VERSION 5.8 ;
BUSBITCHARS "[]" ;
DIVIDERCHAR "/" ;
UNITS
    DATABASE MICRONS 1000 ;
END UNITS

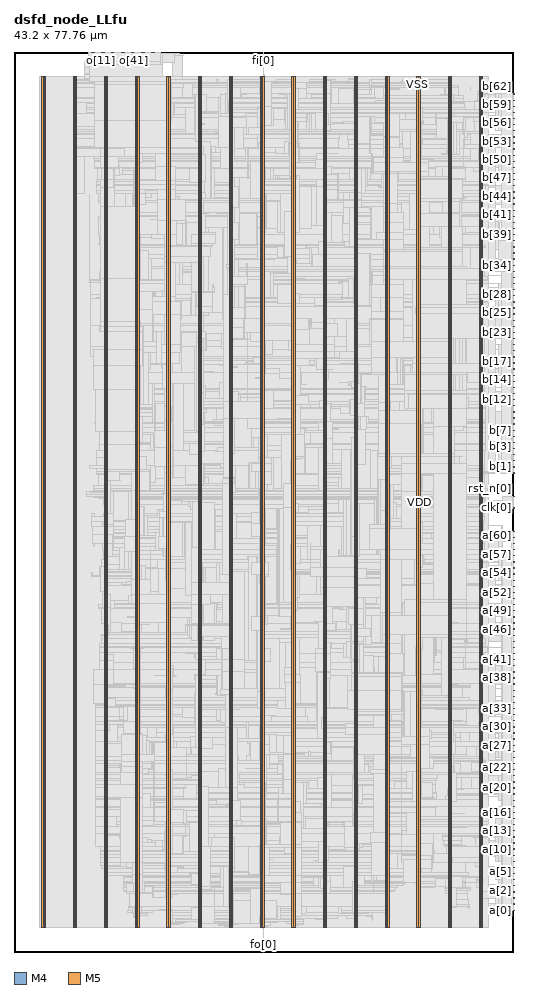
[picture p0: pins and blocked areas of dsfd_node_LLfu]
MACRO dsfd_node_LLfu
  FOREIGN dsfd_node_LLfu 0 0 ;
  CLASS BLOCK ;
  SIZE 43.2 BY 77.76 ;
  PIN a[0]
    DIRECTION INPUT ;
    USE SIGNAL ;
    PORT
      LAYER M4 ;
        RECT  43.116 3.6 43.2 3.624 ;
    END
  END a[0]
  PIN a[10]
    DIRECTION INPUT ;
    USE SIGNAL ;
    PORT
      LAYER M4 ;
        RECT  43.116 8.88 43.2 8.904 ;
    END
  END a[10]
  PIN a[11]
    DIRECTION INPUT ;
    USE SIGNAL ;
    PORT
      LAYER M4 ;
        RECT  43.116 9.408 43.2 9.432 ;
    END
  END a[11]
  PIN a[12]
    DIRECTION INPUT ;
    USE SIGNAL ;
    PORT
      LAYER M4 ;
        RECT  43.116 9.936 43.2 9.96 ;
    END
  END a[12]
  PIN a[13]
    DIRECTION INPUT ;
    USE SIGNAL ;
    PORT
      LAYER M4 ;
        RECT  43.116 10.464 43.2 10.488 ;
    END
  END a[13]
  PIN a[14]
    DIRECTION INPUT ;
    USE SIGNAL ;
    PORT
      LAYER M4 ;
        RECT  43.116 10.992 43.2 11.016 ;
    END
  END a[14]
  PIN a[15]
    DIRECTION INPUT ;
    USE SIGNAL ;
    PORT
      LAYER M4 ;
        RECT  43.116 11.52 43.2 11.544 ;
    END
  END a[15]
  PIN a[16]
    DIRECTION INPUT ;
    USE SIGNAL ;
    PORT
      LAYER M4 ;
        RECT  43.116 12.048 43.2 12.072 ;
    END
  END a[16]
  PIN a[17]
    DIRECTION INPUT ;
    USE SIGNAL ;
    PORT
      LAYER M4 ;
        RECT  43.116 12.576 43.2 12.6 ;
    END
  END a[17]
  PIN a[18]
    DIRECTION INPUT ;
    USE SIGNAL ;
    PORT
      LAYER M4 ;
        RECT  43.116 13.104 43.2 13.128 ;
    END
  END a[18]
  PIN a[19]
    DIRECTION INPUT ;
    USE SIGNAL ;
    PORT
      LAYER M4 ;
        RECT  43.116 13.632 43.2 13.656 ;
    END
  END a[19]
  PIN a[1]
    DIRECTION INPUT ;
    USE SIGNAL ;
    PORT
      LAYER M4 ;
        RECT  43.116 4.128 43.2 4.152 ;
    END
  END a[1]
  PIN a[20]
    DIRECTION INPUT ;
    USE SIGNAL ;
    PORT
      LAYER M4 ;
        RECT  43.116 14.16 43.2 14.184 ;
    END
  END a[20]
  PIN a[21]
    DIRECTION INPUT ;
    USE SIGNAL ;
    PORT
      LAYER M4 ;
        RECT  43.116 14.688 43.2 14.712 ;
    END
  END a[21]
  PIN a[22]
    DIRECTION INPUT ;
    USE SIGNAL ;
    PORT
      LAYER M4 ;
        RECT  43.116 15.216 43.2 15.24 ;
    END
  END a[22]
  PIN a[23]
    DIRECTION INPUT ;
    USE SIGNAL ;
    PORT
      LAYER M4 ;
        RECT  43.116 15.744 43.2 15.768 ;
    END
  END a[23]
  PIN a[24]
    DIRECTION INPUT ;
    USE SIGNAL ;
    PORT
      LAYER M4 ;
        RECT  43.116 16.272 43.2 16.296 ;
    END
  END a[24]
  PIN a[25]
    DIRECTION INPUT ;
    USE SIGNAL ;
    PORT
      LAYER M4 ;
        RECT  43.116 16.8 43.2 16.824 ;
    END
  END a[25]
  PIN a[26]
    DIRECTION INPUT ;
    USE SIGNAL ;
    PORT
      LAYER M4 ;
        RECT  43.116 17.328 43.2 17.352 ;
    END
  END a[26]
  PIN a[27]
    DIRECTION INPUT ;
    USE SIGNAL ;
    PORT
      LAYER M4 ;
        RECT  43.116 17.856 43.2 17.88 ;
    END
  END a[27]
  PIN a[28]
    DIRECTION INPUT ;
    USE SIGNAL ;
    PORT
      LAYER M4 ;
        RECT  43.116 18.384 43.2 18.408 ;
    END
  END a[28]
  PIN a[29]
    DIRECTION INPUT ;
    USE SIGNAL ;
    PORT
      LAYER M4 ;
        RECT  43.116 18.912 43.2 18.936 ;
    END
  END a[29]
  PIN a[2]
    DIRECTION INPUT ;
    USE SIGNAL ;
    PORT
      LAYER M4 ;
        RECT  43.116 4.656 43.2 4.68 ;
    END
  END a[2]
  PIN a[30]
    DIRECTION INPUT ;
    USE SIGNAL ;
    PORT
      LAYER M4 ;
        RECT  43.116 19.44 43.2 19.464 ;
    END
  END a[30]
  PIN a[31]
    DIRECTION INPUT ;
    USE SIGNAL ;
    PORT
      LAYER M4 ;
        RECT  43.116 19.968 43.2 19.992 ;
    END
  END a[31]
  PIN a[32]
    DIRECTION INPUT ;
    USE SIGNAL ;
    PORT
      LAYER M4 ;
        RECT  43.116 20.496 43.2 20.52 ;
    END
  END a[32]
  PIN a[33]
    DIRECTION INPUT ;
    USE SIGNAL ;
    PORT
      LAYER M4 ;
        RECT  43.116 21.024 43.2 21.048 ;
    END
  END a[33]
  PIN a[34]
    DIRECTION INPUT ;
    USE SIGNAL ;
    PORT
      LAYER M4 ;
        RECT  43.116 21.552 43.2 21.576 ;
    END
  END a[34]
  PIN a[35]
    DIRECTION INPUT ;
    USE SIGNAL ;
    PORT
      LAYER M4 ;
        RECT  43.116 22.08 43.2 22.104 ;
    END
  END a[35]
  PIN a[36]
    DIRECTION INPUT ;
    USE SIGNAL ;
    PORT
      LAYER M4 ;
        RECT  43.116 22.608 43.2 22.632 ;
    END
  END a[36]
  PIN a[37]
    DIRECTION INPUT ;
    USE SIGNAL ;
    PORT
      LAYER M4 ;
        RECT  43.116 23.136 43.2 23.16 ;
    END
  END a[37]
  PIN a[38]
    DIRECTION INPUT ;
    USE SIGNAL ;
    PORT
      LAYER M4 ;
        RECT  43.116 23.664 43.2 23.688 ;
    END
  END a[38]
  PIN a[39]
    DIRECTION INPUT ;
    USE SIGNAL ;
    PORT
      LAYER M4 ;
        RECT  43.116 24.192 43.2 24.216 ;
    END
  END a[39]
  PIN a[3]
    DIRECTION INPUT ;
    USE SIGNAL ;
    PORT
      LAYER M4 ;
        RECT  43.116 5.184 43.2 5.208 ;
    END
  END a[3]
  PIN a[40]
    DIRECTION INPUT ;
    USE SIGNAL ;
    PORT
      LAYER M4 ;
        RECT  43.116 24.72 43.2 24.744 ;
    END
  END a[40]
  PIN a[41]
    DIRECTION INPUT ;
    USE SIGNAL ;
    PORT
      LAYER M4 ;
        RECT  43.116 25.248 43.2 25.272 ;
    END
  END a[41]
  PIN a[42]
    DIRECTION INPUT ;
    USE SIGNAL ;
    PORT
      LAYER M4 ;
        RECT  43.116 25.776 43.2 25.8 ;
    END
  END a[42]
  PIN a[43]
    DIRECTION INPUT ;
    USE SIGNAL ;
    PORT
      LAYER M4 ;
        RECT  43.116 26.304 43.2 26.328 ;
    END
  END a[43]
  PIN a[44]
    DIRECTION INPUT ;
    USE SIGNAL ;
    PORT
      LAYER M4 ;
        RECT  43.116 26.832 43.2 26.856 ;
    END
  END a[44]
  PIN a[45]
    DIRECTION INPUT ;
    USE SIGNAL ;
    PORT
      LAYER M4 ;
        RECT  43.116 27.36 43.2 27.384 ;
    END
  END a[45]
  PIN a[46]
    DIRECTION INPUT ;
    USE SIGNAL ;
    PORT
      LAYER M4 ;
        RECT  43.116 27.888 43.2 27.912 ;
    END
  END a[46]
  PIN a[47]
    DIRECTION INPUT ;
    USE SIGNAL ;
    PORT
      LAYER M4 ;
        RECT  43.116 28.416 43.2 28.44 ;
    END
  END a[47]
  PIN a[48]
    DIRECTION INPUT ;
    USE SIGNAL ;
    PORT
      LAYER M4 ;
        RECT  43.116 28.944 43.2 28.968 ;
    END
  END a[48]
  PIN a[49]
    DIRECTION INPUT ;
    USE SIGNAL ;
    PORT
      LAYER M4 ;
        RECT  43.116 29.472 43.2 29.496 ;
    END
  END a[49]
  PIN a[4]
    DIRECTION INPUT ;
    USE SIGNAL ;
    PORT
      LAYER M4 ;
        RECT  43.116 5.712 43.2 5.736 ;
    END
  END a[4]
  PIN a[50]
    DIRECTION INPUT ;
    USE SIGNAL ;
    PORT
      LAYER M4 ;
        RECT  43.116 30 43.2 30.024 ;
    END
  END a[50]
  PIN a[51]
    DIRECTION INPUT ;
    USE SIGNAL ;
    PORT
      LAYER M4 ;
        RECT  43.116 30.528 43.2 30.552 ;
    END
  END a[51]
  PIN a[52]
    DIRECTION INPUT ;
    USE SIGNAL ;
    PORT
      LAYER M4 ;
        RECT  43.116 31.056 43.2 31.08 ;
    END
  END a[52]
  PIN a[53]
    DIRECTION INPUT ;
    USE SIGNAL ;
    PORT
      LAYER M4 ;
        RECT  43.116 31.584 43.2 31.608 ;
    END
  END a[53]
  PIN a[54]
    DIRECTION INPUT ;
    USE SIGNAL ;
    PORT
      LAYER M4 ;
        RECT  43.116 32.112 43.2 32.136 ;
    END
  END a[54]
  PIN a[55]
    DIRECTION INPUT ;
    USE SIGNAL ;
    PORT
      LAYER M4 ;
        RECT  43.116 32.64 43.2 32.664 ;
    END
  END a[55]
  PIN a[56]
    DIRECTION INPUT ;
    USE SIGNAL ;
    PORT
      LAYER M4 ;
        RECT  43.116 33.168 43.2 33.192 ;
    END
  END a[56]
  PIN a[57]
    DIRECTION INPUT ;
    USE SIGNAL ;
    PORT
      LAYER M4 ;
        RECT  43.116 33.696 43.2 33.72 ;
    END
  END a[57]
  PIN a[58]
    DIRECTION INPUT ;
    USE SIGNAL ;
    PORT
      LAYER M4 ;
        RECT  43.116 34.224 43.2 34.248 ;
    END
  END a[58]
  PIN a[59]
    DIRECTION INPUT ;
    USE SIGNAL ;
    PORT
      LAYER M4 ;
        RECT  43.116 34.752 43.2 34.776 ;
    END
  END a[59]
  PIN a[5]
    DIRECTION INPUT ;
    USE SIGNAL ;
    PORT
      LAYER M4 ;
        RECT  43.116 6.24 43.2 6.264 ;
    END
  END a[5]
  PIN a[60]
    DIRECTION INPUT ;
    USE SIGNAL ;
    PORT
      LAYER M4 ;
        RECT  43.116 35.28 43.2 35.304 ;
    END
  END a[60]
  PIN a[61]
    DIRECTION INPUT ;
    USE SIGNAL ;
    PORT
      LAYER M4 ;
        RECT  43.116 35.808 43.2 35.832 ;
    END
  END a[61]
  PIN a[62]
    DIRECTION INPUT ;
    USE SIGNAL ;
    PORT
      LAYER M4 ;
        RECT  43.116 36.336 43.2 36.36 ;
    END
  END a[62]
  PIN a[6]
    DIRECTION INPUT ;
    USE SIGNAL ;
    PORT
      LAYER M4 ;
        RECT  43.116 6.768 43.2 6.792 ;
    END
  END a[6]
  PIN a[7]
    DIRECTION INPUT ;
    USE SIGNAL ;
    PORT
      LAYER M4 ;
        RECT  43.116 7.296 43.2 7.32 ;
    END
  END a[7]
  PIN a[8]
    DIRECTION INPUT ;
    USE SIGNAL ;
    PORT
      LAYER M4 ;
        RECT  43.116 7.824 43.2 7.848 ;
    END
  END a[8]
  PIN a[9]
    DIRECTION INPUT ;
    USE SIGNAL ;
    PORT
      LAYER M4 ;
        RECT  43.116 8.352 43.2 8.376 ;
    END
  END a[9]
  PIN b[0]
    DIRECTION INPUT ;
    USE SIGNAL ;
    PORT
      LAYER M4 ;
        RECT  43.116 41.376 43.2 41.4 ;
    END
  END b[0]
  PIN b[10]
    DIRECTION INPUT ;
    USE SIGNAL ;
    PORT
      LAYER M4 ;
        RECT  43.116 46.656 43.2 46.68 ;
    END
  END b[10]
  PIN b[11]
    DIRECTION INPUT ;
    USE SIGNAL ;
    PORT
      LAYER M4 ;
        RECT  43.116 47.184 43.2 47.208 ;
    END
  END b[11]
  PIN b[12]
    DIRECTION INPUT ;
    USE SIGNAL ;
    PORT
      LAYER M4 ;
        RECT  43.116 47.712 43.2 47.736 ;
    END
  END b[12]
  PIN b[13]
    DIRECTION INPUT ;
    USE SIGNAL ;
    PORT
      LAYER M4 ;
        RECT  43.116 48.24 43.2 48.264 ;
    END
  END b[13]
  PIN b[14]
    DIRECTION INPUT ;
    USE SIGNAL ;
    PORT
      LAYER M4 ;
        RECT  43.116 48.768 43.2 48.792 ;
    END
  END b[14]
  PIN b[15]
    DIRECTION INPUT ;
    USE SIGNAL ;
    PORT
      LAYER M4 ;
        RECT  43.116 49.296 43.2 49.32 ;
    END
  END b[15]
  PIN b[16]
    DIRECTION INPUT ;
    USE SIGNAL ;
    PORT
      LAYER M4 ;
        RECT  43.116 49.824 43.2 49.848 ;
    END
  END b[16]
  PIN b[17]
    DIRECTION INPUT ;
    USE SIGNAL ;
    PORT
      LAYER M4 ;
        RECT  43.116 50.352 43.2 50.376 ;
    END
  END b[17]
  PIN b[18]
    DIRECTION INPUT ;
    USE SIGNAL ;
    PORT
      LAYER M4 ;
        RECT  43.116 50.88 43.2 50.904 ;
    END
  END b[18]
  PIN b[19]
    DIRECTION INPUT ;
    USE SIGNAL ;
    PORT
      LAYER M4 ;
        RECT  43.116 51.408 43.2 51.432 ;
    END
  END b[19]
  PIN b[1]
    DIRECTION INPUT ;
    USE SIGNAL ;
    PORT
      LAYER M4 ;
        RECT  43.116 41.904 43.2 41.928 ;
    END
  END b[1]
  PIN b[20]
    DIRECTION INPUT ;
    USE SIGNAL ;
    PORT
      LAYER M4 ;
        RECT  43.116 51.936 43.2 51.96 ;
    END
  END b[20]
  PIN b[21]
    DIRECTION INPUT ;
    USE SIGNAL ;
    PORT
      LAYER M4 ;
        RECT  43.116 52.464 43.2 52.488 ;
    END
  END b[21]
  PIN b[22]
    DIRECTION INPUT ;
    USE SIGNAL ;
    PORT
      LAYER M4 ;
        RECT  43.116 52.992 43.2 53.016 ;
    END
  END b[22]
  PIN b[23]
    DIRECTION INPUT ;
    USE SIGNAL ;
    PORT
      LAYER M4 ;
        RECT  43.116 53.52 43.2 53.544 ;
    END
  END b[23]
  PIN b[24]
    DIRECTION INPUT ;
    USE SIGNAL ;
    PORT
      LAYER M4 ;
        RECT  43.116 54.048 43.2 54.072 ;
    END
  END b[24]
  PIN b[25]
    DIRECTION INPUT ;
    USE SIGNAL ;
    PORT
      LAYER M4 ;
        RECT  43.116 54.576 43.2 54.6 ;
    END
  END b[25]
  PIN b[26]
    DIRECTION INPUT ;
    USE SIGNAL ;
    PORT
      LAYER M4 ;
        RECT  43.116 55.104 43.2 55.128 ;
    END
  END b[26]
  PIN b[27]
    DIRECTION INPUT ;
    USE SIGNAL ;
    PORT
      LAYER M4 ;
        RECT  43.116 55.632 43.2 55.656 ;
    END
  END b[27]
  PIN b[28]
    DIRECTION INPUT ;
    USE SIGNAL ;
    PORT
      LAYER M4 ;
        RECT  43.116 56.16 43.2 56.184 ;
    END
  END b[28]
  PIN b[29]
    DIRECTION INPUT ;
    USE SIGNAL ;
    PORT
      LAYER M4 ;
        RECT  43.116 56.688 43.2 56.712 ;
    END
  END b[29]
  PIN b[2]
    DIRECTION INPUT ;
    USE SIGNAL ;
    PORT
      LAYER M4 ;
        RECT  43.116 42.432 43.2 42.456 ;
    END
  END b[2]
  PIN b[30]
    DIRECTION INPUT ;
    USE SIGNAL ;
    PORT
      LAYER M4 ;
        RECT  43.116 57.216 43.2 57.24 ;
    END
  END b[30]
  PIN b[31]
    DIRECTION INPUT ;
    USE SIGNAL ;
    PORT
      LAYER M4 ;
        RECT  43.116 57.744 43.2 57.768 ;
    END
  END b[31]
  PIN b[32]
    DIRECTION INPUT ;
    USE SIGNAL ;
    PORT
      LAYER M4 ;
        RECT  43.116 58.272 43.2 58.296 ;
    END
  END b[32]
  PIN b[33]
    DIRECTION INPUT ;
    USE SIGNAL ;
    PORT
      LAYER M4 ;
        RECT  43.116 58.8 43.2 58.824 ;
    END
  END b[33]
  PIN b[34]
    DIRECTION INPUT ;
    USE SIGNAL ;
    PORT
      LAYER M4 ;
        RECT  43.116 59.328 43.2 59.352 ;
    END
  END b[34]
  PIN b[35]
    DIRECTION INPUT ;
    USE SIGNAL ;
    PORT
      LAYER M4 ;
        RECT  43.116 59.856 43.2 59.88 ;
    END
  END b[35]
  PIN b[36]
    DIRECTION INPUT ;
    USE SIGNAL ;
    PORT
      LAYER M4 ;
        RECT  43.116 60.384 43.2 60.408 ;
    END
  END b[36]
  PIN b[37]
    DIRECTION INPUT ;
    USE SIGNAL ;
    PORT
      LAYER M4 ;
        RECT  43.116 60.912 43.2 60.936 ;
    END
  END b[37]
  PIN b[38]
    DIRECTION INPUT ;
    USE SIGNAL ;
    PORT
      LAYER M4 ;
        RECT  43.116 61.44 43.2 61.464 ;
    END
  END b[38]
  PIN b[39]
    DIRECTION INPUT ;
    USE SIGNAL ;
    PORT
      LAYER M4 ;
        RECT  43.116 61.968 43.2 61.992 ;
    END
  END b[39]
  PIN b[3]
    DIRECTION INPUT ;
    USE SIGNAL ;
    PORT
      LAYER M4 ;
        RECT  43.116 42.96 43.2 42.984 ;
    END
  END b[3]
  PIN b[40]
    DIRECTION INPUT ;
    USE SIGNAL ;
    PORT
      LAYER M4 ;
        RECT  43.116 62.496 43.2 62.52 ;
    END
  END b[40]
  PIN b[41]
    DIRECTION INPUT ;
    USE SIGNAL ;
    PORT
      LAYER M4 ;
        RECT  43.116 63.024 43.2 63.048 ;
    END
  END b[41]
  PIN b[42]
    DIRECTION INPUT ;
    USE SIGNAL ;
    PORT
      LAYER M4 ;
        RECT  43.116 63.552 43.2 63.576 ;
    END
  END b[42]
  PIN b[43]
    DIRECTION INPUT ;
    USE SIGNAL ;
    PORT
      LAYER M4 ;
        RECT  43.116 64.08 43.2 64.104 ;
    END
  END b[43]
  PIN b[44]
    DIRECTION INPUT ;
    USE SIGNAL ;
    PORT
      LAYER M4 ;
        RECT  43.116 64.608 43.2 64.632 ;
    END
  END b[44]
  PIN b[45]
    DIRECTION INPUT ;
    USE SIGNAL ;
    PORT
      LAYER M4 ;
        RECT  43.116 65.136 43.2 65.16 ;
    END
  END b[45]
  PIN b[46]
    DIRECTION INPUT ;
    USE SIGNAL ;
    PORT
      LAYER M4 ;
        RECT  43.116 65.664 43.2 65.688 ;
    END
  END b[46]
  PIN b[47]
    DIRECTION INPUT ;
    USE SIGNAL ;
    PORT
      LAYER M4 ;
        RECT  43.116 66.192 43.2 66.216 ;
    END
  END b[47]
  PIN b[48]
    DIRECTION INPUT ;
    USE SIGNAL ;
    PORT
      LAYER M4 ;
        RECT  43.116 66.72 43.2 66.744 ;
    END
  END b[48]
  PIN b[49]
    DIRECTION INPUT ;
    USE SIGNAL ;
    PORT
      LAYER M4 ;
        RECT  43.116 67.248 43.2 67.272 ;
    END
  END b[49]
  PIN b[4]
    DIRECTION INPUT ;
    USE SIGNAL ;
    PORT
      LAYER M4 ;
        RECT  43.116 43.488 43.2 43.512 ;
    END
  END b[4]
  PIN b[50]
    DIRECTION INPUT ;
    USE SIGNAL ;
    PORT
      LAYER M4 ;
        RECT  43.116 67.776 43.2 67.8 ;
    END
  END b[50]
  PIN b[51]
    DIRECTION INPUT ;
    USE SIGNAL ;
    PORT
      LAYER M4 ;
        RECT  43.116 68.304 43.2 68.328 ;
    END
  END b[51]
  PIN b[52]
    DIRECTION INPUT ;
    USE SIGNAL ;
    PORT
      LAYER M4 ;
        RECT  43.116 68.832 43.2 68.856 ;
    END
  END b[52]
  PIN b[53]
    DIRECTION INPUT ;
    USE SIGNAL ;
    PORT
      LAYER M4 ;
        RECT  43.116 69.36 43.2 69.384 ;
    END
  END b[53]
  PIN b[54]
    DIRECTION INPUT ;
    USE SIGNAL ;
    PORT
      LAYER M4 ;
        RECT  43.116 69.888 43.2 69.912 ;
    END
  END b[54]
  PIN b[55]
    DIRECTION INPUT ;
    USE SIGNAL ;
    PORT
      LAYER M4 ;
        RECT  43.116 70.416 43.2 70.44 ;
    END
  END b[55]
  PIN b[56]
    DIRECTION INPUT ;
    USE SIGNAL ;
    PORT
      LAYER M4 ;
        RECT  43.116 70.944 43.2 70.968 ;
    END
  END b[56]
  PIN b[57]
    DIRECTION INPUT ;
    USE SIGNAL ;
    PORT
      LAYER M4 ;
        RECT  43.116 71.472 43.2 71.496 ;
    END
  END b[57]
  PIN b[58]
    DIRECTION INPUT ;
    USE SIGNAL ;
    PORT
      LAYER M4 ;
        RECT  43.116 72 43.2 72.024 ;
    END
  END b[58]
  PIN b[59]
    DIRECTION INPUT ;
    USE SIGNAL ;
    PORT
      LAYER M4 ;
        RECT  43.116 72.528 43.2 72.552 ;
    END
  END b[59]
  PIN b[5]
    DIRECTION INPUT ;
    USE SIGNAL ;
    PORT
      LAYER M4 ;
        RECT  43.116 44.016 43.2 44.04 ;
    END
  END b[5]
  PIN b[60]
    DIRECTION INPUT ;
    USE SIGNAL ;
    PORT
      LAYER M4 ;
        RECT  43.116 73.056 43.2 73.08 ;
    END
  END b[60]
  PIN b[61]
    DIRECTION INPUT ;
    USE SIGNAL ;
    PORT
      LAYER M4 ;
        RECT  43.116 73.584 43.2 73.608 ;
    END
  END b[61]
  PIN b[62]
    DIRECTION INPUT ;
    USE SIGNAL ;
    PORT
      LAYER M4 ;
        RECT  43.116 74.112 43.2 74.136 ;
    END
  END b[62]
  PIN b[6]
    DIRECTION INPUT ;
    USE SIGNAL ;
    PORT
      LAYER M4 ;
        RECT  43.116 44.544 43.2 44.568 ;
    END
  END b[6]
  PIN b[7]
    DIRECTION INPUT ;
    USE SIGNAL ;
    PORT
      LAYER M4 ;
        RECT  43.116 45.072 43.2 45.096 ;
    END
  END b[7]
  PIN b[8]
    DIRECTION INPUT ;
    USE SIGNAL ;
    PORT
      LAYER M4 ;
        RECT  43.116 45.6 43.2 45.624 ;
    END
  END b[8]
  PIN b[9]
    DIRECTION INPUT ;
    USE SIGNAL ;
    PORT
      LAYER M4 ;
        RECT  43.116 46.128 43.2 46.152 ;
    END
  END b[9]
  PIN clk[0]
    DIRECTION INPUT ;
    USE SIGNAL ;
    PORT
      LAYER M4 ;
        RECT  43.116 38.352 43.2 38.376 ;
    END
  END clk[0]
  PIN fi[0]
    DIRECTION INPUT ;
    USE SIGNAL ;
    PORT
      LAYER M5 ;
        RECT  21.552 77.676 21.576 77.76 ;
    END
  END fi[0]
  PIN fo[0]
    DIRECTION OUTPUT ;
    USE SIGNAL ;
    PORT
      LAYER M5 ;
        RECT  21.552 0 21.576 0.084 ;
    END
  END fo[0]
  PIN o[0]
    DIRECTION OUTPUT ;
    USE SIGNAL ;
    PORT
      LAYER M5 ;
        RECT  6.432 77.676 6.456 77.76 ;
    END
  END o[0]
  PIN o[10]
    DIRECTION OUTPUT ;
    USE SIGNAL ;
    PORT
      LAYER M5 ;
        RECT  7.392 77.676 7.416 77.76 ;
    END
  END o[10]
  PIN o[11]
    DIRECTION OUTPUT ;
    USE SIGNAL ;
    PORT
      LAYER M5 ;
        RECT  7.488 77.676 7.512 77.76 ;
    END
  END o[11]
  PIN o[12]
    DIRECTION OUTPUT ;
    USE SIGNAL ;
    PORT
      LAYER M5 ;
        RECT  7.584 77.676 7.608 77.76 ;
    END
  END o[12]
  PIN o[13]
    DIRECTION OUTPUT ;
    USE SIGNAL ;
    PORT
      LAYER M5 ;
        RECT  7.68 77.676 7.704 77.76 ;
    END
  END o[13]
  PIN o[14]
    DIRECTION OUTPUT ;
    USE SIGNAL ;
    PORT
      LAYER M5 ;
        RECT  7.776 77.676 7.8 77.76 ;
    END
  END o[14]
  PIN o[15]
    DIRECTION OUTPUT ;
    USE SIGNAL ;
    PORT
      LAYER M5 ;
        RECT  7.872 77.676 7.896 77.76 ;
    END
  END o[15]
  PIN o[16]
    DIRECTION OUTPUT ;
    USE SIGNAL ;
    PORT
      LAYER M5 ;
        RECT  7.968 77.676 7.992 77.76 ;
    END
  END o[16]
  PIN o[17]
    DIRECTION OUTPUT ;
    USE SIGNAL ;
    PORT
      LAYER M5 ;
        RECT  8.064 77.676 8.088 77.76 ;
    END
  END o[17]
  PIN o[18]
    DIRECTION OUTPUT ;
    USE SIGNAL ;
    PORT
      LAYER M5 ;
        RECT  8.16 77.676 8.184 77.76 ;
    END
  END o[18]
  PIN o[19]
    DIRECTION OUTPUT ;
    USE SIGNAL ;
    PORT
      LAYER M5 ;
        RECT  8.256 77.676 8.28 77.76 ;
    END
  END o[19]
  PIN o[1]
    DIRECTION OUTPUT ;
    USE SIGNAL ;
    PORT
      LAYER M5 ;
        RECT  6.528 77.676 6.552 77.76 ;
    END
  END o[1]
  PIN o[20]
    DIRECTION OUTPUT ;
    USE SIGNAL ;
    PORT
      LAYER M5 ;
        RECT  8.352 77.676 8.376 77.76 ;
    END
  END o[20]
  PIN o[21]
    DIRECTION OUTPUT ;
    USE SIGNAL ;
    PORT
      LAYER M5 ;
        RECT  8.448 77.676 8.472 77.76 ;
    END
  END o[21]
  PIN o[22]
    DIRECTION OUTPUT ;
    USE SIGNAL ;
    PORT
      LAYER M5 ;
        RECT  8.544 77.676 8.568 77.76 ;
    END
  END o[22]
  PIN o[23]
    DIRECTION OUTPUT ;
    USE SIGNAL ;
    PORT
      LAYER M5 ;
        RECT  8.64 77.676 8.664 77.76 ;
    END
  END o[23]
  PIN o[24]
    DIRECTION OUTPUT ;
    USE SIGNAL ;
    PORT
      LAYER M5 ;
        RECT  8.736 77.676 8.76 77.76 ;
    END
  END o[24]
  PIN o[25]
    DIRECTION OUTPUT ;
    USE SIGNAL ;
    PORT
      LAYER M5 ;
        RECT  8.832 77.676 8.856 77.76 ;
    END
  END o[25]
  PIN o[26]
    DIRECTION OUTPUT ;
    USE SIGNAL ;
    PORT
      LAYER M5 ;
        RECT  8.928 77.676 8.952 77.76 ;
    END
  END o[26]
  PIN o[27]
    DIRECTION OUTPUT ;
    USE SIGNAL ;
    PORT
      LAYER M5 ;
        RECT  9.024 77.676 9.048 77.76 ;
    END
  END o[27]
  PIN o[28]
    DIRECTION OUTPUT ;
    USE SIGNAL ;
    PORT
      LAYER M5 ;
        RECT  9.12 77.676 9.144 77.76 ;
    END
  END o[28]
  PIN o[29]
    DIRECTION OUTPUT ;
    USE SIGNAL ;
    PORT
      LAYER M5 ;
        RECT  9.216 77.676 9.24 77.76 ;
    END
  END o[29]
  PIN o[2]
    DIRECTION OUTPUT ;
    USE SIGNAL ;
    PORT
      LAYER M5 ;
        RECT  6.624 77.676 6.648 77.76 ;
    END
  END o[2]
  PIN o[30]
    DIRECTION OUTPUT ;
    USE SIGNAL ;
    PORT
      LAYER M5 ;
        RECT  9.312 77.676 9.336 77.76 ;
    END
  END o[30]
  PIN o[31]
    DIRECTION OUTPUT ;
    USE SIGNAL ;
    PORT
      LAYER M5 ;
        RECT  9.408 77.676 9.432 77.76 ;
    END
  END o[31]
  PIN o[32]
    DIRECTION OUTPUT ;
    USE SIGNAL ;
    PORT
      LAYER M5 ;
        RECT  9.504 77.676 9.528 77.76 ;
    END
  END o[32]
  PIN o[33]
    DIRECTION OUTPUT ;
    USE SIGNAL ;
    PORT
      LAYER M5 ;
        RECT  9.6 77.676 9.624 77.76 ;
    END
  END o[33]
  PIN o[34]
    DIRECTION OUTPUT ;
    USE SIGNAL ;
    PORT
      LAYER M5 ;
        RECT  9.696 77.676 9.72 77.76 ;
    END
  END o[34]
  PIN o[35]
    DIRECTION OUTPUT ;
    USE SIGNAL ;
    PORT
      LAYER M5 ;
        RECT  9.792 77.676 9.816 77.76 ;
    END
  END o[35]
  PIN o[36]
    DIRECTION OUTPUT ;
    USE SIGNAL ;
    PORT
      LAYER M5 ;
        RECT  9.888 77.676 9.912 77.76 ;
    END
  END o[36]
  PIN o[37]
    DIRECTION OUTPUT ;
    USE SIGNAL ;
    PORT
      LAYER M5 ;
        RECT  9.984 77.676 10.008 77.76 ;
    END
  END o[37]
  PIN o[38]
    DIRECTION OUTPUT ;
    USE SIGNAL ;
    PORT
      LAYER M5 ;
        RECT  10.08 77.676 10.104 77.76 ;
    END
  END o[38]
  PIN o[39]
    DIRECTION OUTPUT ;
    USE SIGNAL ;
    PORT
      LAYER M5 ;
        RECT  10.176 77.676 10.2 77.76 ;
    END
  END o[39]
  PIN o[3]
    DIRECTION OUTPUT ;
    USE SIGNAL ;
    PORT
      LAYER M5 ;
        RECT  6.72 77.676 6.744 77.76 ;
    END
  END o[3]
  PIN o[40]
    DIRECTION OUTPUT ;
    USE SIGNAL ;
    PORT
      LAYER M5 ;
        RECT  10.272 77.676 10.296 77.76 ;
    END
  END o[40]
  PIN o[41]
    DIRECTION OUTPUT ;
    USE SIGNAL ;
    PORT
      LAYER M5 ;
        RECT  10.368 77.676 10.392 77.76 ;
    END
  END o[41]
  PIN o[42]
    DIRECTION OUTPUT ;
    USE SIGNAL ;
    PORT
      LAYER M5 ;
        RECT  10.464 77.676 10.488 77.76 ;
    END
  END o[42]
  PIN o[43]
    DIRECTION OUTPUT ;
    USE SIGNAL ;
    PORT
      LAYER M5 ;
        RECT  10.56 77.676 10.584 77.76 ;
    END
  END o[43]
  PIN o[44]
    DIRECTION OUTPUT ;
    USE SIGNAL ;
    PORT
      LAYER M5 ;
        RECT  10.656 77.676 10.68 77.76 ;
    END
  END o[44]
  PIN o[45]
    DIRECTION OUTPUT ;
    USE SIGNAL ;
    PORT
      LAYER M5 ;
        RECT  10.752 77.676 10.776 77.76 ;
    END
  END o[45]
  PIN o[46]
    DIRECTION OUTPUT ;
    USE SIGNAL ;
    PORT
      LAYER M5 ;
        RECT  10.848 77.676 10.872 77.76 ;
    END
  END o[46]
  PIN o[47]
    DIRECTION OUTPUT ;
    USE SIGNAL ;
    PORT
      LAYER M5 ;
        RECT  10.944 77.676 10.968 77.76 ;
    END
  END o[47]
  PIN o[48]
    DIRECTION OUTPUT ;
    USE SIGNAL ;
    PORT
      LAYER M5 ;
        RECT  11.04 77.676 11.064 77.76 ;
    END
  END o[48]
  PIN o[49]
    DIRECTION OUTPUT ;
    USE SIGNAL ;
    PORT
      LAYER M5 ;
        RECT  11.136 77.676 11.16 77.76 ;
    END
  END o[49]
  PIN o[4]
    DIRECTION OUTPUT ;
    USE SIGNAL ;
    PORT
      LAYER M5 ;
        RECT  6.816 77.676 6.84 77.76 ;
    END
  END o[4]
  PIN o[50]
    DIRECTION OUTPUT ;
    USE SIGNAL ;
    PORT
      LAYER M5 ;
        RECT  11.232 77.676 11.256 77.76 ;
    END
  END o[50]
  PIN o[51]
    DIRECTION OUTPUT ;
    USE SIGNAL ;
    PORT
      LAYER M5 ;
        RECT  11.328 77.676 11.352 77.76 ;
    END
  END o[51]
  PIN o[52]
    DIRECTION OUTPUT ;
    USE SIGNAL ;
    PORT
      LAYER M5 ;
        RECT  11.424 77.676 11.448 77.76 ;
    END
  END o[52]
  PIN o[53]
    DIRECTION OUTPUT ;
    USE SIGNAL ;
    PORT
      LAYER M5 ;
        RECT  11.52 77.676 11.544 77.76 ;
    END
  END o[53]
  PIN o[54]
    DIRECTION OUTPUT ;
    USE SIGNAL ;
    PORT
      LAYER M5 ;
        RECT  11.616 77.676 11.64 77.76 ;
    END
  END o[54]
  PIN o[55]
    DIRECTION OUTPUT ;
    USE SIGNAL ;
    PORT
      LAYER M5 ;
        RECT  11.712 77.676 11.736 77.76 ;
    END
  END o[55]
  PIN o[56]
    DIRECTION OUTPUT ;
    USE SIGNAL ;
    PORT
      LAYER M5 ;
        RECT  11.808 77.676 11.832 77.76 ;
    END
  END o[56]
  PIN o[57]
    DIRECTION OUTPUT ;
    USE SIGNAL ;
    PORT
      LAYER M5 ;
        RECT  11.904 77.676 11.928 77.76 ;
    END
  END o[57]
  PIN o[58]
    DIRECTION OUTPUT ;
    USE SIGNAL ;
    PORT
      LAYER M5 ;
        RECT  12 77.676 12.024 77.76 ;
    END
  END o[58]
  PIN o[59]
    DIRECTION OUTPUT ;
    USE SIGNAL ;
    PORT
      LAYER M5 ;
        RECT  12.096 77.676 12.12 77.76 ;
    END
  END o[59]
  PIN o[5]
    DIRECTION OUTPUT ;
    USE SIGNAL ;
    PORT
      LAYER M5 ;
        RECT  6.912 77.676 6.936 77.76 ;
    END
  END o[5]
  PIN o[60]
    DIRECTION OUTPUT ;
    USE SIGNAL ;
    PORT
      LAYER M5 ;
        RECT  12.192 77.676 12.216 77.76 ;
    END
  END o[60]
  PIN o[61]
    DIRECTION OUTPUT ;
    USE SIGNAL ;
    PORT
      LAYER M5 ;
        RECT  12.288 77.676 12.312 77.76 ;
    END
  END o[61]
  PIN o[62]
    DIRECTION OUTPUT ;
    USE SIGNAL ;
    PORT
      LAYER M5 ;
        RECT  12.384 77.676 12.408 77.76 ;
    END
  END o[62]
  PIN o[63]
    DIRECTION OUTPUT ;
    USE SIGNAL ;
    PORT
      LAYER M5 ;
        RECT  12.48 77.676 12.504 77.76 ;
    END
  END o[63]
  PIN o[64]
    DIRECTION OUTPUT ;
    USE SIGNAL ;
    PORT
      LAYER M5 ;
        RECT  12.576 77.676 12.6 77.76 ;
    END
  END o[64]
  PIN o[65]
    DIRECTION OUTPUT ;
    USE SIGNAL ;
    PORT
      LAYER M5 ;
        RECT  12.672 77.676 12.696 77.76 ;
    END
  END o[65]
  PIN o[6]
    DIRECTION OUTPUT ;
    USE SIGNAL ;
    PORT
      LAYER M5 ;
        RECT  7.008 77.676 7.032 77.76 ;
    END
  END o[6]
  PIN o[7]
    DIRECTION OUTPUT ;
    USE SIGNAL ;
    PORT
      LAYER M5 ;
        RECT  7.104 77.676 7.128 77.76 ;
    END
  END o[7]
  PIN o[8]
    DIRECTION OUTPUT ;
    USE SIGNAL ;
    PORT
      LAYER M5 ;
        RECT  7.2 77.676 7.224 77.76 ;
    END
  END o[8]
  PIN o[9]
    DIRECTION OUTPUT ;
    USE SIGNAL ;
    PORT
      LAYER M5 ;
        RECT  7.296 77.676 7.32 77.76 ;
    END
  END o[9]
  PIN rst_n[0]
    DIRECTION INPUT ;
    USE SIGNAL ;
    PORT
      LAYER M4 ;
        RECT  43.116 39.36 43.2 39.384 ;
    END
  END rst_n[0]
  PIN VDD
    DIRECTION INOUT ;
    USE POWER ;
    PORT
      LAYER M5 ;
        RECT  40.392 2.151 40.512 75.609 ;
        RECT  37.692 2.151 37.812 75.609 ;
        RECT  34.992 2.151 35.112 75.609 ;
        RECT  32.292 2.151 32.412 75.609 ;
        RECT  29.592 2.151 29.712 75.609 ;
        RECT  26.892 2.151 27.012 75.609 ;
        RECT  24.192 2.151 24.312 75.609 ;
        RECT  21.492 2.151 21.612 75.609 ;
        RECT  18.792 2.151 18.912 75.609 ;
        RECT  16.092 2.151 16.212 75.609 ;
        RECT  13.392 2.151 13.512 75.609 ;
        RECT  10.692 2.151 10.812 75.609 ;
        RECT  7.992 2.151 8.112 75.609 ;
        RECT  5.292 2.151 5.412 75.609 ;
        RECT  2.592 2.151 2.712 75.609 ;
    END
  END VDD
  PIN VSS
    DIRECTION INOUT ;
    USE GROUND ;
    PORT
      LAYER M5 ;
        RECT  40.2 2.137 40.32 75.623 ;
        RECT  37.5 2.137 37.62 75.623 ;
        RECT  34.8 2.137 34.92 75.623 ;
        RECT  32.1 2.137 32.22 75.623 ;
        RECT  29.4 2.137 29.52 75.623 ;
        RECT  26.7 2.137 26.82 75.623 ;
        RECT  24 2.137 24.12 75.623 ;
        RECT  21.3 2.137 21.42 75.623 ;
        RECT  18.6 2.137 18.72 75.623 ;
        RECT  15.9 2.137 16.02 75.623 ;
        RECT  13.2 2.137 13.32 75.623 ;
        RECT  10.5 2.137 10.62 75.623 ;
        RECT  7.8 2.137 7.92 75.623 ;
        RECT  5.1 2.137 5.22 75.623 ;
        RECT  2.4 2.137 2.52 75.623 ;
    END
  END VSS
  OBS
    LAYER RVTN ;
     RECT  2.16 2.16 41.04 2.295 ;
     RECT  2.16 2.565 41.04 2.835 ;
     RECT  2.16 3.105 41.04 3.375 ;
     RECT  2.16 3.645 41.04 3.915 ;
     RECT  2.16 4.185 41.04 4.455 ;
     RECT  2.16 4.725 41.04 4.995 ;
     RECT  2.16 5.265 41.04 5.535 ;
     RECT  2.16 5.805 41.04 6.075 ;
     RECT  2.16 6.345 41.04 6.615 ;
     RECT  2.16 6.885 41.04 7.155 ;
     RECT  2.16 7.425 41.04 7.695 ;
     RECT  2.16 7.965 41.04 8.235 ;
     RECT  2.16 8.505 41.04 8.775 ;
     RECT  2.16 9.045 41.04 9.315 ;
     RECT  2.16 9.585 41.04 9.855 ;
     RECT  2.16 10.125 41.04 10.395 ;
     RECT  2.16 10.665 41.04 10.935 ;
     RECT  2.16 11.205 41.04 11.475 ;
     RECT  2.16 11.745 41.04 12.015 ;
     RECT  2.16 12.285 41.04 12.555 ;
     RECT  2.16 12.825 41.04 13.095 ;
     RECT  2.16 13.365 41.04 13.635 ;
     RECT  2.16 13.905 41.04 14.175 ;
     RECT  2.16 14.445 41.04 14.715 ;
     RECT  2.16 14.985 41.04 15.255 ;
     RECT  2.16 15.525 41.04 15.795 ;
     RECT  2.16 16.065 41.04 16.335 ;
     RECT  2.16 16.605 41.04 16.875 ;
     RECT  2.16 17.145 41.04 17.415 ;
     RECT  2.16 17.685 41.04 17.955 ;
     RECT  2.16 18.225 41.04 18.495 ;
     RECT  2.16 18.765 41.04 19.035 ;
     RECT  2.16 19.305 41.04 19.575 ;
     RECT  2.16 19.845 41.04 20.115 ;
     RECT  2.16 20.385 41.04 20.655 ;
     RECT  2.16 20.925 41.04 21.195 ;
     RECT  2.16 21.465 41.04 21.735 ;
     RECT  2.16 22.005 41.04 22.275 ;
     RECT  2.16 22.545 41.04 22.815 ;
     RECT  2.16 23.085 41.04 23.355 ;
     RECT  2.16 23.625 41.04 23.895 ;
     RECT  2.16 24.165 41.04 24.435 ;
     RECT  2.16 24.705 41.04 24.975 ;
     RECT  2.16 25.245 41.04 25.515 ;
     RECT  2.16 25.785 41.04 26.055 ;
     RECT  2.16 26.325 41.04 26.595 ;
     RECT  2.16 26.865 41.04 27.135 ;
     RECT  2.16 27.405 41.04 27.675 ;
     RECT  2.16 27.945 41.04 28.215 ;
     RECT  2.16 28.485 41.04 28.755 ;
     RECT  2.16 29.025 41.04 29.295 ;
     RECT  2.16 29.565 41.04 29.835 ;
     RECT  2.16 30.105 41.04 30.375 ;
     RECT  2.16 30.645 41.04 30.915 ;
     RECT  2.16 31.185 41.04 31.455 ;
     RECT  2.16 31.725 41.04 31.995 ;
     RECT  2.16 32.265 41.04 32.535 ;
     RECT  2.16 32.805 41.04 33.075 ;
     RECT  2.16 33.345 41.04 33.615 ;
     RECT  2.16 33.885 41.04 34.155 ;
     RECT  2.16 34.425 41.04 34.695 ;
     RECT  2.16 34.965 41.04 35.235 ;
     RECT  2.16 35.505 41.04 35.775 ;
     RECT  2.16 36.045 41.04 36.315 ;
     RECT  2.16 36.585 41.04 36.855 ;
     RECT  2.16 37.125 41.04 37.395 ;
     RECT  2.16 37.665 41.04 37.935 ;
     RECT  2.16 38.205 41.04 38.475 ;
     RECT  2.16 38.745 41.04 39.015 ;
     RECT  2.16 39.285 41.04 39.555 ;
     RECT  2.16 39.825 41.04 40.095 ;
     RECT  2.16 40.365 41.04 40.635 ;
     RECT  2.16 40.905 41.04 41.175 ;
     RECT  2.16 41.445 41.04 41.715 ;
     RECT  2.16 41.985 41.04 42.255 ;
     RECT  2.16 42.525 41.04 42.795 ;
     RECT  2.16 43.065 41.04 43.335 ;
     RECT  2.16 43.605 41.04 43.875 ;
     RECT  2.16 44.145 41.04 44.415 ;
     RECT  2.16 44.685 41.04 44.955 ;
     RECT  2.16 45.225 41.04 45.495 ;
     RECT  2.16 45.765 41.04 46.035 ;
     RECT  2.16 46.305 41.04 46.575 ;
     RECT  2.16 46.845 41.04 47.115 ;
     RECT  2.16 47.385 41.04 47.655 ;
     RECT  2.16 47.925 41.04 48.195 ;
     RECT  2.16 48.465 41.04 48.735 ;
     RECT  2.16 49.005 41.04 49.275 ;
     RECT  2.16 49.545 41.04 49.815 ;
     RECT  2.16 50.085 41.04 50.355 ;
     RECT  2.16 50.625 41.04 50.895 ;
     RECT  2.16 51.165 41.04 51.435 ;
     RECT  2.16 51.705 41.04 51.975 ;
     RECT  2.16 52.245 41.04 52.515 ;
     RECT  2.16 52.785 41.04 53.055 ;
     RECT  2.16 53.325 41.04 53.595 ;
     RECT  2.16 53.865 41.04 54.135 ;
     RECT  2.16 54.405 41.04 54.675 ;
     RECT  2.16 54.945 41.04 55.215 ;
     RECT  2.16 55.485 41.04 55.755 ;
     RECT  2.16 56.025 41.04 56.295 ;
     RECT  2.16 56.565 41.04 56.835 ;
     RECT  2.16 57.105 41.04 57.375 ;
     RECT  2.16 57.645 41.04 57.915 ;
     RECT  2.16 58.185 41.04 58.455 ;
     RECT  2.16 58.725 41.04 58.995 ;
     RECT  2.16 59.265 41.04 59.535 ;
     RECT  2.16 59.805 41.04 60.075 ;
     RECT  2.16 60.345 41.04 60.615 ;
     RECT  2.16 60.885 41.04 61.155 ;
     RECT  2.16 61.425 41.04 61.695 ;
     RECT  2.16 61.965 41.04 62.235 ;
     RECT  2.16 62.505 41.04 62.775 ;
     RECT  2.16 63.045 41.04 63.315 ;
     RECT  2.16 63.585 41.04 63.855 ;
     RECT  2.16 64.125 41.04 64.395 ;
     RECT  2.16 64.665 41.04 64.935 ;
     RECT  2.16 65.205 41.04 65.475 ;
     RECT  2.16 65.745 41.04 66.015 ;
     RECT  2.16 66.285 41.04 66.555 ;
     RECT  2.16 66.825 41.04 67.095 ;
     RECT  2.16 67.365 41.04 67.635 ;
     RECT  2.16 67.905 41.04 68.175 ;
     RECT  2.16 68.445 41.04 68.715 ;
     RECT  2.16 68.985 41.04 69.255 ;
     RECT  2.16 69.525 41.04 69.795 ;
     RECT  2.16 70.065 41.04 70.335 ;
     RECT  2.16 70.605 41.04 70.875 ;
     RECT  2.16 71.145 41.04 71.415 ;
     RECT  2.16 71.685 41.04 71.955 ;
     RECT  2.16 72.225 41.04 72.495 ;
     RECT  2.16 72.765 41.04 73.035 ;
     RECT  2.16 73.305 41.04 73.575 ;
     RECT  2.16 73.845 41.04 74.115 ;
     RECT  2.16 74.385 41.04 74.655 ;
     RECT  2.16 74.925 41.04 75.195 ;
     RECT  2.16 75.465 41.04 75.6 ;
    LAYER RVTP ;
     RECT  2.16 2.295 41.04 2.565 ;
     RECT  2.16 2.835 41.04 3.105 ;
     RECT  2.16 3.375 41.04 3.645 ;
     RECT  2.16 3.915 41.04 4.185 ;
     RECT  2.16 4.455 41.04 4.725 ;
     RECT  2.16 4.995 41.04 5.265 ;
     RECT  2.16 5.535 41.04 5.805 ;
     RECT  2.16 6.075 41.04 6.345 ;
     RECT  2.16 6.615 41.04 6.885 ;
     RECT  2.16 7.155 41.04 7.425 ;
     RECT  2.16 7.695 41.04 7.965 ;
     RECT  2.16 8.235 41.04 8.505 ;
     RECT  2.16 8.775 41.04 9.045 ;
     RECT  2.16 9.315 41.04 9.585 ;
     RECT  2.16 9.855 41.04 10.125 ;
     RECT  2.16 10.395 41.04 10.665 ;
     RECT  2.16 10.935 41.04 11.205 ;
     RECT  2.16 11.475 41.04 11.745 ;
     RECT  2.16 12.015 41.04 12.285 ;
     RECT  2.16 12.555 41.04 12.825 ;
     RECT  2.16 13.095 41.04 13.365 ;
     RECT  2.16 13.635 41.04 13.905 ;
     RECT  2.16 14.175 41.04 14.445 ;
     RECT  2.16 14.715 41.04 14.985 ;
     RECT  2.16 15.255 41.04 15.525 ;
     RECT  2.16 15.795 41.04 16.065 ;
     RECT  2.16 16.335 41.04 16.605 ;
     RECT  2.16 16.875 41.04 17.145 ;
     RECT  2.16 17.415 41.04 17.685 ;
     RECT  2.16 17.955 41.04 18.225 ;
     RECT  2.16 18.495 41.04 18.765 ;
     RECT  2.16 19.035 41.04 19.305 ;
     RECT  2.16 19.575 41.04 19.845 ;
     RECT  2.16 20.115 41.04 20.385 ;
     RECT  2.16 20.655 41.04 20.925 ;
     RECT  2.16 21.195 41.04 21.465 ;
     RECT  2.16 21.735 41.04 22.005 ;
     RECT  2.16 22.275 41.04 22.545 ;
     RECT  2.16 22.815 41.04 23.085 ;
     RECT  2.16 23.355 41.04 23.625 ;
     RECT  2.16 23.895 41.04 24.165 ;
     RECT  2.16 24.435 41.04 24.705 ;
     RECT  2.16 24.975 41.04 25.245 ;
     RECT  2.16 25.515 41.04 25.785 ;
     RECT  2.16 26.055 41.04 26.325 ;
     RECT  2.16 26.595 41.04 26.865 ;
     RECT  2.16 27.135 41.04 27.405 ;
     RECT  2.16 27.675 41.04 27.945 ;
     RECT  2.16 28.215 41.04 28.485 ;
     RECT  2.16 28.755 41.04 29.025 ;
     RECT  2.16 29.295 41.04 29.565 ;
     RECT  2.16 29.835 41.04 30.105 ;
     RECT  2.16 30.375 41.04 30.645 ;
     RECT  2.16 30.915 41.04 31.185 ;
     RECT  2.16 31.455 41.04 31.725 ;
     RECT  2.16 31.995 41.04 32.265 ;
     RECT  2.16 32.535 41.04 32.805 ;
     RECT  2.16 33.075 41.04 33.345 ;
     RECT  2.16 33.615 41.04 33.885 ;
     RECT  2.16 34.155 41.04 34.425 ;
     RECT  2.16 34.695 41.04 34.965 ;
     RECT  2.16 35.235 41.04 35.505 ;
     RECT  2.16 35.775 41.04 36.045 ;
     RECT  2.16 36.315 41.04 36.585 ;
     RECT  2.16 36.855 41.04 37.125 ;
     RECT  2.16 37.395 41.04 37.665 ;
     RECT  2.16 37.935 41.04 38.205 ;
     RECT  2.16 38.475 41.04 38.745 ;
     RECT  2.16 39.015 41.04 39.285 ;
     RECT  2.16 39.555 41.04 39.825 ;
     RECT  2.16 40.095 41.04 40.365 ;
     RECT  2.16 40.635 41.04 40.905 ;
     RECT  2.16 41.175 41.04 41.445 ;
     RECT  2.16 41.715 41.04 41.985 ;
     RECT  2.16 42.255 41.04 42.525 ;
     RECT  2.16 42.795 41.04 43.065 ;
     RECT  2.16 43.335 41.04 43.605 ;
     RECT  2.16 43.875 41.04 44.145 ;
     RECT  2.16 44.415 41.04 44.685 ;
     RECT  2.16 44.955 41.04 45.225 ;
     RECT  2.16 45.495 41.04 45.765 ;
     RECT  2.16 46.035 41.04 46.305 ;
     RECT  2.16 46.575 41.04 46.845 ;
     RECT  2.16 47.115 41.04 47.385 ;
     RECT  2.16 47.655 41.04 47.925 ;
     RECT  2.16 48.195 41.04 48.465 ;
     RECT  2.16 48.735 41.04 49.005 ;
     RECT  2.16 49.275 41.04 49.545 ;
     RECT  2.16 49.815 41.04 50.085 ;
     RECT  2.16 50.355 41.04 50.625 ;
     RECT  2.16 50.895 41.04 51.165 ;
     RECT  2.16 51.435 41.04 51.705 ;
     RECT  2.16 51.975 41.04 52.245 ;
     RECT  2.16 52.515 41.04 52.785 ;
     RECT  2.16 53.055 41.04 53.325 ;
     RECT  2.16 53.595 41.04 53.865 ;
     RECT  2.16 54.135 41.04 54.405 ;
     RECT  2.16 54.675 41.04 54.945 ;
     RECT  2.16 55.215 41.04 55.485 ;
     RECT  2.16 55.755 41.04 56.025 ;
     RECT  2.16 56.295 41.04 56.565 ;
     RECT  2.16 56.835 41.04 57.105 ;
     RECT  2.16 57.375 41.04 57.645 ;
     RECT  2.16 57.915 41.04 58.185 ;
     RECT  2.16 58.455 41.04 58.725 ;
     RECT  2.16 58.995 41.04 59.265 ;
     RECT  2.16 59.535 41.04 59.805 ;
     RECT  2.16 60.075 41.04 60.345 ;
     RECT  2.16 60.615 41.04 60.885 ;
     RECT  2.16 61.155 41.04 61.425 ;
     RECT  2.16 61.695 41.04 61.965 ;
     RECT  2.16 62.235 41.04 62.505 ;
     RECT  2.16 62.775 41.04 63.045 ;
     RECT  2.16 63.315 41.04 63.585 ;
     RECT  2.16 63.855 41.04 64.125 ;
     RECT  2.16 64.395 41.04 64.665 ;
     RECT  2.16 64.935 41.04 65.205 ;
     RECT  2.16 65.475 41.04 65.745 ;
     RECT  2.16 66.015 41.04 66.285 ;
     RECT  2.16 66.555 41.04 66.825 ;
     RECT  2.16 67.095 41.04 67.365 ;
     RECT  2.16 67.635 41.04 67.905 ;
     RECT  2.16 68.175 41.04 68.445 ;
     RECT  2.16 68.715 41.04 68.985 ;
     RECT  2.16 69.255 41.04 69.525 ;
     RECT  2.16 69.795 41.04 70.065 ;
     RECT  2.16 70.335 41.04 70.605 ;
     RECT  2.16 70.875 41.04 71.145 ;
     RECT  2.16 71.415 41.04 71.685 ;
     RECT  2.16 71.955 41.04 72.225 ;
     RECT  2.16 72.495 41.04 72.765 ;
     RECT  2.16 73.035 41.04 73.305 ;
     RECT  2.16 73.575 41.04 73.845 ;
     RECT  2.16 74.115 41.04 74.385 ;
     RECT  2.16 74.655 41.04 74.925 ;
     RECT  2.16 75.195 41.04 75.465 ;
    LAYER M1 ;
     RECT  2.16 2.151 41.04 75.609 ;
    LAYER M2 ;
     RECT  2.16 2.151 41.04 75.609 ;
     RECT  41.04 8.28 41.063 10.656 ;
     RECT  41.04 3.618 41.603 4.176 ;
     RECT  41.04 6.66 41.603 7.416 ;
     RECT  41.063 8.28 41.603 9.648 ;
     RECT  41.04 11.718 41.603 12.546 ;
     RECT  41.04 16.578 41.603 19.566 ;
     RECT  41.04 20.358 41.603 25.812 ;
     RECT  41.04 28.188 41.603 30.096 ;
     RECT  41.04 30.888 41.603 33.408 ;
     RECT  41.04 41.958 41.603 44.136 ;
     RECT  41.04 44.928 41.603 49.302 ;
     RECT  41.04 50.058 41.603 55.206 ;
     RECT  41.04 56.268 41.603 57.438 ;
     RECT  41.04 59.238 41.603 65.268 ;
     RECT  41.04 66.06 41.603 67.896 ;
     RECT  41.04 68.958 41.603 70.596 ;
     RECT  41.04 71.46 41.603 72.288 ;
     RECT  41.04 73.35 41.603 74.106 ;
     RECT  41.603 44.928 41.639 45.288 ;
     RECT  41.603 46.08 41.639 46.098 ;
     RECT  41.603 9.09 41.855 9.108 ;
     RECT  41.04 13.41 41.855 13.428 ;
     RECT  41.04 14.22 41.855 15.246 ;
     RECT  41.603 18 41.855 18.558 ;
     RECT  41.603 21.24 41.855 21.726 ;
     RECT  41.603 30.888 41.855 31.716 ;
     RECT  41.603 32.85 41.855 33.408 ;
     RECT  41.04 34.47 41.855 36.036 ;
     RECT  41.603 43.11 41.855 43.668 ;
     RECT  41.603 50.94 41.855 50.958 ;
     RECT  41.603 57.42 41.855 57.438 ;
     RECT  41.603 60.66 41.855 63.108 ;
     RECT  41.603 66.798 41.855 67.428 ;
     RECT  41.603 71.73 41.855 71.748 ;
     RECT  41.04 5.85 41.927 5.868 ;
     RECT  41.855 32.85 41.927 32.868 ;
     RECT  41.855 43.65 41.927 43.668 ;
     RECT  41.603 52.02 41.927 52.038 ;
     RECT  41.855 62.208 41.927 63.108 ;
     RECT  41.603 6.822 42.179 7.416 ;
     RECT  41.063 10.638 42.179 10.656 ;
     RECT  41.603 12.258 42.179 12.546 ;
     RECT  41.855 14.688 42.179 15.246 ;
     RECT  41.603 16.578 42.179 16.596 ;
     RECT  41.603 19.548 42.179 19.566 ;
     RECT  41.603 20.358 42.179 20.376 ;
     RECT  41.855 21.708 42.179 21.726 ;
     RECT  41.603 22.788 42.179 22.806 ;
     RECT  41.603 25.488 42.179 25.812 ;
     RECT  41.04 26.802 42.179 27.36 ;
     RECT  41.603 28.998 42.179 29.016 ;
     RECT  41.603 30.078 42.179 30.096 ;
     RECT  41.855 30.888 42.179 30.906 ;
     RECT  41.855 31.698 42.179 31.716 ;
     RECT  41.855 35.01 42.179 36.036 ;
     RECT  41.04 36.828 42.179 36.846 ;
     RECT  41.639 44.928 42.179 44.946 ;
     RECT  41.603 47.358 42.179 48.456 ;
     RECT  41.603 49.284 42.179 49.302 ;
     RECT  41.603 52.992 42.179 55.206 ;
     RECT  41.603 56.268 42.179 56.286 ;
     RECT  41.04 58.428 42.179 58.446 ;
     RECT  41.927 62.208 42.179 62.532 ;
     RECT  41.603 64.098 42.179 64.116 ;
     RECT  41.855 66.798 42.179 66.816 ;
     RECT  41.603 69.498 42.179 70.596 ;
     RECT  42.179 35.01 42.215 35.496 ;
     RECT  41.04 39.024 42.215 39.042 ;
     RECT  42.215 35.478 43.043 35.496 ;
     RECT  41.603 59.778 43.043 59.796 ;
     RECT  42.179 62.208 43.115 62.226 ;
    LAYER M3 ;
     RECT  21.456 2.011 21.474 2.143 ;
     RECT  18.615 2.143 18.705 2.191 ;
     RECT  21.315 2.143 21.474 2.191 ;
     RECT  18.18 2.191 18.705 2.263 ;
     RECT  21.315 2.191 21.906 2.263 ;
     RECT  18.18 2.263 18.774 2.299 ;
     RECT  24.015 2.143 24.105 2.299 ;
     RECT  14.292 2.335 14.31 2.371 ;
     RECT  17.676 2.299 18.954 2.371 ;
     RECT  24.015 2.299 24.57 2.371 ;
     RECT  2.415 2.143 2.505 2.413 ;
     RECT  5.115 2.143 5.205 2.413 ;
     RECT  7.815 2.143 7.905 2.413 ;
     RECT  10.515 2.143 10.605 2.413 ;
     RECT  13.215 2.143 13.305 2.413 ;
     RECT  14.076 2.371 14.31 2.413 ;
     RECT  15.915 2.143 16.005 2.413 ;
     RECT  26.715 2.143 26.805 2.413 ;
     RECT  29.415 2.143 29.505 2.413 ;
     RECT  32.115 2.143 32.205 2.413 ;
     RECT  34.815 2.143 34.905 2.413 ;
     RECT  37.515 2.143 37.605 2.413 ;
     RECT  40.215 2.143 40.305 2.413 ;
     RECT  17.676 2.371 19.278 2.491 ;
     RECT  13.215 2.413 14.31 2.497 ;
     RECT  17.1 2.491 19.278 2.497 ;
     RECT  24.015 2.371 25.038 2.497 ;
     RECT  13.215 2.497 14.634 2.533 ;
     RECT  17.1 2.497 19.854 2.539 ;
     RECT  21.315 2.263 22.122 2.569 ;
     RECT  13.215 2.533 14.886 2.641 ;
     RECT  15.915 2.413 16.197 2.641 ;
     RECT  17.1 2.539 19.962 2.641 ;
     RECT  21.315 2.569 22.77 2.641 ;
     RECT  23.58 2.497 25.038 2.641 ;
     RECT  17.1 2.641 20.466 2.803 ;
     RECT  21.315 2.641 25.038 2.803 ;
     RECT  26.715 2.413 26.997 2.839 ;
     RECT  26.064 2.839 26.997 2.875 ;
     RECT  13.215 2.641 16.197 2.911 ;
     RECT  17.1 2.803 25.038 2.911 ;
     RECT  25.956 2.875 27.918 2.911 ;
     RECT  29.415 2.413 29.697 2.911 ;
     RECT  30.996 2.731 31.014 2.911 ;
     RECT  10.515 2.413 10.797 3.001 ;
     RECT  30.888 2.911 31.014 3.037 ;
     RECT  30.564 3.037 31.014 3.073 ;
     RECT  10.332 3.001 10.797 3.109 ;
     RECT  10.332 3.109 10.89 3.145 ;
     RECT  13.215 2.911 27.918 3.145 ;
     RECT  28.692 2.911 29.697 3.145 ;
     RECT  13.215 3.145 29.697 3.181 ;
     RECT  30.492 3.073 31.014 3.181 ;
     RECT  10.332 3.145 11.538 3.307 ;
     RECT  10.26 3.307 11.538 3.379 ;
     RECT  13.215 3.181 31.014 3.379 ;
     RECT  32.115 2.413 32.397 3.379 ;
     RECT  10.116 3.379 11.97 3.415 ;
     RECT  9.792 3.415 11.97 3.569 ;
     RECT  9.9 3.569 11.97 3.577 ;
     RECT  13.215 3.379 32.397 3.577 ;
     RECT  37.515 2.413 37.797 3.811 ;
     RECT  39.348 3.721 39.366 3.811 ;
     RECT  9.9 3.577 32.397 3.917 ;
     RECT  37.515 3.811 38.214 3.919 ;
     RECT  39.204 3.811 39.366 3.919 ;
     RECT  37.515 3.919 39.366 4.145 ;
     RECT  41.58 3.595 41.598 4.181 ;
     RECT  37.515 4.145 39.258 4.559 ;
     RECT  40.215 2.413 40.497 4.651 ;
     RECT  9.936 3.917 32.397 5.035 ;
     RECT  37.515 4.559 39.222 5.071 ;
     RECT  9.756 5.035 32.397 5.227 ;
     RECT  40.215 4.651 41.022 5.261 ;
     RECT  9.72 5.227 32.397 5.269 ;
     RECT  9.576 5.269 32.778 5.341 ;
     RECT  37.296 5.071 39.222 5.341 ;
     RECT  37.296 5.341 39.438 5.467 ;
     RECT  37.224 5.467 39.438 5.567 ;
     RECT  9.468 5.341 32.958 5.575 ;
     RECT  40.215 5.261 40.497 5.575 ;
     RECT  9.468 5.575 33.102 5.611 ;
     RECT  34.815 2.413 35.097 5.611 ;
     RECT  34.815 5.611 36.306 5.659 ;
     RECT  37.224 5.567 38.97 5.659 ;
     RECT  9.468 5.611 33.174 5.737 ;
     RECT  41.904 5.707 41.922 5.873 ;
     RECT  9.468 5.737 33.642 5.881 ;
     RECT  34.815 5.659 38.97 5.881 ;
     RECT  9.468 5.881 33.786 6.007 ;
     RECT  9.468 6.007 33.858 6.079 ;
     RECT  34.668 5.881 38.97 6.079 ;
     RECT  39.924 5.575 40.497 6.151 ;
     RECT  39.924 6.151 40.59 6.305 ;
     RECT  9.468 6.079 38.97 6.421 ;
     RECT  39.924 6.305 40.497 6.421 ;
     RECT  9.468 6.421 40.497 6.539 ;
     RECT  7.815 2.413 8.097 6.583 ;
     RECT  9.468 6.539 39.294 6.583 ;
     RECT  41.58 6.235 41.598 6.683 ;
     RECT  7.815 6.583 39.294 6.845 ;
     RECT  7.815 6.845 35.19 7.231 ;
     RECT  40.215 6.539 40.497 7.393 ;
     RECT  42.156 6.763 42.174 7.421 ;
     RECT  7.596 7.231 35.19 7.465 ;
     RECT  36.072 6.845 38.97 7.723 ;
     RECT  39.888 7.393 40.497 7.723 ;
     RECT  7.488 7.465 35.19 7.771 ;
     RECT  36.072 7.723 40.497 7.771 ;
     RECT  7.488 7.771 40.497 8.159 ;
     RECT  7.488 8.159 36.414 8.429 ;
     RECT  41.58 7.819 41.598 8.501 ;
     RECT  7.488 8.429 36.342 8.699 ;
     RECT  7.488 8.699 36.306 8.771 ;
     RECT  37.404 8.159 40.497 9.077 ;
     RECT  7.488 8.771 36.27 9.085 ;
     RECT  37.404 9.077 39.006 9.085 ;
     RECT  39.78 9.077 40.497 9.113 ;
     RECT  41.832 8.875 41.85 9.113 ;
     RECT  37.188 9.085 39.006 9.239 ;
     RECT  37.188 9.239 38.646 9.319 ;
     RECT  41.58 9.403 41.598 9.653 ;
     RECT  37.116 9.319 38.646 9.661 ;
     RECT  39.852 9.113 40.497 9.895 ;
     RECT  39.672 9.895 41.058 9.965 ;
     RECT  37.044 9.661 38.646 10.021 ;
     RECT  39.672 9.965 40.59 10.021 ;
     RECT  37.044 10.021 40.59 10.049 ;
     RECT  7.056 9.085 36.27 10.201 ;
     RECT  37.044 10.049 40.497 10.201 ;
     RECT  42.156 10.459 42.174 10.661 ;
     RECT  7.056 10.201 40.497 10.859 ;
     RECT  8.82 10.859 40.497 10.987 ;
     RECT  8.82 10.987 41.022 11.273 ;
     RECT  8.82 11.273 40.497 11.669 ;
     RECT  41.58 11.515 41.598 11.741 ;
     RECT  7.056 10.859 8.097 11.749 ;
     RECT  8.82 11.669 36.414 11.749 ;
     RECT  7.056 11.749 36.414 12.451 ;
     RECT  7.056 12.451 36.486 12.595 ;
     RECT  37.515 11.669 40.497 12.595 ;
     RECT  42.156 12.043 42.174 12.605 ;
     RECT  7.056 12.595 40.497 13.199 ;
     RECT  7.056 13.199 36.486 13.289 ;
     RECT  7.056 13.289 14.67 13.421 ;
     RECT  41.832 13.099 41.85 13.433 ;
     RECT  37.26 13.199 40.497 13.559 ;
     RECT  37.476 13.559 40.497 13.627 ;
     RECT  15.768 13.289 36.486 13.667 ;
     RECT  37.476 13.627 41.022 13.667 ;
     RECT  15.804 13.667 36.486 13.739 ;
     RECT  8.856 13.421 14.67 14.107 ;
     RECT  37.476 13.667 40.497 14.135 ;
     RECT  41.832 14.155 41.85 14.243 ;
     RECT  7.056 13.421 8.097 14.251 ;
     RECT  8.856 14.107 14.778 14.251 ;
     RECT  7.056 14.251 14.778 14.485 ;
     RECT  15.804 13.739 36.45 14.485 ;
     RECT  7.056 14.485 36.45 14.791 ;
     RECT  7.056 14.791 36.522 14.953 ;
     RECT  37.515 14.135 38.682 15.061 ;
     RECT  39.564 14.135 40.497 15.061 ;
     RECT  42.156 14.683 42.174 15.251 ;
     RECT  7.056 14.953 36.594 15.295 ;
     RECT  37.515 15.061 40.497 15.295 ;
     RECT  7.056 15.295 40.497 15.521 ;
     RECT  39.564 15.521 40.497 15.601 ;
     RECT  7.056 15.521 38.538 16.259 ;
     RECT  39.564 15.601 40.554 16.411 ;
     RECT  22.824 16.259 38.538 16.501 ;
     RECT  39.564 16.411 40.734 16.501 ;
     RECT  7.056 16.259 22.05 16.529 ;
     RECT  22.824 16.501 40.734 16.529 ;
     RECT  7.056 16.529 20.466 16.565 ;
     RECT  42.156 16.267 42.174 16.601 ;
     RECT  22.824 16.529 40.554 16.709 ;
     RECT  7.056 16.565 19.386 16.907 ;
     RECT  22.824 16.709 40.497 16.907 ;
     RECT  20.124 16.565 20.466 16.943 ;
     RECT  21.204 16.529 22.05 17.077 ;
     RECT  22.824 16.907 39.114 17.077 ;
     RECT  41.58 16.795 41.598 17.411 ;
     RECT  21.204 17.077 39.114 17.761 ;
     RECT  39.924 16.907 40.497 17.761 ;
     RECT  20.34 16.943 20.466 18.031 ;
     RECT  20.16 18.031 20.466 18.157 ;
     RECT  21.204 17.761 40.497 18.157 ;
     RECT  7.056 16.907 19.314 18.185 ;
     RECT  8.964 18.185 19.314 18.193 ;
     RECT  20.16 18.157 40.497 18.193 ;
     RECT  8.964 18.193 40.497 18.221 ;
     RECT  8.964 18.221 38.61 18.527 ;
     RECT  41.832 17.851 41.85 18.563 ;
     RECT  12.312 18.527 38.61 19.003 ;
     RECT  39.384 18.221 40.497 19.003 ;
     RECT  41.58 18.907 41.598 19.031 ;
     RECT  7.056 18.185 8.097 19.111 ;
     RECT  8.964 18.527 11.538 19.381 ;
     RECT  12.312 19.003 40.497 19.381 ;
     RECT  8.964 19.381 40.497 19.535 ;
     RECT  7.056 19.111 8.226 19.615 ;
     RECT  8.964 19.535 39.114 19.615 ;
     RECT  40.104 19.535 40.497 19.805 ;
     RECT  7.056 19.615 39.114 19.877 ;
     RECT  7.056 19.877 25.362 20.309 ;
     RECT  42.156 19.435 42.174 20.381 ;
     RECT  41.58 20.491 41.85 20.723 ;
     RECT  40.215 19.805 40.497 20.731 ;
     RECT  26.136 19.877 39.114 21.001 ;
     RECT  40.176 20.731 40.497 21.001 ;
     RECT  7.056 20.309 25.182 21.127 ;
     RECT  26.136 21.001 40.497 21.127 ;
     RECT  41.832 20.723 41.85 21.263 ;
     RECT  7.056 21.127 40.497 21.271 ;
     RECT  7.056 21.271 40.734 21.389 ;
     RECT  7.056 21.389 40.497 21.695 ;
     RECT  42.156 21.547 42.174 21.731 ;
     RECT  7.056 21.695 39.366 21.965 ;
     RECT  41.58 22.075 41.598 22.235 ;
     RECT  42.156 22.603 42.174 22.811 ;
     RECT  7.056 21.965 38.754 22.891 ;
     RECT  7.056 22.891 39.438 22.939 ;
     RECT  6.912 22.939 39.438 23.009 ;
     RECT  7.488 23.009 39.438 23.161 ;
     RECT  40.215 21.695 40.497 23.161 ;
     RECT  7.488 23.161 40.497 24.379 ;
     RECT  7.308 24.379 40.497 24.431 ;
     RECT  41.58 23.131 41.598 25.043 ;
     RECT  7.416 24.431 40.497 25.051 ;
     RECT  42.156 25.243 42.174 25.817 ;
     RECT  7.416 25.051 40.554 25.861 ;
     RECT  7.416 25.861 40.914 26.299 ;
     RECT  7.416 26.299 41.022 26.393 ;
     RECT  7.416 26.393 40.734 26.627 ;
     RECT  7.524 26.627 40.734 27.059 ;
     RECT  7.524 27.059 40.554 27.389 ;
     RECT  42.156 26.797 42.174 27.389 ;
     RECT  7.815 27.389 40.554 27.671 ;
     RECT  7.815 27.671 40.497 28.381 ;
     RECT  41.58 27.883 41.598 28.481 ;
     RECT  42.156 28.939 42.174 29.021 ;
     RECT  41.58 29.467 41.598 29.633 ;
     RECT  7.56 28.381 40.497 29.641 ;
     RECT  7.308 29.641 40.497 29.755 ;
     RECT  7.272 29.755 40.497 30.065 ;
     RECT  7.776 30.065 40.497 30.209 ;
     RECT  42.156 29.995 42.174 31.051 ;
     RECT  7.815 30.209 40.497 31.685 ;
     RECT  41.832 31.051 42.174 31.721 ;
     RECT  12.816 31.685 40.497 31.793 ;
     RECT  7.815 31.685 11.97 31.891 ;
     RECT  7.776 31.891 11.97 32.305 ;
     RECT  41.58 32.107 41.598 32.369 ;
     RECT  7.74 32.305 11.97 32.443 ;
     RECT  7.164 32.443 11.97 32.467 ;
     RECT  6.732 32.467 11.97 32.495 ;
     RECT  12.96 31.793 40.497 32.611 ;
     RECT  12.888 32.611 40.497 32.737 ;
     RECT  6.732 32.495 6.75 32.765 ;
     RECT  7.668 32.495 11.97 32.773 ;
     RECT  12.744 32.737 40.497 32.773 ;
     RECT  41.904 32.635 41.922 32.873 ;
     RECT  7.668 32.773 40.497 32.881 ;
     RECT  7.668 32.881 40.842 33.035 ;
     RECT  7.668 33.035 12.402 33.259 ;
     RECT  41.832 33.163 41.85 33.413 ;
     RECT  13.176 33.035 40.842 33.691 ;
     RECT  7.524 33.259 12.402 33.889 ;
     RECT  13.176 33.691 41.022 33.889 ;
     RECT  7.524 33.889 41.022 33.953 ;
     RECT  7.776 33.953 40.734 34.349 ;
     RECT  41.832 34.219 41.85 34.493 ;
     RECT  7.776 34.349 40.626 34.771 ;
     RECT  42.192 34.747 42.21 35.033 ;
     RECT  6.912 35.041 6.93 35.311 ;
     RECT  7.668 34.771 40.626 35.311 ;
     RECT  43.02 35.275 43.038 35.501 ;
     RECT  6.912 35.311 40.626 35.699 ;
     RECT  7.704 35.699 40.626 35.851 ;
     RECT  6.804 35.845 6.822 35.885 ;
     RECT  7.704 35.851 40.734 36.121 ;
     RECT  7.704 36.121 40.806 36.239 ;
     RECT  7.704 36.239 40.554 36.481 ;
     RECT  7.236 36.481 40.554 36.763 ;
     RECT  42.156 35.803 42.174 36.851 ;
     RECT  6.696 36.763 40.554 37.165 ;
     RECT  6.696 37.165 40.626 37.625 ;
     RECT  6.696 37.625 6.966 37.859 ;
     RECT  7.74 37.625 40.626 37.859 ;
     RECT  43.092 38.347 43.11 38.477 ;
     RECT  7.815 37.859 40.626 38.641 ;
     RECT  7.704 38.641 40.626 39.091 ;
     RECT  7.704 39.091 40.698 39.217 ;
     RECT  7.38 39.217 40.698 39.289 ;
     RECT  6.84 39.289 40.698 39.325 ;
     RECT  42.192 39.019 42.21 39.389 ;
     RECT  6.3 39.325 40.698 39.559 ;
     RECT  6.3 39.559 40.77 39.749 ;
     RECT  6.588 39.749 40.77 39.773 ;
     RECT  6.84 39.773 40.77 39.901 ;
     RECT  6.84 39.901 40.914 40.019 ;
     RECT  6.84 40.019 40.698 40.289 ;
     RECT  7.308 40.289 40.698 40.325 ;
     RECT  7.308 40.325 40.626 41.251 ;
     RECT  7.092 41.251 40.626 41.371 ;
     RECT  7.092 41.371 41.022 41.513 ;
     RECT  7.092 41.513 40.626 41.755 ;
     RECT  6.516 41.755 40.626 42.053 ;
     RECT  41.58 41.899 41.598 42.593 ;
     RECT  41.832 42.955 41.85 43.133 ;
     RECT  7.164 42.053 40.626 43.295 ;
     RECT  7.38 43.295 40.626 43.303 ;
     RECT  41.904 43.483 41.922 43.673 ;
     RECT  7.38 43.303 40.698 43.853 ;
     RECT  7.524 43.853 40.698 43.949 ;
     RECT  7.524 43.949 24.858 44.069 ;
     RECT  41.58 44.011 41.598 44.141 ;
     RECT  7.668 44.069 24.858 44.851 ;
     RECT  25.596 43.949 40.698 44.851 ;
     RECT  42.156 44.539 42.174 44.951 ;
     RECT  41.616 45.067 41.634 45.293 ;
     RECT  7.668 44.851 40.698 45.301 ;
     RECT  7.488 45.301 40.698 45.691 ;
     RECT  6.948 45.691 40.698 45.731 ;
     RECT  7.524 45.731 40.698 45.797 ;
     RECT  41.58 45.595 41.598 45.833 ;
     RECT  17.244 45.797 40.698 45.995 ;
     RECT  41.616 46.075 41.634 46.157 ;
     RECT  7.668 45.797 16.47 46.651 ;
     RECT  41.58 46.615 41.598 46.685 ;
     RECT  7.668 46.651 16.65 46.849 ;
     RECT  7.416 46.849 16.65 46.921 ;
     RECT  17.496 45.995 40.698 46.921 ;
     RECT  7.38 46.921 40.698 46.987 ;
     RECT  7.02 46.987 40.698 47.039 ;
     RECT  7.38 47.039 40.698 47.345 ;
     RECT  7.668 47.345 40.698 47.579 ;
     RECT  7.668 47.579 40.662 48.199 ;
     RECT  7.596 48.199 40.662 48.271 ;
     RECT  42.156 47.179 42.174 48.461 ;
     RECT  7.38 48.271 40.662 48.619 ;
     RECT  7.02 48.619 40.662 48.659 ;
     RECT  41.58 48.763 41.598 48.803 ;
     RECT  42.156 49.279 42.174 49.325 ;
     RECT  6.876 49.855 6.894 49.901 ;
     RECT  7.668 48.659 40.662 50.053 ;
     RECT  41.58 49.819 41.598 50.423 ;
     RECT  7.416 50.053 40.662 50.779 ;
     RECT  41.832 50.875 41.85 50.963 ;
     RECT  6.84 50.779 40.662 51.089 ;
     RECT  6.84 51.089 40.626 51.269 ;
     RECT  41.58 51.403 41.598 51.44 ;
     RECT  6.84 51.269 24.678 51.475 ;
     RECT  41.904 51.931 41.922 52.043 ;
     RECT  6.624 51.475 24.678 52.321 ;
     RECT  25.596 51.269 40.626 52.321 ;
     RECT  41.58 52.459 41.598 52.511 ;
     RECT  6.624 52.321 40.626 54.125 ;
     RECT  7.668 54.125 40.626 54.329 ;
     RECT  42.156 52.987 42.174 55.211 ;
     RECT  43.092 55.627 43.11 55.757 ;
     RECT  7.668 54.329 40.554 55.795 ;
     RECT  7.488 55.795 40.554 56.101 ;
     RECT  7.488 56.101 40.914 56.219 ;
     RECT  42.156 56.155 42.174 56.291 ;
     RECT  7.488 56.219 40.554 56.489 ;
     RECT  6.624 54.125 6.642 56.491 ;
     RECT  7.488 56.489 40.497 56.491 ;
     RECT  6.624 56.491 40.497 56.795 ;
     RECT  41.58 56.683 41.598 56.903 ;
     RECT  41.832 57.211 41.85 57.443 ;
     RECT  7.488 56.795 40.497 57.739 ;
     RECT  6.624 56.795 6.642 57.835 ;
     RECT  7.488 57.739 41.022 57.983 ;
     RECT  6.48 57.835 6.642 57.991 ;
     RECT  7.488 57.983 40.914 57.991 ;
     RECT  6.48 57.991 40.914 58.109 ;
     RECT  6.516 58.109 40.914 58.145 ;
     RECT  7.416 58.145 40.914 58.379 ;
     RECT  42.156 58.267 42.174 58.451 ;
     RECT  7.416 58.379 40.626 58.793 ;
     RECT  7.632 58.793 40.626 58.955 ;
     RECT  7.668 58.955 40.626 59.189 ;
     RECT  43.02 59.323 43.038 59.801 ;
     RECT  7.668 59.189 40.497 59.947 ;
     RECT  41.58 58.795 41.598 60.071 ;
     RECT  7.452 59.947 40.497 60.269 ;
     RECT  7.668 60.269 40.497 60.889 ;
     RECT  7.668 60.889 40.734 61.079 ;
     RECT  7.668 61.079 40.497 61.099 ;
     RECT  41.832 60.379 41.85 61.763 ;
     RECT  7.344 61.099 40.497 61.969 ;
     RECT  43.092 61.963 43.11 62.231 ;
     RECT  42.156 62.491 42.174 62.537 ;
     RECT  41.904 63.019 41.922 63.113 ;
     RECT  7.308 61.969 40.497 63.509 ;
     RECT  41.58 63.544 41.598 63.581 ;
     RECT  7.56 63.509 40.497 63.661 ;
     RECT  7.56 63.661 40.59 63.851 ;
     RECT  42.156 64.075 42.174 64.121 ;
     RECT  7.56 63.851 40.497 64.741 ;
     RECT  7.308 64.741 40.497 64.895 ;
     RECT  27.972 64.895 40.497 65.281 ;
     RECT  6.516 58.145 6.534 65.435 ;
     RECT  7.308 64.895 26.997 65.515 ;
     RECT  5.115 2.413 5.397 65.551 ;
     RECT  27.972 65.281 40.626 65.551 ;
     RECT  7.128 65.515 26.997 65.821 ;
     RECT  27.972 65.551 40.734 65.821 ;
     RECT  41.58 64.603 41.598 66.083 ;
     RECT  7.128 65.821 40.734 66.187 ;
     RECT  7.128 66.187 41.022 66.281 ;
     RECT  7.128 66.281 40.554 66.353 ;
     RECT  7.128 66.353 40.497 66.551 ;
     RECT  7.128 66.551 39.006 66.749 ;
     RECT  42.156 66.715 42.174 66.821 ;
     RECT  41.832 67.243 41.85 67.433 ;
     RECT  40.215 66.551 40.497 67.441 ;
     RECT  7.236 66.749 39.006 67.711 ;
     RECT  6.948 67.711 39.006 67.801 ;
     RECT  39.744 67.441 40.497 67.801 ;
     RECT  41.58 67.771 41.598 67.901 ;
     RECT  6.948 67.801 40.497 68.299 ;
     RECT  6.948 68.299 41.022 68.369 ;
     RECT  40.176 68.369 41.022 68.405 ;
     RECT  6.948 68.369 39.438 68.521 ;
     RECT  5.115 65.551 6.066 68.755 ;
     RECT  6.912 68.521 39.438 68.755 ;
     RECT  41.58 68.827 41.598 68.981 ;
     RECT  5.115 68.755 39.438 69.421 ;
     RECT  40.176 68.405 40.497 69.421 ;
     RECT  5.115 69.421 40.497 69.449 ;
     RECT  5.115 69.449 28.134 69.485 ;
     RECT  28.944 69.449 40.497 69.791 ;
     RECT  28.944 69.791 39.402 70.231 ;
     RECT  5.115 69.485 28.062 70.267 ;
     RECT  42.156 69.355 42.174 70.601 ;
     RECT  5.115 70.267 28.098 70.645 ;
     RECT  28.836 70.231 39.402 70.645 ;
     RECT  5.115 70.645 39.402 70.681 ;
     RECT  40.215 69.791 40.497 70.681 ;
     RECT  5.115 70.681 40.497 70.907 ;
     RECT  5.115 70.907 39.042 71.069 ;
     RECT  41.58 70.939 41.598 71.467 ;
     RECT  41.58 71.467 41.85 71.753 ;
     RECT  39.78 70.907 40.497 71.761 ;
     RECT  5.115 71.069 39.006 72.121 ;
     RECT  39.744 71.761 40.497 72.121 ;
     RECT  41.58 71.753 41.598 72.293 ;
     RECT  5.115 72.121 40.497 72.461 ;
     RECT  6.3 72.461 40.497 72.523 ;
     RECT  6.3 72.523 41.022 72.761 ;
     RECT  6.3 72.761 40.662 72.833 ;
     RECT  6.3 72.833 39.006 72.959 ;
     RECT  6.3 72.959 38.934 73.309 ;
     RECT  5.115 72.461 5.397 73.381 ;
     RECT  6.264 73.309 38.934 73.381 ;
     RECT  5.115 73.381 38.934 73.409 ;
     RECT  39.78 72.833 40.662 73.535 ;
     RECT  5.115 73.409 38.862 73.769 ;
     RECT  5.115 73.769 31.194 73.805 ;
     RECT  31.932 73.769 38.862 74.039 ;
     RECT  40.068 73.535 40.662 74.107 ;
     RECT  41.58 73.051 41.598 74.107 ;
     RECT  40.068 74.107 41.598 74.111 ;
     RECT  40.068 74.111 41.022 74.345 ;
     RECT  40.215 74.345 41.022 74.453 ;
     RECT  39.42 74.461 39.438 74.651 ;
     RECT  5.115 73.805 14.598 74.659 ;
     RECT  15.408 73.805 31.158 74.731 ;
     RECT  31.932 74.039 38.394 74.731 ;
     RECT  15.408 74.731 38.394 74.849 ;
     RECT  15.408 74.849 38.286 74.885 ;
     RECT  5.115 74.659 14.67 75.001 ;
     RECT  15.408 74.885 37.797 75.001 ;
     RECT  5.115 75.001 37.797 75.119 ;
     RECT  5.115 75.119 24.297 75.155 ;
     RECT  33.372 75.119 37.797 75.155 ;
     RECT  33.372 75.155 33.606 75.191 ;
     RECT  25.524 75.119 29.697 75.227 ;
     RECT  18.615 75.155 24.297 75.245 ;
     RECT  2.415 2.413 2.697 75.347 ;
     RECT  5.115 75.155 16.197 75.347 ;
     RECT  22.716 75.245 24.297 75.347 ;
     RECT  28.872 75.227 29.697 75.347 ;
     RECT  30.708 75.119 32.397 75.347 ;
     RECT  34.416 75.155 37.797 75.347 ;
     RECT  40.215 74.453 40.497 75.347 ;
     RECT  5.115 75.347 16.005 75.389 ;
     RECT  17.46 75.155 17.694 75.389 ;
     RECT  18.615 75.245 21.654 75.389 ;
     RECT  22.716 75.347 24.105 75.389 ;
     RECT  25.524 75.227 27.81 75.389 ;
     RECT  30.708 75.347 32.205 75.389 ;
     RECT  33.588 75.191 33.606 75.389 ;
     RECT  34.416 75.347 37.605 75.389 ;
     RECT  13.215 75.389 16.005 75.425 ;
     RECT  17.46 75.389 17.478 75.425 ;
     RECT  19.8 75.389 19.818 75.425 ;
     RECT  22.716 75.389 22.734 75.425 ;
     RECT  25.524 75.389 25.542 75.425 ;
     RECT  30.708 75.389 30.726 75.425 ;
     RECT  35.928 75.389 35.946 75.425 ;
     RECT  6.12 75.389 11.394 75.461 ;
     RECT  32.04 75.389 32.205 75.461 ;
     RECT  28.872 75.347 29.505 75.497 ;
     RECT  21.168 75.389 21.654 75.569 ;
     RECT  2.415 75.347 2.505 75.617 ;
     RECT  5.115 75.389 5.205 75.617 ;
     RECT  13.215 75.425 14.598 75.617 ;
     RECT  15.915 75.425 16.005 75.617 ;
     RECT  18.615 75.389 18.705 75.617 ;
     RECT  21.315 75.569 21.654 75.617 ;
     RECT  24.015 75.389 24.105 75.617 ;
     RECT  26.715 75.389 26.805 75.617 ;
     RECT  29.415 75.497 29.505 75.617 ;
     RECT  32.115 75.461 32.205 75.617 ;
     RECT  34.815 75.389 34.905 75.617 ;
     RECT  37.515 75.389 37.605 75.617 ;
     RECT  40.215 75.347 40.305 75.617 ;
     RECT  21.636 75.617 21.654 75.773 ;
     RECT  6.12 75.461 9.666 75.821 ;
     RECT  10.476 75.461 11.394 75.821 ;
     RECT  6.12 75.821 9.522 75.917 ;
     RECT  6.12 75.917 7.218 76.397 ;
     RECT  6.12 76.397 7.146 76.973 ;
     RECT  7.956 75.917 9.522 76.973 ;
     RECT  10.476 75.821 10.854 76.973 ;
     RECT  6.264 76.973 7.146 77.021 ;
     RECT  6.264 77.021 6.282 77.069 ;
     RECT  12.24 75.389 12.474 77.323 ;
     RECT  12.24 77.323 12.618 77.453 ;
     RECT  13.716 75.617 14.598 77.453 ;
     RECT  12.24 77.453 12.546 77.549 ;
     RECT  13.716 77.453 14.31 77.549 ;
     RECT  10.836 76.973 10.854 77.597 ;
     RECT  12.24 77.549 12.474 77.597 ;
     RECT  14.004 77.549 14.31 77.597 ;
     RECT  7.128 77.021 7.146 77.645 ;
     RECT  7.956 76.973 9.054 77.645 ;
     RECT  12.24 77.597 12.366 77.645 ;
     RECT  14.292 77.597 14.31 77.645 ;
    LAYER M4 ;
     RECT  2.408 2.148 2.512 75.612 ;
     RECT  2.512 2.418 2.704 75.342 ;
     RECT  5.108 2.148 5.212 75.612 ;
     RECT  5.212 2.418 5.404 75.342 ;
     RECT  6.109 76.944 6.253 76.968 ;
     RECT  5.404 75.264 6.563 75.288 ;
     RECT  6.685 36.768 6.764 36.792 ;
     RECT  6.764 35.856 6.805 36.792 ;
     RECT  6.829 50.784 6.853 50.808 ;
     RECT  6.792 52.032 6.853 52.056 ;
     RECT  5.404 69.552 6.949 69.576 ;
     RECT  6.577 75.792 6.973 75.864 ;
     RECT  6.253 76.944 6.973 77.064 ;
     RECT  6.937 45.696 7.045 45.72 ;
     RECT  6.853 48.624 7.045 52.056 ;
     RECT  6.973 75.792 7.073 77.064 ;
     RECT  6.949 69.456 7.189 69.576 ;
     RECT  6.901 24.384 7.381 24.408 ;
     RECT  6.469 57.84 7.388 57.864 ;
     RECT  7.388 57.84 7.405 58.152 ;
     RECT  7.153 32.448 7.429 32.472 ;
     RECT  7.045 54.096 7.429 54.12 ;
     RECT  7.153 56.496 7.436 56.52 ;
     RECT  7.189 69.456 7.436 70.056 ;
     RECT  7.436 55.824 7.477 56.52 ;
     RECT  7.405 57.84 7.477 58.632 ;
     RECT  7.436 59.952 7.477 59.976 ;
     RECT  7.333 61.104 7.477 61.128 ;
     RECT  6.937 74.688 7.573 74.712 ;
     RECT  7.073 75.792 7.573 77.64 ;
     RECT  7.477 66.72 7.585 66.744 ;
     RECT  7.477 67.824 7.585 67.848 ;
     RECT  7.285 73.536 7.621 73.56 ;
     RECT  7.573 74.688 7.621 77.64 ;
     RECT  6.805 35.328 7.657 36.792 ;
     RECT  7.261 29.76 7.669 29.784 ;
     RECT  7.429 31.2 7.669 31.224 ;
     RECT  6.901 21.504 7.808 21.528 ;
     RECT  6.86 22.944 7.808 22.968 ;
     RECT  7.381 24.384 7.808 25.176 ;
     RECT  7.513 27.36 7.808 27.384 ;
     RECT  7.669 29.76 7.808 31.224 ;
     RECT  7.429 32.448 7.808 33.288 ;
     RECT  7.657 35.328 7.808 37.08 ;
     RECT  6.577 39.744 7.808 39.768 ;
     RECT  7.153 42.72 7.808 42.744 ;
     RECT  7.34 43.824 7.808 43.848 ;
     RECT  7.045 44.976 7.808 45.72 ;
     RECT  7.004 46.992 7.808 47.016 ;
     RECT  7.045 48.24 7.808 52.056 ;
     RECT  7.429 53.616 7.808 54.12 ;
     RECT  7.477 55.824 7.808 59.976 ;
     RECT  7.477 61.104 7.808 61.224 ;
     RECT  7.585 66.72 7.808 67.848 ;
     RECT  7.436 68.88 7.808 70.056 ;
     RECT  5.404 71.328 7.808 72.456 ;
     RECT  7.621 73.536 7.808 77.64 ;
     RECT  7.808 2.148 7.912 77.64 ;
     RECT  7.912 2.418 8.104 77.64 ;
     RECT  8.104 27.36 8.129 30.888 ;
     RECT  8.104 45.168 8.237 45.576 ;
     RECT  8.104 58.656 8.237 59.304 ;
     RECT  8.104 47.088 8.273 48.264 ;
     RECT  8.129 27.6 8.339 30.888 ;
     RECT  8.339 27.6 8.38 30.408 ;
     RECT  8.104 74.112 8.381 77.64 ;
     RECT  8.104 49.488 8.417 52.488 ;
     RECT  8.104 61.104 8.453 61.128 ;
     RECT  8.381 74.112 8.453 76.392 ;
     RECT  8.273 47.952 8.489 48.264 ;
     RECT  8.104 34.656 8.561 39.768 ;
     RECT  8.104 24.624 8.579 24.648 ;
     RECT  8.104 25.68 8.597 25.704 ;
     RECT  8.561 35.904 8.597 39.768 ;
     RECT  8.597 35.904 8.62 36.12 ;
     RECT  8.417 49.488 8.633 49.512 ;
     RECT  8.104 64.416 8.64 67.992 ;
     RECT  8.104 40.752 8.669 41.256 ;
     RECT  8.38 29.664 8.705 30.408 ;
     RECT  8.64 67.008 8.705 67.992 ;
     RECT  8.104 53.616 8.741 54.168 ;
     RECT  8.104 21.216 8.777 21.912 ;
     RECT  8.104 10.08 9.097 10.152 ;
     RECT  8.104 42.528 9.097 42.792 ;
     RECT  8.104 33.024 9.109 33.48 ;
     RECT  8.561 34.656 9.109 34.92 ;
     RECT  8.104 15.984 9.133 16.104 ;
     RECT  8.705 67.056 9.137 67.992 ;
     RECT  9.097 9.84 9.169 10.152 ;
     RECT  9.133 15.984 9.169 16.248 ;
     RECT  8.669 40.752 9.173 40.776 ;
     RECT  8.489 47.952 9.173 47.976 ;
     RECT  8.237 59.28 9.173 59.304 ;
     RECT  8.104 12.288 9.205 12.312 ;
     RECT  8.104 13.392 9.205 14.424 ;
     RECT  9.169 15.792 9.205 16.248 ;
     RECT  9.097 41.904 9.205 42.792 ;
     RECT  8.104 71.232 9.205 72.936 ;
     RECT  8.453 74.112 9.205 75.816 ;
     RECT  8.417 50.832 9.209 52.488 ;
     RECT  8.104 7.392 9.212 7.416 ;
     RECT  8.237 45.552 9.241 45.576 ;
     RECT  8.104 18 9.301 18.024 ;
     RECT  8.104 31.92 9.313 31.944 ;
     RECT  8.38 27.6 9.317 28.44 ;
     RECT  9.205 11.952 9.353 14.424 ;
     RECT  8.104 69.216 9.385 70.008 ;
     RECT  9.137 67.152 9.389 67.752 ;
     RECT  8.104 20.016 9.421 20.04 ;
     RECT  8.777 21.216 9.421 21.24 ;
     RECT  9.385 68.736 9.421 70.008 ;
     RECT  9.205 71.232 9.421 75.816 ;
     RECT  9.421 68.736 9.443 75.816 ;
     RECT  9.301 18 9.445 18.792 ;
     RECT  9.241 45.552 9.457 45.816 ;
     RECT  9.353 13.488 9.493 14.424 ;
     RECT  9.205 15.456 9.493 16.248 ;
     RECT  8.381 77.424 9.493 77.64 ;
     RECT  9.493 13.488 9.497 16.248 ;
     RECT  8.104 55.296 9.533 57.192 ;
     RECT  9.109 33.024 9.541 34.92 ;
     RECT  8.62 35.904 9.541 35.928 ;
     RECT  9.443 68.736 9.541 73.56 ;
     RECT  9.445 17.664 9.601 18.792 ;
     RECT  8.104 22.992 9.601 23.112 ;
     RECT  8.64 64.416 9.601 65.496 ;
     RECT  8.741 53.616 9.637 53.64 ;
     RECT  9.565 5.28 9.709 5.304 ;
     RECT  9.212 7.392 9.709 7.992 ;
     RECT  9.169 9.696 9.709 10.488 ;
     RECT  9.313 31.776 9.709 31.944 ;
     RECT  9.457 44.928 9.709 45.816 ;
     RECT  9.497 13.584 9.781 16.248 ;
     RECT  9.601 17.664 9.781 18.984 ;
     RECT  9.421 20.016 9.781 21.24 ;
     RECT  9.205 41.904 9.781 43.368 ;
     RECT  9.709 44.928 9.781 47.352 ;
     RECT  9.709 9.696 9.889 10.632 ;
     RECT  9.541 33.024 9.889 35.928 ;
     RECT  8.597 37.296 9.889 39.768 ;
     RECT  8.705 30.144 9.925 30.408 ;
     RECT  9.781 41.904 9.98 47.352 ;
     RECT  9.097 61.968 9.997 62.76 ;
     RECT  9.889 9.552 10.069 10.632 ;
     RECT  9.353 11.952 10.069 12.312 ;
     RECT  9.961 26.304 10.105 26.328 ;
     RECT  9.443 74.64 10.117 75.816 ;
     RECT  9.493 76.944 10.117 77.64 ;
     RECT  9.925 30.144 10.141 30.792 ;
     RECT  9.709 31.776 10.141 32.04 ;
     RECT  9.889 33.024 10.177 39.768 ;
     RECT  9.853 49.824 10.177 49.848 ;
     RECT  9.209 50.832 10.177 51.528 ;
     RECT  9.889 3.888 10.213 3.912 ;
     RECT  10.069 9.552 10.249 12.312 ;
     RECT  9.601 63.744 10.249 65.496 ;
     RECT  9.709 7.344 10.261 7.992 ;
     RECT  9.709 5.232 10.285 5.928 ;
     RECT  9.601 22.896 10.285 23.112 ;
     RECT  9.98 41.568 10.285 47.352 ;
     RECT  9.997 61.728 10.285 62.76 ;
     RECT  10.285 5.232 10.357 6.024 ;
     RECT  10.261 7.104 10.357 7.992 ;
     RECT  10.249 63.744 10.357 65.544 ;
     RECT  9.389 67.152 10.357 67.56 ;
     RECT  10.213 3.408 10.393 3.912 ;
     RECT  10.357 63.744 10.429 67.56 ;
     RECT  10.429 63.744 10.465 67.752 ;
     RECT  9.541 68.736 10.465 73.368 ;
     RECT  10.393 3.408 10.508 3.96 ;
     RECT  10.357 5.232 10.508 7.992 ;
     RECT  10.249 9.12 10.508 12.312 ;
     RECT  9.781 13.584 10.508 16.632 ;
     RECT  9.781 17.664 10.508 21.24 ;
     RECT  10.285 22.8 10.508 23.112 ;
     RECT  10.309 24.48 10.508 24.504 ;
     RECT  10.105 26.256 10.508 26.328 ;
     RECT  9.317 27.6 10.508 27.624 ;
     RECT  9.781 28.896 10.508 29.016 ;
     RECT  10.141 30.144 10.508 32.04 ;
     RECT  10.177 33.024 10.508 39.816 ;
     RECT  10.285 41.568 10.508 47.88 ;
     RECT  10.177 49.824 10.508 51.528 ;
     RECT  9.637 52.704 10.508 53.64 ;
     RECT  9.533 55.536 10.508 57.192 ;
     RECT  10.357 58.656 10.508 58.68 ;
     RECT  9.745 59.856 10.508 59.88 ;
     RECT  10.285 60.864 10.508 62.76 ;
     RECT  10.465 63.744 10.508 73.368 ;
     RECT  10.117 74.64 10.508 77.64 ;
     RECT  10.508 2.148 10.612 77.64 ;
     RECT  10.612 2.418 10.804 77.64 ;
     RECT  10.804 63.792 10.829 66.648 ;
     RECT  10.804 19.824 10.865 21.24 ;
     RECT  10.804 26.208 10.865 26.328 ;
     RECT  10.804 39.792 10.865 42.792 ;
     RECT  10.865 19.824 10.901 20.952 ;
     RECT  10.804 58.128 10.901 61.992 ;
     RECT  10.804 22.8 10.931 22.824 ;
     RECT  10.804 7.68 10.937 7.944 ;
     RECT  10.804 47.328 10.945 54.504 ;
     RECT  10.804 3.408 10.973 3.96 ;
     RECT  10.901 19.824 10.973 19.944 ;
     RECT  10.804 12.528 10.979 15.816 ;
     RECT  10.804 9.504 11.009 11.4 ;
     RECT  10.804 27.6 11.009 33.384 ;
     RECT  10.804 44.064 11.117 46.296 ;
     RECT  10.804 68.208 11.117 77.64 ;
     RECT  10.804 5.184 11.123 6.696 ;
     RECT  10.804 16.848 11.123 18.84 ;
     RECT  10.865 26.208 11.153 26.232 ;
     RECT  10.804 36 11.153 38.52 ;
     RECT  10.945 47.328 11.225 54.168 ;
     RECT  11.153 36 11.261 38.472 ;
     RECT  11.123 5.184 11.297 6.072 ;
     RECT  10.973 3.936 11.369 3.96 ;
     RECT  11.009 31.152 11.369 33.384 ;
     RECT  10.829 64.608 11.369 65.544 ;
     RECT  11.123 16.848 11.441 18.744 ;
     RECT  10.865 39.84 11.441 42.792 ;
     RECT  11.117 68.976 11.449 77.64 ;
     RECT  11.009 9.504 11.513 9.864 ;
     RECT  11.261 36 11.513 37.752 ;
     RECT  10.979 15.408 11.585 15.816 ;
     RECT  11.225 47.328 11.621 51.768 ;
     RECT  10.973 19.92 11.657 19.944 ;
     RECT  10.901 58.128 11.657 60.6 ;
     RECT  11.441 16.848 11.729 18.264 ;
     RECT  11.621 50.304 11.765 51.768 ;
     RECT  11.117 44.064 11.797 44.712 ;
     RECT  10.979 12.528 11.801 13.656 ;
     RECT  11.441 39.84 11.801 42.024 ;
     RECT  11.513 9.504 11.837 9.72 ;
     RECT  10.901 61.728 11.869 61.992 ;
     RECT  11.369 65.232 11.873 65.544 ;
     RECT  11.585 15.792 11.9 15.816 ;
     RECT  11.729 16.848 11.9 18.12 ;
     RECT  11.657 58.128 11.909 59.88 ;
     RECT  11.297 5.184 11.941 5.688 ;
     RECT  11.117 45.792 11.941 46.296 ;
     RECT  11.621 47.328 11.941 49.08 ;
     RECT  11.9 15.792 11.987 18.12 ;
     RECT  11.225 52.752 11.989 54.168 ;
     RECT  10.804 55.536 11.989 57.048 ;
     RECT  11.941 4.752 12.017 5.688 ;
     RECT  11.009 10.944 12.017 11.4 ;
     RECT  11.797 43.296 12.017 44.712 ;
     RECT  11.449 71.808 12.035 77.64 ;
     RECT  11.801 12.528 12.053 13.08 ;
     RECT  11.987 15.792 12.053 15.816 ;
     RECT  11.987 16.944 12.089 18.12 ;
     RECT  11.989 52.752 12.089 57.048 ;
     RECT  12.017 43.344 12.121 44.712 ;
     RECT  11.941 45.792 12.121 49.08 ;
     RECT  12.089 55.056 12.125 57.048 ;
     RECT  12.017 11.376 12.131 11.4 ;
     RECT  12.089 17.568 12.131 18.12 ;
     RECT  12.121 43.344 12.161 49.08 ;
     RECT  11.801 40.56 12.197 42.024 ;
     RECT  12.161 43.344 12.205 47.4 ;
     RECT  12.205 43.344 12.227 44.568 ;
     RECT  10.804 34.656 12.229 35.016 ;
     RECT  11.513 36 12.229 36.216 ;
     RECT  12.125 55.584 12.229 57.048 ;
     RECT  10.829 66.624 12.229 66.648 ;
     RECT  11.837 9.504 12.265 9.672 ;
     RECT  11.765 50.832 12.301 51.768 ;
     RECT  12.089 52.752 12.301 53.64 ;
     RECT  12.035 72.048 12.371 77.64 ;
     RECT  11.513 37.584 12.373 37.752 ;
     RECT  11.833 63.264 12.409 63.288 ;
     RECT  11.009 27.6 12.517 29.976 ;
     RECT  11.369 31.152 12.517 33.096 ;
     RECT  12.229 34.656 12.553 36.216 ;
     RECT  12.373 37.584 12.553 38.232 ;
     RECT  11.449 68.976 12.661 70.728 ;
     RECT  12.301 50.832 12.757 53.64 ;
     RECT  12.757 50.784 12.764 53.64 ;
     RECT  12.371 76.656 12.803 77.64 ;
     RECT  12.265 9.12 12.805 9.672 ;
     RECT  12.553 34.656 12.805 38.232 ;
     RECT  12.229 55.584 12.805 57.096 ;
     RECT  12.409 63.264 12.805 63.528 ;
     RECT  12.131 18.096 12.877 18.12 ;
     RECT  12.229 65.856 12.877 67.704 ;
     RECT  12.805 34.176 12.949 38.232 ;
     RECT  12.769 39.552 12.949 39.576 ;
     RECT  12.949 34.176 12.956 39.576 ;
     RECT  10.937 7.68 13.021 7.704 ;
     RECT  12.805 8.832 13.021 9.672 ;
     RECT  12.764 50.544 13.021 53.64 ;
     RECT  13.021 8.736 13.032 9.672 ;
     RECT  12.877 18.096 13.057 18.168 ;
     RECT  12.017 4.752 13.065 5.256 ;
     RECT  13.065 4.752 13.093 6.024 ;
     RECT  13.021 7.104 13.093 7.704 ;
     RECT  13.032 8.736 13.093 10.44 ;
     RECT  13.057 15.216 13.093 15.24 ;
     RECT  11.909 58.128 13.093 59.016 ;
     RECT  12.371 72.048 13.093 75.612 ;
     RECT  12.445 3.648 13.208 3.672 ;
     RECT  13.093 4.752 13.208 7.704 ;
     RECT  13.093 8.736 13.208 11.208 ;
     RECT  12.053 12.912 13.208 13.08 ;
     RECT  13.093 15.216 13.208 15.336 ;
     RECT  13.057 18.096 13.208 18.792 ;
     RECT  10.901 20.928 13.208 20.952 ;
     RECT  13.052 21.936 13.208 22.728 ;
     RECT  12.157 23.856 13.208 23.88 ;
     RECT  12.517 27.6 13.208 33.096 ;
     RECT  12.956 34.176 13.208 39.672 ;
     RECT  12.197 40.944 13.208 42.024 ;
     RECT  12.227 43.344 13.208 44.472 ;
     RECT  12.205 45.792 13.208 47.4 ;
     RECT  12.161 48.672 13.208 49.08 ;
     RECT  13.021 50.064 13.208 53.64 ;
     RECT  12.805 55.584 13.208 57.144 ;
     RECT  13.093 58.128 13.208 59.88 ;
     RECT  11.869 61.632 13.208 61.992 ;
     RECT  12.805 63.264 13.208 63.864 ;
     RECT  12.877 64.992 13.208 67.704 ;
     RECT  12.661 68.928 13.208 70.728 ;
     RECT  13.093 71.904 13.208 75.612 ;
     RECT  13.208 2.148 13.312 75.612 ;
     RECT  13.312 2.418 13.504 75.342 ;
     RECT  13.504 61.104 13.565 65.256 ;
     RECT  13.504 71.856 13.619 73.32 ;
     RECT  13.504 74.88 13.619 74.904 ;
     RECT  13.504 66.72 13.637 67.944 ;
     RECT  13.504 20.544 13.645 22.824 ;
     RECT  13.504 14.88 13.667 15.768 ;
     RECT  13.645 20.544 13.667 21.624 ;
     RECT  13.645 22.8 13.667 22.824 ;
     RECT  13.504 2.592 13.673 3.672 ;
     RECT  13.504 40.944 13.673 49.08 ;
     RECT  13.673 2.592 13.708 3.576 ;
     RECT  13.504 8.496 13.708 12.792 ;
     RECT  13.504 4.752 13.709 4.968 ;
     RECT  13.708 8.496 13.709 12.264 ;
     RECT  13.504 50.064 13.709 53.64 ;
     RECT  13.504 17.664 13.756 19.56 ;
     RECT  13.619 72.24 13.781 73.32 ;
     RECT  13.504 23.808 13.817 24.744 ;
     RECT  13.673 41.04 13.817 49.08 ;
     RECT  13.504 57.552 13.817 60.024 ;
     RECT  13.756 19.536 13.853 19.56 ;
     RECT  12.803 76.896 13.853 77.64 ;
     RECT  13.781 72.384 13.889 73.32 ;
     RECT  13.708 2.592 13.925 2.856 ;
     RECT  13.817 23.808 13.925 23.928 ;
     RECT  13.637 66.72 13.955 67.848 ;
     RECT  13.756 17.664 13.997 18.216 ;
     RECT  13.925 23.808 14.069 23.832 ;
     RECT  13.709 4.944 14.105 4.968 ;
     RECT  13.504 6.864 14.105 7.368 ;
     RECT  13.565 64.416 14.141 65.256 ;
     RECT  14.141 64.656 14.285 65.256 ;
     RECT  13.817 57.648 14.321 60.024 ;
     RECT  13.853 77.424 14.321 77.64 ;
     RECT  13.709 50.112 14.435 53.64 ;
     RECT  13.504 54.672 14.435 56.328 ;
     RECT  13.504 38.64 14.501 39.048 ;
     RECT  14.321 57.696 14.533 60.024 ;
     RECT  13.565 61.104 14.533 62.952 ;
     RECT  13.667 20.544 14.569 21.096 ;
     RECT  13.504 34.176 14.569 37.08 ;
     RECT  13.504 68.928 14.573 69 ;
     RECT  14.533 57.696 14.579 62.952 ;
     RECT  14.321 77.424 14.609 77.448 ;
     RECT  13.709 8.496 14.627 10.056 ;
     RECT  14.105 7.344 14.645 7.368 ;
     RECT  13.817 43.296 14.681 49.08 ;
     RECT  14.569 34.176 14.749 37.128 ;
     RECT  13.889 72.384 14.78 72.984 ;
     RECT  13.504 31.392 14.785 33.096 ;
     RECT  14.749 34.128 14.785 37.128 ;
     RECT  13.817 41.04 14.785 42.024 ;
     RECT  14.579 59.808 14.821 62.952 ;
     RECT  13.504 70.704 14.821 70.728 ;
     RECT  14.78 72.144 14.821 72.984 ;
     RECT  13.925 2.832 14.857 2.856 ;
     RECT  13.709 11.04 14.861 12.264 ;
     RECT  14.821 59.808 14.861 63.24 ;
     RECT  14.828 16.272 14.869 16.296 ;
     RECT  13.997 17.664 14.869 17.688 ;
     RECT  14.861 61.008 14.905 63.24 ;
     RECT  14.869 16.272 14.915 17.688 ;
     RECT  13.504 27.6 15.001 28.872 ;
     RECT  13.667 14.88 15.037 14.904 ;
     RECT  14.501 38.64 15.073 38.952 ;
     RECT  15.001 27.36 15.145 28.872 ;
     RECT  13.955 66.72 15.145 67.704 ;
     RECT  14.627 8.688 15.181 10.056 ;
     RECT  14.861 11.04 15.181 11.208 ;
     RECT  14.681 43.296 15.181 43.896 ;
     RECT  14.915 17.04 15.217 17.688 ;
     RECT  15.073 38.496 15.253 38.952 ;
     RECT  14.435 54.96 15.289 56.328 ;
     RECT  14.857 2.832 15.325 2.904 ;
     RECT  15.181 6.72 15.325 6.744 ;
     RECT  15.145 27.168 15.325 28.872 ;
     RECT  15.289 54.96 15.349 56.52 ;
     RECT  14.579 57.696 15.349 58.68 ;
     RECT  15.037 14.88 15.361 15.096 ;
     RECT  15.325 26.88 15.361 28.872 ;
     RECT  14.785 30.768 15.361 37.128 ;
     RECT  15.361 30.384 15.397 37.128 ;
     RECT  15.253 38.208 15.397 38.952 ;
     RECT  14.681 45.024 15.577 49.08 ;
     RECT  14.435 50.112 15.577 52.296 ;
     RECT  14.821 25.776 15.613 25.8 ;
     RECT  14.821 70.704 15.613 72.984 ;
     RECT  15.541 74.064 15.613 74.088 ;
     RECT  14.569 20.304 15.637 21.096 ;
     RECT  15.349 54.96 15.649 58.68 ;
     RECT  14.861 59.808 15.649 59.832 ;
     RECT  15.613 25.488 15.721 25.8 ;
     RECT  15.613 70.704 15.721 74.088 ;
     RECT  15.577 45.024 15.757 52.296 ;
     RECT  15.757 44.976 15.781 52.296 ;
     RECT  14.435 53.568 15.781 53.64 ;
     RECT  15.361 26.88 15.865 29.256 ;
     RECT  15.325 2.832 15.908 3.864 ;
     RECT  15.325 5.808 15.908 6.744 ;
     RECT  15.181 8.688 15.908 11.208 ;
     RECT  14.861 12.192 15.908 12.264 ;
     RECT  15.361 14.88 15.908 15.288 ;
     RECT  15.217 17.04 15.908 18.6 ;
     RECT  15.637 19.68 15.908 22.296 ;
     RECT  15.637 23.568 15.908 23.976 ;
     RECT  15.721 25.296 15.908 25.8 ;
     RECT  15.865 26.88 15.908 29.304 ;
     RECT  15.397 30.384 15.908 38.952 ;
     RECT  14.785 40.368 15.908 42.024 ;
     RECT  15.181 43.008 15.908 43.896 ;
     RECT  15.781 44.976 15.908 53.64 ;
     RECT  15.649 54.96 15.908 59.832 ;
     RECT  14.905 61.008 15.908 63.048 ;
     RECT  14.285 64.992 15.908 65.016 ;
     RECT  15.145 66.528 15.908 67.704 ;
     RECT  14.573 68.928 15.908 68.952 ;
     RECT  15.721 70.032 15.908 74.088 ;
     RECT  15.253 75.12 15.908 75.144 ;
     RECT  15.908 2.148 16.012 75.612 ;
     RECT  16.012 2.418 16.204 75.342 ;
     RECT  16.204 26.88 16.265 33.624 ;
     RECT  16.204 47.136 16.355 48.984 ;
     RECT  16.204 54.96 16.355 63.816 ;
     RECT  16.204 50.112 16.403 50.904 ;
     RECT  16.265 26.88 16.409 33.192 ;
     RECT  16.204 40.368 16.409 42.168 ;
     RECT  16.409 40.464 16.445 42.168 ;
     RECT  16.204 71.52 16.445 71.544 ;
     RECT  16.204 43.296 16.451 43.32 ;
     RECT  16.204 44.352 16.451 44.376 ;
     RECT  16.204 45.552 16.481 46.104 ;
     RECT  16.204 51.936 16.547 53.64 ;
     RECT  16.409 31.104 16.553 33.192 ;
     RECT  16.355 47.856 16.553 48.984 ;
     RECT  16.547 51.936 16.589 53.4 ;
     RECT  16.204 72.624 16.589 74.088 ;
     RECT  16.445 40.464 16.805 41.016 ;
     RECT  16.355 54.96 16.805 62.568 ;
     RECT  16.355 63.792 16.805 63.816 ;
     RECT  16.204 65.136 16.985 70.056 ;
     RECT  16.204 9.12 17.027 9.912 ;
     RECT  16.204 5.376 17.093 5.688 ;
     RECT  16.985 65.136 17.093 69.576 ;
     RECT  16.204 17.616 17.165 18.504 ;
     RECT  16.403 50.112 17.201 50.136 ;
     RECT  17.027 9.888 17.305 9.912 ;
     RECT  16.409 26.88 17.309 30.072 ;
     RECT  16.204 34.752 17.345 38.808 ;
     RECT  17.093 65.136 17.345 67.704 ;
     RECT  16.204 2.496 17.363 3.96 ;
     RECT  17.345 34.752 17.381 38.232 ;
     RECT  17.093 69.12 17.381 69.576 ;
     RECT  16.204 12.72 17.489 13.128 ;
     RECT  16.204 20.928 17.521 20.952 ;
     RECT  17.413 22.224 17.521 22.344 ;
     RECT  16.204 23.568 17.521 23.928 ;
     RECT  16.204 25.248 17.521 25.56 ;
     RECT  16.553 31.392 17.521 33.192 ;
     RECT  17.309 27.36 17.525 30.072 ;
     RECT  17.521 22.224 17.593 23.928 ;
     RECT  17.377 43.248 17.593 43.272 ;
     RECT  17.525 29.568 17.597 30.072 ;
     RECT  17.377 70.752 17.653 70.776 ;
     RECT  16.589 72.624 17.653 73.848 ;
     RECT  16.204 14.256 17.665 15.576 ;
     RECT  16.553 47.856 17.737 48.456 ;
     RECT  17.521 31.392 17.749 33.672 ;
     RECT  17.653 70.752 17.809 73.848 ;
     RECT  17.093 5.568 17.845 5.688 ;
     RECT  16.204 6.768 17.845 7.416 ;
     RECT  17.521 20.016 17.845 20.952 ;
     RECT  16.445 42.144 17.845 42.168 ;
     RECT  16.589 52.8 17.917 53.4 ;
     RECT  17.593 22.128 17.948 23.928 ;
     RECT  17.521 25.248 17.948 26.232 ;
     RECT  16.805 40.464 17.989 40.488 ;
     RECT  16.805 55.248 17.989 62.568 ;
     RECT  17.593 43.248 18.061 43.56 ;
     RECT  17.917 52.176 18.061 53.4 ;
     RECT  17.989 54.624 18.061 62.568 ;
     RECT  17.363 3.936 18.133 3.96 ;
     RECT  17.845 5.568 18.133 7.416 ;
     RECT  18.061 43.248 18.14 43.656 ;
     RECT  17.737 47.856 18.169 49.224 ;
     RECT  17.737 50.64 18.169 50.664 ;
     RECT  17.305 45.456 18.181 45.48 ;
     RECT  17.489 12.72 18.241 12.744 ;
     RECT  17.809 70.752 18.313 74.088 ;
     RECT  17.381 34.752 18.385 36.36 ;
     RECT  17.989 40.464 18.385 40.92 ;
     RECT  17.845 41.904 18.385 42.168 ;
     RECT  18.14 43.248 18.385 44.04 ;
     RECT  18.241 12.672 18.457 12.744 ;
     RECT  18.061 52.176 18.457 62.568 ;
     RECT  17.485 63.84 18.457 63.864 ;
     RECT  18.313 70.752 18.469 74.136 ;
     RECT  16.204 75.12 18.469 75.144 ;
     RECT  17.381 69.12 18.529 69.528 ;
     RECT  18.469 70.752 18.529 75.384 ;
     RECT  18.133 3.936 18.565 7.416 ;
     RECT  17.363 2.496 18.608 2.52 ;
     RECT  18.565 3.84 18.608 7.416 ;
     RECT  17.305 9.888 18.608 10.2 ;
     RECT  18.457 12.672 18.608 12.792 ;
     RECT  17.665 14.256 18.608 15.864 ;
     RECT  17.165 17.904 18.608 18.504 ;
     RECT  17.845 19.824 18.608 20.952 ;
     RECT  17.948 22.128 18.608 26.232 ;
     RECT  17.525 27.36 18.608 28.536 ;
     RECT  17.597 29.568 18.608 29.784 ;
     RECT  17.749 30.864 18.608 33.672 ;
     RECT  18.385 34.752 18.608 36.648 ;
     RECT  17.381 37.68 18.608 38.232 ;
     RECT  18.385 39.744 18.608 40.92 ;
     RECT  18.385 41.904 18.608 44.04 ;
     RECT  18.181 45.264 18.608 45.48 ;
     RECT  18.169 47.856 18.608 50.664 ;
     RECT  18.457 52.176 18.608 63.864 ;
     RECT  17.345 65.136 18.608 65.16 ;
     RECT  17.345 66.528 18.608 67.704 ;
     RECT  18.529 69.12 18.608 75.384 ;
     RECT  18.608 2.148 18.712 75.612 ;
     RECT  18.712 2.418 18.904 75.342 ;
     RECT  18.904 2.496 18.965 5.592 ;
     RECT  18.904 52.8 19.001 52.968 ;
     RECT  18.904 55.68 19.037 66.888 ;
     RECT  18.904 68.304 19.037 71.208 ;
     RECT  18.904 6.96 19.043 9.912 ;
     RECT  18.904 14.64 19.073 15.864 ;
     RECT  18.904 43.104 19.073 46.104 ;
     RECT  18.965 5.424 19.109 5.592 ;
     RECT  18.904 39.744 19.145 42.024 ;
     RECT  18.904 10.896 19.217 13.656 ;
     RECT  18.904 35.712 19.217 37.896 ;
     RECT  19.217 12.384 19.253 13.656 ;
     RECT  18.904 50.544 19.289 50.568 ;
     RECT  19.253 12.72 19.297 13.656 ;
     RECT  19.037 55.68 19.427 59.832 ;
     RECT  18.904 47.328 19.433 48.408 ;
     RECT  19.037 61.104 19.441 66.888 ;
     RECT  19.073 14.64 19.469 15.336 ;
     RECT  18.904 20.928 19.505 20.952 ;
     RECT  18.904 73.872 19.541 74.664 ;
     RECT  19.297 12.72 19.571 13.08 ;
     RECT  19.433 47.328 19.577 48.168 ;
     RECT  19.217 10.896 19.613 11.4 ;
     RECT  19.541 73.872 19.613 74.184 ;
     RECT  19.037 69.456 19.865 71.208 ;
     RECT  19.001 52.944 19.868 52.968 ;
     RECT  18.904 53.952 19.868 54.696 ;
     RECT  19.868 52.944 19.889 54.696 ;
     RECT  19.427 55.68 19.889 58.104 ;
     RECT  19.469 14.64 19.897 14.664 ;
     RECT  18.904 22.8 19.897 32.856 ;
     RECT  19.897 22.8 19.901 32.904 ;
     RECT  19.889 52.944 19.955 58.104 ;
     RECT  19.955 54.576 19.973 58.104 ;
     RECT  19.037 68.304 20.005 68.328 ;
     RECT  19.865 69.456 20.005 69.48 ;
     RECT  18.904 72.192 20.009 72.504 ;
     RECT  19.613 74.064 20.045 74.184 ;
     RECT  18.904 18.48 20.077 19.416 ;
     RECT  19.897 50.832 20.108 50.856 ;
     RECT  19.865 70.656 20.113 71.208 ;
     RECT  20.009 72.192 20.113 72.216 ;
     RECT  18.904 33.888 20.149 33.912 ;
     RECT  20.005 68.304 20.149 69.48 ;
     RECT  19.043 6.96 20.221 9.096 ;
     RECT  19.901 25.2 20.221 32.904 ;
     RECT  20.149 33.888 20.221 34.152 ;
     RECT  19.145 40.08 20.221 42.024 ;
     RECT  20.077 18.48 20.225 19.896 ;
     RECT  19.973 54.576 20.225 54.744 ;
     RECT  20.149 67.92 20.243 69.48 ;
     RECT  20.243 67.92 20.284 68.376 ;
     RECT  20.221 6.96 20.293 9.144 ;
     RECT  20.221 40.08 20.365 42.216 ;
     RECT  18.965 2.496 20.437 4.44 ;
     RECT  19.109 5.424 20.437 5.448 ;
     RECT  19.955 52.944 20.437 53.592 ;
     RECT  19.441 65.136 20.473 66.888 ;
     RECT  20.284 67.92 20.473 68.328 ;
     RECT  19.217 35.712 20.509 37.128 ;
     RECT  20.509 35.712 20.545 37.416 ;
     RECT  19.073 43.632 20.545 46.104 ;
     RECT  20.108 50.832 20.653 51.048 ;
     RECT  20.545 43.632 20.689 46.152 ;
     RECT  19.577 47.328 20.689 47.928 ;
     RECT  20.365 40.08 20.905 42.264 ;
     RECT  19.901 22.8 20.941 24.168 ;
     RECT  20.221 25.2 20.941 34.152 ;
     RECT  19.441 61.104 20.977 63.816 ;
     RECT  20.977 61.056 21.041 63.816 ;
     RECT  21.041 60.816 21.049 63.816 ;
     RECT  20.941 22.8 21.061 34.152 ;
     RECT  20.243 69.456 21.061 69.48 ;
     RECT  20.113 70.656 21.061 72.216 ;
     RECT  20.905 40.08 21.109 42.312 ;
     RECT  21.061 69.456 21.121 72.84 ;
     RECT  21.109 40.08 21.157 42.552 ;
     RECT  20.689 43.632 21.157 47.928 ;
     RECT  20.293 6.72 21.193 9.144 ;
     RECT  20.545 35.712 21.193 37.992 ;
     RECT  20.045 74.16 21.193 74.184 ;
     RECT  20.005 75.216 21.193 75.24 ;
     RECT  21.013 21.072 21.265 21.096 ;
     RECT  21.061 22.464 21.265 34.152 ;
     RECT  21.193 35.424 21.265 37.992 ;
     RECT  21.157 39.12 21.265 47.928 ;
     RECT  21.049 60.816 21.265 63.912 ;
     RECT  20.473 65.136 21.265 68.328 ;
     RECT  20.437 2.496 21.308 5.448 ;
     RECT  21.193 6.72 21.308 9.288 ;
     RECT  19.613 10.896 21.308 11.304 ;
     RECT  19.897 14.208 21.308 14.664 ;
     RECT  20.041 15.84 21.308 15.864 ;
     RECT  20.225 18.48 21.308 19.608 ;
     RECT  21.265 21.072 21.308 34.152 ;
     RECT  21.265 35.424 21.308 47.928 ;
     RECT  20.833 49.584 21.308 49.608 ;
     RECT  20.653 50.832 21.308 51.384 ;
     RECT  20.437 52.752 21.308 53.592 ;
     RECT  20.225 54.624 21.308 54.744 ;
     RECT  19.973 56.544 21.308 58.104 ;
     RECT  19.427 59.184 21.308 59.832 ;
     RECT  21.265 60.816 21.308 68.328 ;
     RECT  21.121 69.456 21.308 73.032 ;
     RECT  21.193 74.16 21.308 75.24 ;
     RECT  21.308 2.148 21.445 75.612 ;
     RECT  21.445 2.016 21.541 75.612 ;
     RECT  21.541 2.016 21.587 75.768 ;
     RECT  21.587 2.418 21.604 75.768 ;
     RECT  21.604 75.216 21.665 75.768 ;
     RECT  21.604 28.272 21.701 34.152 ;
     RECT  21.604 35.136 21.701 38.28 ;
     RECT  21.604 50.016 21.701 52.824 ;
     RECT  21.604 62.16 21.737 65.544 ;
     RECT  21.604 66.72 21.737 67.848 ;
     RECT  21.737 62.496 21.773 65.544 ;
     RECT  21.604 9.264 21.779 11.448 ;
     RECT  21.604 13.488 21.779 14.664 ;
     RECT  21.779 14.208 21.827 14.664 ;
     RECT  21.701 28.272 21.881 29.064 ;
     RECT  21.604 39.888 21.881 44.712 ;
     RECT  21.604 45.792 21.881 45.816 ;
     RECT  21.604 15.84 22.115 18.792 ;
     RECT  21.604 56.544 22.169 58.824 ;
     RECT  21.737 66.72 22.169 67.704 ;
     RECT  21.604 19.92 22.241 20.424 ;
     RECT  21.604 71.424 22.259 73.128 ;
     RECT  21.701 51.648 22.313 52.824 ;
     RECT  21.604 7.968 22.349 7.992 ;
     RECT  21.604 46.992 22.385 48.552 ;
     RECT  22.169 56.544 22.421 58.68 ;
     RECT  22.259 71.424 22.421 72.84 ;
     RECT  21.881 39.888 22.457 42.744 ;
     RECT  22.169 66.768 22.457 67.704 ;
     RECT  21.604 59.808 22.529 59.832 ;
     RECT  21.604 69.12 22.597 69.528 ;
     RECT  22.241 20.4 22.601 20.424 ;
     RECT  22.457 66.768 22.601 67.128 ;
     RECT  21.701 36.624 22.669 38.28 ;
     RECT  22.115 17.232 22.673 18.792 ;
     RECT  21.701 30.144 22.705 34.152 ;
     RECT  21.701 35.136 22.705 35.16 ;
     RECT  21.604 2.88 22.709 4.44 ;
     RECT  22.705 30.144 22.733 35.16 ;
     RECT  22.669 36.576 22.733 38.28 ;
     RECT  22.709 2.88 22.741 3.96 ;
     RECT  21.604 21.696 22.741 21.768 ;
     RECT  22.601 66.816 22.745 67.128 ;
     RECT  22.115 15.84 22.777 16.2 ;
     RECT  22.741 21.456 22.777 21.768 ;
     RECT  22.421 56.544 22.777 57.672 ;
     RECT  21.604 60.912 22.777 60.936 ;
     RECT  21.773 62.496 22.777 64.872 ;
     RECT  21.779 11.088 22.789 11.208 ;
     RECT  22.705 12.576 22.789 12.6 ;
     RECT  22.789 12.576 22.813 13.128 ;
     RECT  21.827 14.208 22.813 14.232 ;
     RECT  22.813 12.576 22.835 14.232 ;
     RECT  21.881 29.04 22.844 29.064 ;
     RECT  22.733 30.144 22.844 38.28 ;
     RECT  22.835 13.104 22.876 14.232 ;
     RECT  22.844 29.04 22.885 38.28 ;
     RECT  21.779 9.264 22.921 9.672 ;
     RECT  21.701 50.016 22.921 50.424 ;
     RECT  21.604 74.16 22.921 74.184 ;
     RECT  21.604 22.8 22.925 27.096 ;
     RECT  22.921 49.536 22.925 50.424 ;
     RECT  22.745 66.864 22.925 67.128 ;
     RECT  22.885 28.992 22.931 38.28 ;
     RECT  22.789 11.088 22.957 11.256 ;
     RECT  22.921 9.264 22.968 9.96 ;
     RECT  21.604 6.048 22.988 6.072 ;
     RECT  22.741 2.832 23.027 3.96 ;
     RECT  22.988 4.944 23.029 6.072 ;
     RECT  22.968 9.024 23.029 9.96 ;
     RECT  22.957 10.992 23.029 11.256 ;
     RECT  23.027 3.408 23.033 3.96 ;
     RECT  22.777 62.208 23.065 64.872 ;
     RECT  22.457 40.032 23.137 42.744 ;
     RECT  21.881 43.728 23.137 44.712 ;
     RECT  22.876 13.68 23.237 14.232 ;
     RECT  22.777 15.456 23.237 16.2 ;
     RECT  23.237 13.68 23.269 16.2 ;
     RECT  22.673 17.232 23.269 18.744 ;
     RECT  22.931 30.24 23.269 38.28 ;
     RECT  22.777 60.048 23.317 60.936 ;
     RECT  23.029 9.024 23.353 11.256 ;
     RECT  22.597 68.976 23.353 69.528 ;
     RECT  22.421 71.904 23.389 72.84 ;
     RECT  23.389 71.712 23.461 72.84 ;
     RECT  22.777 21.072 23.497 21.768 ;
     RECT  22.925 22.8 23.497 26.712 ;
     RECT  22.921 74.064 23.497 74.184 ;
     RECT  23.461 71.04 23.641 72.84 ;
     RECT  23.497 73.824 23.641 74.184 ;
     RECT  22.313 52.032 23.677 52.824 ;
     RECT  23.353 68.976 23.756 70.008 ;
     RECT  23.756 68.88 23.797 70.008 ;
     RECT  23.641 71.04 23.797 74.184 ;
     RECT  23.029 27.888 23.857 27.912 ;
     RECT  22.931 28.992 23.857 29.016 ;
     RECT  23.317 60.048 23.857 60.984 ;
     RECT  22.925 66.864 23.965 67.08 ;
     RECT  23.269 30.24 24.001 38.472 ;
     RECT  23.033 3.744 24.008 3.96 ;
     RECT  23.029 4.944 24.008 6.6 ;
     RECT  23.353 8.496 24.008 11.256 ;
     RECT  23.269 13.68 24.008 18.744 ;
     RECT  23.497 21.072 24.008 26.712 ;
     RECT  23.857 27.888 24.008 29.016 ;
     RECT  24.001 30.24 24.008 38.76 ;
     RECT  23.137 40.032 24.008 44.712 ;
     RECT  22.777 46.08 24.008 46.104 ;
     RECT  22.385 47.616 24.008 48.552 ;
     RECT  22.925 49.536 24.008 50.04 ;
     RECT  23.677 51.936 24.008 52.824 ;
     RECT  22.777 56.064 24.008 57.672 ;
     RECT  22.421 58.656 24.008 58.68 ;
     RECT  23.857 59.76 24.008 60.984 ;
     RECT  23.065 62.208 24.008 65.496 ;
     RECT  23.965 66.768 24.008 67.08 ;
     RECT  23.797 68.208 24.008 74.184 ;
     RECT  21.665 75.216 24.008 75.24 ;
     RECT  24.008 2.148 24.112 75.612 ;
     RECT  24.112 2.418 24.304 75.342 ;
     RECT  24.304 8.496 24.365 9.528 ;
     RECT  24.304 47.424 24.365 47.88 ;
     RECT  24.304 59.472 24.437 59.784 ;
     RECT  24.304 29.52 24.473 32.616 ;
     RECT  24.473 29.52 24.508 29.544 ;
     RECT  24.304 37.968 24.545 38.76 ;
     RECT  24.304 72.816 24.545 75.144 ;
     RECT  24.304 68.208 24.581 71.736 ;
     RECT  24.304 21.504 24.653 27.192 ;
     RECT  24.473 30.624 24.653 32.616 ;
     RECT  24.304 56.064 24.653 56.904 ;
     RECT  24.304 62.208 24.653 67.08 ;
     RECT  24.653 62.208 24.689 66.168 ;
     RECT  24.581 68.208 24.689 69.864 ;
     RECT  24.304 33.6 24.725 35.016 ;
     RECT  24.689 69.84 24.725 69.864 ;
     RECT  24.304 3.12 24.755 4.296 ;
     RECT  24.304 49.008 24.803 49.992 ;
     RECT  24.755 3.12 24.851 3.96 ;
     RECT  24.304 40.032 24.941 40.056 ;
     RECT  24.304 10.704 25.049 14.664 ;
     RECT  24.304 58.128 25.121 58.152 ;
     RECT  24.304 41.376 25.139 45.192 ;
     RECT  25.049 10.704 25.157 11.736 ;
     RECT  25.139 41.376 25.165 43.944 ;
     RECT  24.304 60.816 25.193 61.032 ;
     RECT  25.139 45.024 25.229 45.192 ;
     RECT  24.803 49.008 25.229 49.032 ;
     RECT  25.193 60.816 25.265 60.936 ;
     RECT  24.581 71.088 25.292 71.736 ;
     RECT  24.851 3.36 25.301 3.96 ;
     RECT  25.049 12.816 25.301 14.664 ;
     RECT  24.545 73.776 25.301 75.144 ;
     RECT  24.725 33.936 25.333 35.016 ;
     RECT  24.304 36 25.333 36.888 ;
     RECT  24.365 47.424 25.34 47.64 ;
     RECT  25.34 47.424 25.381 48.072 ;
     RECT  24.304 16.896 25.405 17.256 ;
     RECT  24.545 37.968 25.409 38.472 ;
     RECT  25.381 47.28 25.427 48.072 ;
     RECT  25.301 14.112 25.441 14.664 ;
     RECT  24.304 53.76 25.441 54.744 ;
     RECT  25.441 53.568 25.525 54.744 ;
     RECT  24.437 59.472 25.549 59.496 ;
     RECT  25.265 60.816 25.549 60.84 ;
     RECT  25.292 71.088 25.549 72.408 ;
     RECT  25.405 16.896 25.589 17.304 ;
     RECT  25.427 47.28 25.657 47.304 ;
     RECT  24.304 52.176 25.661 52.488 ;
     RECT  25.549 70.656 25.661 72.408 ;
     RECT  25.525 53.904 25.667 54.744 ;
     RECT  25.301 73.776 25.697 74.136 ;
     RECT  25.549 59.472 25.724 60.84 ;
     RECT  24.689 62.544 25.733 66.168 ;
     RECT  24.304 5.76 25.873 5.88 ;
     RECT  24.304 28.464 25.981 28.488 ;
     RECT  24.653 56.064 25.981 56.568 ;
     RECT  25.477 50.688 26.005 50.712 ;
     RECT  24.689 68.208 26.053 68.424 ;
     RECT  25.661 71.088 26.089 72.408 ;
     RECT  25.873 7.92 26.125 7.944 ;
     RECT  24.653 30.912 26.125 32.616 ;
     RECT  26.005 50.688 26.125 51.384 ;
     RECT  26.053 67.68 26.125 68.424 ;
     RECT  25.733 62.736 26.149 66.168 ;
     RECT  24.653 21.504 26.161 24.552 ;
     RECT  25.441 14.112 26.197 14.856 ;
     RECT  24.304 18.432 26.197 19.272 ;
     RECT  26.161 20.592 26.197 24.552 ;
     RECT  24.653 25.824 26.269 27.192 ;
     RECT  25.981 28.464 26.269 28.536 ;
     RECT  25.724 59.232 26.269 60.84 ;
     RECT  26.125 7.728 26.305 7.944 ;
     RECT  24.365 9.024 26.305 9.528 ;
     RECT  26.269 25.824 26.333 28.536 ;
     RECT  25.873 5.76 26.341 6.408 ;
     RECT  25.729 39.84 26.341 39.864 ;
     RECT  25.165 41.376 26.341 43.56 ;
     RECT  25.229 45.024 26.341 45.048 ;
     RECT  25.657 47.04 26.413 47.304 ;
     RECT  26.341 5.568 26.485 6.408 ;
     RECT  26.125 30.912 26.485 32.808 ;
     RECT  25.333 33.936 26.485 36.888 ;
     RECT  25.301 12.816 26.557 12.84 ;
     RECT  26.557 12.48 26.701 12.84 ;
     RECT  25.301 3.408 26.708 3.96 ;
     RECT  26.485 5.472 26.708 6.408 ;
     RECT  26.305 7.728 26.708 9.528 ;
     RECT  25.157 10.704 26.708 11.496 ;
     RECT  26.701 12.48 26.708 13.08 ;
     RECT  26.197 14.112 26.708 15.048 ;
     RECT  25.589 16.896 26.708 17.256 ;
     RECT  26.197 18.432 26.708 24.552 ;
     RECT  26.333 25.68 26.708 28.536 ;
     RECT  26.485 30.912 26.708 36.888 ;
     RECT  25.409 38.208 26.708 38.472 ;
     RECT  26.341 39.84 26.708 43.56 ;
     RECT  26.341 45.024 26.708 45.72 ;
     RECT  26.413 47.04 26.708 47.64 ;
     RECT  26.125 50.304 26.708 51.384 ;
     RECT  25.661 52.464 26.708 52.488 ;
     RECT  25.667 53.904 26.708 54.36 ;
     RECT  25.981 55.824 26.708 56.568 ;
     RECT  26.269 59.232 26.708 61.368 ;
     RECT  26.149 62.736 26.708 66.696 ;
     RECT  26.125 67.68 26.708 69 ;
     RECT  26.089 71.088 26.708 72.504 ;
     RECT  25.697 74.064 26.708 74.136 ;
     RECT  25.301 75.12 26.708 75.144 ;
     RECT  26.708 2.148 26.812 75.612 ;
     RECT  26.812 2.418 27.004 75.342 ;
     RECT  27.004 10.896 27.101 11.208 ;
     RECT  27.004 7.92 27.137 9.144 ;
     RECT  27.101 10.944 27.173 11.208 ;
     RECT  27.004 49.488 27.196 50.328 ;
     RECT  27.004 21.12 27.281 24.648 ;
     RECT  27.004 70.992 27.317 75.288 ;
     RECT  27.004 25.728 27.347 26.712 ;
     RECT  27.004 5.088 27.353 6.648 ;
     RECT  27.317 70.992 27.388 71.64 ;
     RECT  27.004 12.48 27.389 15.336 ;
     RECT  27.347 26.256 27.389 26.712 ;
     RECT  27.004 61.344 27.389 63.864 ;
     RECT  27.004 16.512 27.395 18.12 ;
     RECT  27.004 46.992 27.395 47.352 ;
     RECT  27.317 73.344 27.397 75.288 ;
     RECT  27.004 67.152 27.425 67.848 ;
     RECT  27.389 12.528 27.461 15.336 ;
     RECT  27.196 50.304 27.497 50.328 ;
     RECT  27.004 42.192 27.533 45.864 ;
     RECT  27.533 44.4 27.539 45.864 ;
     RECT  27.388 71.472 27.641 71.64 ;
     RECT  27.004 51.36 27.724 54.744 ;
     RECT  27.004 27.792 27.827 28.536 ;
     RECT  27.004 64.992 27.973 65.88 ;
     RECT  27.425 67.152 27.973 67.272 ;
     RECT  27.004 38.016 27.997 38.76 ;
     RECT  27.973 64.992 28.019 67.272 ;
     RECT  27.004 3.408 28.069 3.912 ;
     RECT  27.004 40.56 28.069 40.968 ;
     RECT  27.539 45.168 28.073 45.192 ;
     RECT  27.004 68.976 28.073 69 ;
     RECT  27.397 73.344 28.073 74.664 ;
     RECT  27.724 51.36 28.109 51.912 ;
     RECT  27.395 46.992 28.213 47.112 ;
     RECT  28.069 3.36 28.253 3.912 ;
     RECT  28.033 29.616 28.285 29.64 ;
     RECT  27.004 30.768 28.285 36.744 ;
     RECT  28.069 40.08 28.321 40.968 ;
     RECT  27.533 42.192 28.321 43.416 ;
     RECT  27.004 56.4 28.321 56.568 ;
     RECT  28.321 56.4 28.357 56.664 ;
     RECT  28.033 57.888 28.357 57.912 ;
     RECT  28.357 56.4 28.361 57.912 ;
     RECT  27.389 61.344 28.361 63.624 ;
     RECT  27.389 26.256 28.429 26.664 ;
     RECT  27.641 71.616 28.429 71.64 ;
     RECT  28.361 62.976 28.453 63.624 ;
     RECT  28.019 64.992 28.453 65.64 ;
     RECT  27.353 5.568 28.465 6.648 ;
     RECT  28.285 29.616 28.465 36.744 ;
     RECT  27.997 38.016 28.465 39.096 ;
     RECT  27.173 10.992 28.501 11.208 ;
     RECT  28.501 10.848 28.537 11.208 ;
     RECT  28.361 61.344 28.537 61.368 ;
     RECT  27.004 19.344 28.604 19.368 ;
     RECT  27.137 8.832 28.645 9.144 ;
     RECT  28.604 19.344 28.645 19.752 ;
     RECT  28.429 25.488 28.717 26.664 ;
     RECT  28.109 51.888 28.717 51.912 ;
     RECT  27.724 53.184 28.717 54.744 ;
     RECT  27.827 27.888 28.753 28.536 ;
     RECT  28.465 29.616 28.753 39.096 ;
     RECT  27.281 21.12 28.796 23.928 ;
     RECT  28.141 49.2 28.933 49.224 ;
     RECT  28.361 56.544 28.933 57.912 ;
     RECT  28.933 48.96 28.969 49.224 ;
     RECT  28.213 46.56 29.005 47.112 ;
     RECT  28.019 66.72 29.005 67.272 ;
     RECT  28.753 27.888 29.041 39.096 ;
     RECT  28.321 40.08 29.041 43.416 ;
     RECT  28.717 25.488 29.077 26.808 ;
     RECT  29.041 27.888 29.077 43.416 ;
     RECT  29.005 46.56 29.077 47.736 ;
     RECT  28.796 20.976 29.125 23.928 ;
     RECT  29.077 25.104 29.125 43.416 ;
     RECT  29.125 20.976 29.185 43.416 ;
     RECT  29.041 44.448 29.185 44.472 ;
     RECT  28.969 48.96 29.185 49.32 ;
     RECT  28.253 3.36 29.269 3.384 ;
     RECT  28.537 10.848 29.269 11.256 ;
     RECT  27.461 12.528 29.269 13.08 ;
     RECT  27.461 14.352 29.269 15.336 ;
     RECT  29.269 10.848 29.365 15.336 ;
     RECT  27.395 16.512 29.365 17.64 ;
     RECT  28.933 56.544 29.365 58.152 ;
     RECT  28.073 73.344 29.365 74.568 ;
     RECT  29.269 3.36 29.408 3.432 ;
     RECT  28.465 5.568 29.408 7.368 ;
     RECT  28.645 8.736 29.408 9.144 ;
     RECT  29.365 10.848 29.408 17.64 ;
     RECT  28.645 18.768 29.408 19.752 ;
     RECT  29.185 20.976 29.408 44.472 ;
     RECT  29.077 46.32 29.408 47.736 ;
     RECT  29.185 48.768 29.408 49.32 ;
     RECT  28.213 50.832 29.408 50.856 ;
     RECT  28.717 51.888 29.408 54.744 ;
     RECT  29.365 56.064 29.408 58.152 ;
     RECT  28.537 60.96 29.408 61.368 ;
     RECT  28.453 62.976 29.408 65.64 ;
     RECT  29.005 66.72 29.408 67.704 ;
     RECT  28.429 71.616 29.408 71.784 ;
     RECT  29.365 73.344 29.408 74.664 ;
     RECT  29.408 2.148 29.512 75.612 ;
     RECT  29.512 2.418 29.704 75.342 ;
     RECT  29.704 45.12 29.765 50.856 ;
     RECT  29.704 12.864 29.801 14.472 ;
     RECT  29.704 34.176 29.837 38.76 ;
     RECT  29.704 8.832 29.873 9.336 ;
     RECT  29.765 45.12 29.909 49.944 ;
     RECT  29.909 47.328 30.025 49.944 ;
     RECT  29.704 64.368 30.035 67.704 ;
     RECT  29.873 9.024 30.089 9.336 ;
     RECT  29.801 12.864 30.089 14.376 ;
     RECT  29.704 20.448 30.179 30.6 ;
     RECT  29.704 15.504 30.275 18.216 ;
     RECT  29.704 19.392 30.275 19.416 ;
     RECT  30.025 47.328 30.275 48.888 ;
     RECT  29.704 5.76 30.305 6.648 ;
     RECT  30.179 26.592 30.341 30.6 ;
     RECT  30.275 47.712 30.341 48.888 ;
     RECT  30.035 65.568 30.341 67.704 ;
     RECT  30.341 48.864 30.413 48.888 ;
     RECT  29.909 45.12 30.419 46.296 ;
     RECT  29.704 32.304 30.485 33.096 ;
     RECT  30.341 66.144 30.557 67.704 ;
     RECT  29.704 3.36 30.629 3.384 ;
     RECT  30.275 15.504 30.629 16.2 ;
     RECT  30.419 45.696 30.629 46.296 ;
     RECT  29.704 74.064 30.697 74.664 ;
     RECT  30.035 64.368 30.733 64.392 ;
     RECT  29.704 69.888 30.733 72.216 ;
     RECT  29.704 55.824 30.737 60.36 ;
     RECT  30.275 17.28 30.757 18.216 ;
     RECT  29.704 52.464 30.757 53.832 ;
     RECT  30.089 9.312 30.764 9.336 ;
     RECT  29.704 40.08 30.773 43.416 ;
     RECT  30.737 57.6 30.773 60.36 ;
     RECT  30.764 9.312 30.805 9.528 ;
     RECT  30.629 15.504 30.805 16.056 ;
     RECT  29.704 61.584 30.805 61.608 ;
     RECT  29.704 62.832 30.805 63 ;
     RECT  30.773 59.808 30.809 60.36 ;
     RECT  30.557 66.768 30.809 67.704 ;
     RECT  30.733 68.976 30.809 72.216 ;
     RECT  30.757 17.28 30.844 18.36 ;
     RECT  30.697 74.064 30.845 75.384 ;
     RECT  30.025 49.92 30.853 49.944 ;
     RECT  30.757 52.464 30.853 54.744 ;
     RECT  30.737 55.824 30.853 56.568 ;
     RECT  30.341 26.592 30.881 29.064 ;
     RECT  30.812 7.776 30.899 7.8 ;
     RECT  30.805 9.312 30.899 10.296 ;
     RECT  30.853 49.92 30.899 50.136 ;
     RECT  30.853 52.464 30.899 56.568 ;
     RECT  30.845 74.736 30.899 75.384 ;
     RECT  30.805 61.584 30.913 63.192 ;
     RECT  30.733 64.176 30.913 64.392 ;
     RECT  30.809 67.248 30.913 67.704 ;
     RECT  30.809 68.976 30.913 69 ;
     RECT  30.809 70.56 30.917 72.216 ;
     RECT  30.773 57.6 30.953 58.776 ;
     RECT  30.913 67.248 30.953 69 ;
     RECT  30.089 13.584 31.045 14.376 ;
     RECT  30.805 15.408 31.045 16.056 ;
     RECT  30.179 20.448 31.061 25.608 ;
     RECT  30.985 5.04 31.091 5.064 ;
     RECT  29.837 34.752 31.129 38.76 ;
     RECT  30.917 71.616 31.133 72.216 ;
     RECT  30.953 67.248 31.139 68.616 ;
     RECT  31.045 13.584 31.237 16.056 ;
     RECT  30.305 6.144 31.345 6.648 ;
     RECT  30.341 30.096 31.345 30.6 ;
     RECT  31.129 34.752 31.345 39.096 ;
     RECT  31.345 34.464 31.417 39.096 ;
     RECT  30.773 40.08 31.417 43.32 ;
     RECT  31.061 20.448 31.453 25.512 ;
     RECT  31.417 34.464 31.525 43.32 ;
     RECT  30.485 32.304 31.628 32.328 ;
     RECT  31.237 13.056 31.669 16.056 ;
     RECT  30.844 17.28 31.669 17.88 ;
     RECT  30.881 26.736 31.669 29.064 ;
     RECT  31.345 30.048 31.669 30.6 ;
     RECT  31.525 66.096 31.777 66.12 ;
     RECT  31.139 67.248 31.777 68.232 ;
     RECT  31.669 13.056 31.813 17.88 ;
     RECT  31.58 19.2 31.813 19.224 ;
     RECT  31.628 32.304 31.849 33.24 ;
     RECT  31.669 26.736 31.861 30.6 ;
     RECT  30.917 70.56 31.885 70.584 ;
     RECT  30.899 50.112 31.909 50.136 ;
     RECT  30.913 61.584 31.909 64.392 ;
     RECT  31.885 70.08 31.909 70.584 ;
     RECT  30.953 57.6 31.916 58.44 ;
     RECT  30.809 59.808 31.916 60.264 ;
     RECT  30.899 54.672 31.921 56.568 ;
     RECT  31.916 57.6 31.921 60.264 ;
     RECT  31.777 66.096 31.921 68.232 ;
     RECT  31.909 70.032 31.921 70.584 ;
     RECT  31.133 71.616 31.921 71.64 ;
     RECT  31.909 61.584 31.949 64.728 ;
     RECT  30.899 52.464 31.957 53.4 ;
     RECT  31.921 54.672 31.957 60.264 ;
     RECT  31.949 61.584 31.957 65.016 ;
     RECT  31.921 66 31.957 68.232 ;
     RECT  31.921 70.032 31.957 71.64 ;
     RECT  30.899 10.272 32.029 10.296 ;
     RECT  30.341 47.712 32.029 47.736 ;
     RECT  31.345 6.144 32.101 6.84 ;
     RECT  31.453 20.304 32.101 25.512 ;
     RECT  31.861 26.64 32.101 30.6 ;
     RECT  32.101 6.144 32.108 7.224 ;
     RECT  31.345 8.496 32.108 8.52 ;
     RECT  32.029 10.176 32.108 10.296 ;
     RECT  31.813 13.056 32.108 19.224 ;
     RECT  32.101 20.304 32.108 30.6 ;
     RECT  31.849 31.632 32.108 33.24 ;
     RECT  31.525 34.32 32.108 43.32 ;
     RECT  30.629 45.696 32.108 45.72 ;
     RECT  32.029 47.712 32.108 48.168 ;
     RECT  31.909 49.872 32.108 50.136 ;
     RECT  31.909 51.264 32.108 51.288 ;
     RECT  31.957 52.464 32.108 60.264 ;
     RECT  31.957 61.392 32.108 68.232 ;
     RECT  31.957 69.84 32.108 71.64 ;
     RECT  31.201 73.44 32.108 73.56 ;
     RECT  30.899 74.736 32.108 74.76 ;
     RECT  32.108 2.148 32.212 75.612 ;
     RECT  32.212 2.418 32.404 75.342 ;
     RECT  32.404 6.816 32.465 8.52 ;
     RECT  32.404 31.824 32.531 40.392 ;
     RECT  32.404 64.608 32.609 68.232 ;
     RECT  32.404 19.968 32.627 30.6 ;
     RECT  32.404 41.76 32.645 44.088 ;
     RECT  32.404 16.8 32.717 16.92 ;
     RECT  32.531 37.44 32.789 40.392 ;
     RECT  32.404 14.112 32.897 14.856 ;
     RECT  32.531 31.824 32.915 36.312 ;
     RECT  32.789 37.44 33.077 38.808 ;
     RECT  32.404 49.008 33.107 58.68 ;
     RECT  32.915 32.304 33.113 36.312 ;
     RECT  32.609 64.608 33.113 65.688 ;
     RECT  32.465 7.2 33.149 8.52 ;
     RECT  32.609 66.672 33.193 68.232 ;
     RECT  32.404 74.544 33.293 74.568 ;
     RECT  32.404 45.36 33.299 47.544 ;
     RECT  32.404 69.84 33.347 72.456 ;
     RECT  33.107 49.008 33.365 55.704 ;
     RECT  33.107 56.784 33.397 58.68 ;
     RECT  32.404 60.096 33.397 63.576 ;
     RECT  33.397 56.784 33.437 63.576 ;
     RECT  33.437 62.4 33.469 63.576 ;
     RECT  33.113 64.608 33.469 64.728 ;
     RECT  32.404 18.192 33.541 18.264 ;
     RECT  32.627 19.968 33.541 30.12 ;
     RECT  32.404 10.176 33.577 10.2 ;
     RECT  33.365 49.008 33.58 53.112 ;
     RECT  33.541 18.192 33.581 30.12 ;
     RECT  33.347 69.84 33.596 70.92 ;
     RECT  33.149 7.2 33.613 8.472 ;
     RECT  33.113 35.232 33.613 36.312 ;
     RECT  33.077 37.44 33.613 38.472 ;
     RECT  33.58 49.008 33.635 51.432 ;
     RECT  33.635 49.008 33.653 51.144 ;
     RECT  33.581 18.192 33.689 22.584 ;
     RECT  33.581 23.856 33.721 30.12 ;
     RECT  32.789 39.888 33.721 40.392 ;
     RECT  32.645 41.76 33.721 41.784 ;
     RECT  33.299 45.408 33.733 47.544 ;
     RECT  33.653 49.008 33.733 50.664 ;
     RECT  33.689 18.192 33.757 22.488 ;
     RECT  33.721 39.888 33.761 41.784 ;
     RECT  33.347 71.904 33.797 72.456 ;
     RECT  33.577 10.128 33.901 10.488 ;
     RECT  32.404 12 33.901 12.024 ;
     RECT  32.897 14.112 33.901 14.76 ;
     RECT  33.469 62.4 34.153 64.728 ;
     RECT  32.645 42.816 34.225 44.088 ;
     RECT  32.717 16.8 34.261 16.824 ;
     RECT  33.757 17.904 34.261 22.488 ;
     RECT  34.225 42.816 34.261 44.424 ;
     RECT  33.733 45.408 34.261 50.664 ;
     RECT  33.193 67.248 34.261 68.232 ;
     RECT  33.596 69.456 34.261 70.92 ;
     RECT  34.261 42.816 34.297 50.664 ;
     RECT  33.365 54.096 34.405 55.704 ;
     RECT  33.437 56.784 34.405 60.696 ;
     RECT  32.404 13.008 34.441 13.032 ;
     RECT  33.901 14.112 34.441 15.576 ;
     RECT  33.58 52.56 34.441 53.112 ;
     RECT  34.405 54.096 34.441 60.696 ;
     RECT  33.761 40.032 34.508 41.784 ;
     RECT  34.297 42.768 34.508 50.664 ;
     RECT  33.113 32.304 34.585 33.96 ;
     RECT  34.508 40.032 34.765 50.664 ;
     RECT  33.613 6.048 34.808 8.472 ;
     RECT  33.901 10.128 34.808 12.024 ;
     RECT  34.441 13.008 34.808 15.576 ;
     RECT  34.261 16.8 34.808 22.488 ;
     RECT  33.721 23.856 34.808 30.456 ;
     RECT  34.585 31.776 34.808 33.96 ;
     RECT  33.613 35.232 34.808 38.472 ;
     RECT  34.765 40.032 34.808 51.192 ;
     RECT  34.441 52.56 34.808 60.696 ;
     RECT  34.153 62.4 34.808 65.544 ;
     RECT  34.261 67.248 34.808 70.92 ;
     RECT  33.797 71.904 34.808 72.408 ;
     RECT  34.808 2.148 34.912 75.612 ;
     RECT  34.912 2.418 35.104 75.342 ;
     RECT  35.104 18.096 35.165 21 ;
     RECT  35.104 13.392 35.219 17.112 ;
     RECT  35.165 20.976 35.219 21 ;
     RECT  35.104 68.4 35.219 72.84 ;
     RECT  35.165 18.096 35.245 19.416 ;
     RECT  35.219 69.888 35.245 72.84 ;
     RECT  35.104 22.176 35.26 22.632 ;
     RECT  35.104 39.792 35.26 57 ;
     RECT  35.245 69.888 35.26 70.296 ;
     RECT  35.104 58.128 35.267 61.224 ;
     RECT  35.104 33.264 35.273 34.248 ;
     RECT  35.104 35.472 35.273 37.08 ;
     RECT  35.26 39.792 35.315 41.4 ;
     RECT  35.245 71.472 35.315 72.84 ;
     RECT  35.26 42.816 35.345 57 ;
     RECT  35.315 71.472 35.356 71.832 ;
     RECT  35.245 18.432 35.363 19.416 ;
     RECT  35.273 33.504 35.381 34.248 ;
     RECT  35.381 33.504 35.489 33.96 ;
     RECT  35.104 62.736 35.885 66.936 ;
     RECT  35.219 15.84 35.939 17.112 ;
     RECT  35.363 18.432 35.939 19.368 ;
     RECT  35.273 35.712 36.065 36.168 ;
     RECT  35.345 45.792 36.097 57 ;
     RECT  35.267 58.128 36.097 60.84 ;
     RECT  35.939 18.432 36.101 19.128 ;
     RECT  35.104 7.248 36.124 9.384 ;
     RECT  35.219 13.392 36.137 14.664 ;
     RECT  36.137 14.64 36.173 14.664 ;
     RECT  35.939 15.84 36.209 16.824 ;
     RECT  35.104 23.952 36.209 31.8 ;
     RECT  35.885 62.736 36.241 63.864 ;
     RECT  36.137 13.392 36.245 13.416 ;
     RECT  36.097 45.792 36.275 60.84 ;
     RECT  36.124 7.728 36.281 9.384 ;
     RECT  35.345 42.816 36.281 44.712 ;
     RECT  35.219 68.4 36.281 68.472 ;
     RECT  36.209 25.056 36.317 31.8 ;
     RECT  36.317 25.632 36.353 31.8 ;
     RECT  36.353 25.632 36.389 29.64 ;
     RECT  36.277 5.664 36.421 5.688 ;
     RECT  36.353 30.72 36.421 31.8 ;
     RECT  35.885 64.896 36.421 66.936 ;
     RECT  35.356 71.472 36.449 71.496 ;
     RECT  36.065 35.712 36.457 35.736 ;
     RECT  36.389 25.632 36.461 29.064 ;
     RECT  35.315 39.792 36.467 41.208 ;
     RECT  35.26 70.272 36.469 70.296 ;
     RECT  36.449 71.472 36.469 72.408 ;
     RECT  36.467 39.792 36.533 39.864 ;
     RECT  36.469 70.272 36.533 72.408 ;
     RECT  36.241 62.016 36.745 63.864 ;
     RECT  35.489 33.504 36.781 33.528 ;
     RECT  35.104 38.448 36.817 38.472 ;
     RECT  36.457 37.344 36.997 37.368 ;
     RECT  36.817 38.448 36.997 38.808 ;
     RECT  36.467 40.992 36.997 41.208 ;
     RECT  36.325 42.72 36.997 42.792 ;
     RECT  36.745 61.776 36.997 63.864 ;
     RECT  36.421 64.896 36.997 67.848 ;
     RECT  36.457 35.088 37.033 35.736 ;
     RECT  36.997 37.344 37.033 38.808 ;
     RECT  36.281 43.776 37.189 44.712 ;
     RECT  36.275 45.792 37.189 60.696 ;
     RECT  36.889 74.064 37.213 74.088 ;
     RECT  36.421 5.664 37.285 6.312 ;
     RECT  35.26 22.176 37.321 22.2 ;
     RECT  36.209 23.952 37.321 24.072 ;
     RECT  36.781 33.504 37.349 33.816 ;
     RECT  37.033 35.088 37.349 38.808 ;
     RECT  36.961 68.928 37.357 68.952 ;
     RECT  37.321 22.176 37.381 24.744 ;
     RECT  37.357 68.928 37.429 69.288 ;
     RECT  36.533 70.272 37.429 72.024 ;
     RECT  37.285 5.568 37.508 6.312 ;
     RECT  36.281 7.728 37.508 8.472 ;
     RECT  35.104 11.424 37.508 11.448 ;
     RECT  37.249 13.152 37.508 13.176 ;
     RECT  36.209 16.8 37.508 16.824 ;
     RECT  36.101 18.768 37.508 18.792 ;
     RECT  36.421 20.976 37.508 21 ;
     RECT  37.381 22.032 37.508 24.744 ;
     RECT  36.461 26.016 37.508 29.064 ;
     RECT  36.421 30.72 37.508 31.944 ;
     RECT  37.349 33.504 37.508 38.808 ;
     RECT  36.533 39.792 37.508 39.816 ;
     RECT  36.997 40.992 37.508 42.792 ;
     RECT  37.189 43.776 37.508 60.696 ;
     RECT  36.997 61.776 37.508 67.848 ;
     RECT  37.429 68.928 37.508 72.024 ;
     RECT  37.213 74.064 37.508 74.712 ;
     RECT  37.508 2.148 37.612 75.612 ;
     RECT  37.612 2.418 37.804 75.342 ;
     RECT  37.804 28.416 37.829 29.064 ;
     RECT  37.804 7.728 37.901 7.992 ;
     RECT  37.829 28.416 37.901 28.488 ;
     RECT  37.804 68.928 37.955 72.456 ;
     RECT  37.804 45.024 37.973 66.792 ;
     RECT  37.804 15.456 38.009 17.064 ;
     RECT  37.804 73.488 38.009 74.088 ;
     RECT  38.009 15.456 38.044 16.008 ;
     RECT  37.804 18.192 38.117 18.792 ;
     RECT  37.973 46.896 38.117 66.792 ;
     RECT  37.955 68.928 38.189 72.168 ;
     RECT  38.117 54.624 38.225 66.792 ;
     RECT  37.804 3.936 38.243 4.536 ;
     RECT  37.804 13.056 38.243 14.088 ;
     RECT  37.804 23.088 38.297 23.112 ;
     RECT  37.804 30.192 38.297 39.816 ;
     RECT  38.189 71.856 38.297 72.168 ;
     RECT  38.009 17.04 38.405 17.064 ;
     RECT  37.901 28.416 38.441 28.44 ;
     RECT  38.297 31.344 38.477 39.816 ;
     RECT  38.477 33.6 38.513 39.816 ;
     RECT  38.117 46.896 38.513 53.64 ;
     RECT  38.189 68.928 38.513 70.872 ;
     RECT  37.804 40.992 38.531 42.84 ;
     RECT  38.477 31.344 38.557 32.52 ;
     RECT  38.513 33.6 38.579 38.472 ;
     RECT  38.579 36.528 38.621 38.472 ;
     RECT  38.225 58.416 38.621 66.792 ;
     RECT  38.621 37.824 38.657 38.472 ;
     RECT  38.621 58.416 38.657 65.448 ;
     RECT  38.657 64.848 38.665 65.448 ;
     RECT  38.513 39.792 38.675 39.816 ;
     RECT  38.225 54.624 38.693 57.432 ;
     RECT  38.657 58.416 38.693 63.72 ;
     RECT  37.804 5.568 38.723 6.552 ;
     RECT  38.693 58.416 38.723 62.664 ;
     RECT  38.723 6 38.729 6.552 ;
     RECT  37.804 19.968 38.729 19.992 ;
     RECT  38.531 42.816 38.765 42.84 ;
     RECT  38.579 33.6 38.771 35.496 ;
     RECT  38.513 46.896 38.771 53.592 ;
     RECT  38.693 54.624 38.771 56.472 ;
     RECT  38.621 66.72 38.771 66.792 ;
     RECT  38.621 36.528 38.801 36.792 ;
     RECT  38.665 64.896 38.801 65.448 ;
     RECT  38.771 33.984 38.809 35.4 ;
     RECT  37.804 20.976 38.837 21 ;
     RECT  38.297 30.192 38.837 30.216 ;
     RECT  37.973 45.024 38.837 45.816 ;
     RECT  37.804 25.44 38.869 25.464 ;
     RECT  38.243 14.064 38.873 14.088 ;
     RECT  37.804 67.824 38.881 67.848 ;
     RECT  38.513 69.456 38.908 70.872 ;
     RECT  38.771 66.768 38.909 66.792 ;
     RECT  38.771 54.624 38.915 56.04 ;
     RECT  37.804 11.952 38.945 11.976 ;
     RECT  37.804 27.024 38.965 27.048 ;
     RECT  38.837 45.552 38.981 45.816 ;
     RECT  38.771 47.04 38.981 53.592 ;
     RECT  38.801 64.944 38.981 65.16 ;
     RECT  38.869 24.48 39.011 25.464 ;
     RECT  38.981 45.552 39.017 45.624 ;
     RECT  38.723 62.064 39.017 62.664 ;
     RECT  37.804 10.8 39.053 10.824 ;
     RECT  38.557 31.824 39.053 32.52 ;
     RECT  38.809 33.984 39.053 35.304 ;
     RECT  37.804 43.824 39.053 43.848 ;
     RECT  38.915 54.624 39.053 55.896 ;
     RECT  38.117 18.192 39.089 18.216 ;
     RECT  39.053 35.136 39.089 35.304 ;
     RECT  39.017 45.552 39.125 45.576 ;
     RECT  38.981 64.944 39.125 64.968 ;
     RECT  39.053 33.984 39.161 34.008 ;
     RECT  39.089 35.28 39.161 35.304 ;
     RECT  38.908 70.416 39.161 70.872 ;
     RECT  37.901 7.728 39.197 7.752 ;
     RECT  38.965 26.688 39.197 27.048 ;
     RECT  38.981 49.2 39.197 53.592 ;
     RECT  39.161 70.416 39.197 70.44 ;
     RECT  38.981 47.04 39.233 47.88 ;
     RECT  38.723 58.416 39.445 60.888 ;
     RECT  38.729 6 40.208 6.024 ;
     RECT  38.044 15.456 40.208 15.48 ;
     RECT  39.011 24.48 40.208 24.504 ;
     RECT  39.197 26.736 40.208 27.048 ;
     RECT  39.053 31.824 40.208 31.848 ;
     RECT  38.801 36.768 40.208 36.792 ;
     RECT  38.657 38.448 40.208 38.472 ;
     RECT  38.531 40.992 40.208 41.592 ;
     RECT  39.233 47.04 40.208 47.064 ;
     RECT  39.197 49.2 40.208 52.2 ;
     RECT  39.197 53.568 40.208 53.592 ;
     RECT  39.053 54.672 40.208 55.896 ;
     RECT  39.445 58.128 40.208 60.888 ;
     RECT  39.017 62.208 40.208 62.664 ;
     RECT  38.693 63.696 40.208 63.72 ;
     RECT  38.297 72.144 40.208 72.168 ;
     RECT  38.009 73.488 40.208 73.512 ;
     RECT  40.208 2.148 40.312 75.612 ;
     RECT  40.312 2.418 40.504 75.342 ;
     RECT  40.504 50.64 40.637 50.664 ;
     RECT  40.504 4.656 41.569 5.208 ;
     RECT  40.504 9.936 41.569 9.96 ;
     RECT  40.504 10.992 41.569 11.016 ;
     RECT  40.504 41.376 41.569 41.4 ;
     RECT  40.504 55.728 41.569 55.752 ;
     RECT  40.504 66.192 41.569 66.216 ;
     RECT  40.504 68.304 41.569 68.328 ;
     RECT  40.504 72.528 41.569 72.552 ;
     RECT  40.504 74.112 41.569 74.136 ;
     RECT  41.569 45.6 41.605 45.624 ;
     RECT  41.569 46.656 41.605 46.68 ;
     RECT  41.569 7.824 41.821 8.376 ;
     RECT  41.569 9.408 41.821 9.96 ;
     RECT  40.504 13.632 41.821 13.656 ;
     RECT  41.569 16.8 41.821 17.352 ;
     RECT  41.569 18.912 41.821 18.936 ;
     RECT  41.569 20.496 41.821 20.52 ;
     RECT  40.504 33.696 41.821 33.72 ;
     RECT  41.569 41.376 41.821 42.456 ;
     RECT  41.569 49.824 41.821 50.376 ;
     RECT  41.569 51.408 41.821 51.432 ;
     RECT  41.569 55.728 41.821 56.712 ;
     RECT  40.504 57.744 41.821 57.768 ;
     RECT  41.569 59.856 41.821 59.88 ;
     RECT  41.569 67.776 41.821 68.856 ;
     RECT  41.569 70.944 41.821 70.968 ;
     RECT  41.569 72 41.821 74.136 ;
     RECT  41.569 3.6 41.893 5.208 ;
     RECT  41.569 6.24 41.893 6.264 ;
     RECT  41.569 32.112 41.893 32.136 ;
     RECT  41.821 33.168 41.893 34.248 ;
     RECT  41.821 41.376 41.893 42.984 ;
     RECT  41.569 44.016 41.893 44.04 ;
     RECT  41.821 49.824 41.893 51.432 ;
     RECT  41.569 52.464 41.893 52.488 ;
     RECT  41.569 63.552 41.893 63.576 ;
     RECT  41.893 3.6 42.145 6.264 ;
     RECT  41.821 7.824 42.145 9.96 ;
     RECT  41.569 10.992 42.145 11.544 ;
     RECT  41.821 13.104 42.145 14.184 ;
     RECT  40.504 15.744 42.145 15.768 ;
     RECT  41.821 16.8 42.145 18.936 ;
     RECT  41.821 20.496 42.145 21.048 ;
     RECT  41.569 22.08 42.145 22.104 ;
     RECT  41.569 23.136 42.145 24.744 ;
     RECT  40.504 26.304 42.145 26.328 ;
     RECT  41.569 27.888 42.145 28.44 ;
     RECT  41.569 29.472 42.145 29.496 ;
     RECT  41.821 31.056 42.145 31.08 ;
     RECT  41.893 32.112 42.145 34.248 ;
     RECT  41.893 41.376 42.145 44.04 ;
     RECT  41.605 45.072 42.145 46.68 ;
     RECT  41.569 48.768 42.145 48.792 ;
     RECT  41.893 49.824 42.145 52.488 ;
     RECT  41.821 55.728 42.145 57.768 ;
     RECT  41.569 58.8 42.145 58.824 ;
     RECT  41.893 63.024 42.145 63.576 ;
     RECT  41.569 64.608 42.145 66.216 ;
     RECT  41.821 67.248 42.145 68.856 ;
     RECT  41.821 70.944 42.145 74.136 ;
     RECT  42.145 3.6 42.181 34.248 ;
     RECT  40.504 38.448 42.181 38.472 ;
     RECT  42.181 3.6 43.009 34.776 ;
     RECT  42.145 35.808 43.009 36.36 ;
     RECT  42.145 41.376 43.009 58.824 ;
     RECT  41.821 59.856 43.009 61.464 ;
     RECT  42.181 38.448 43.081 39.384 ;
     RECT  43.009 41.376 43.081 61.464 ;
     RECT  42.145 62.496 43.081 74.136 ;
     RECT  43.081 38.352 43.121 39.384 ;
     RECT  43.009 3.6 43.164 36.36 ;
     RECT  43.121 38.352 43.164 38.376 ;
     RECT  43.121 39.36 43.164 39.384 ;
     RECT  43.081 41.376 43.164 74.136 ;
    LAYER M5 ;
     RECT  21.552 0.016 21.576 2.137 ;
     RECT  2.4 2.137 2.52 2.151 ;
     RECT  5.1 2.137 5.22 2.151 ;
     RECT  7.8 2.137 7.92 2.151 ;
     RECT  10.5 2.137 10.62 2.151 ;
     RECT  13.2 2.137 13.32 2.151 ;
     RECT  15.9 2.137 16.02 2.151 ;
     RECT  18.6 2.137 18.72 2.151 ;
     RECT  21.3 2.137 21.576 2.151 ;
     RECT  24 2.137 24.12 2.151 ;
     RECT  26.7 2.137 26.82 2.151 ;
     RECT  29.4 2.137 29.52 2.151 ;
     RECT  32.1 2.137 32.22 2.151 ;
     RECT  34.8 2.137 34.92 2.151 ;
     RECT  37.5 2.137 37.62 2.151 ;
     RECT  40.2 2.137 40.32 2.151 ;
     RECT  21.3 2.151 21.612 2.485 ;
     RECT  13.2 2.151 13.512 2.581 ;
     RECT  21.168 2.485 21.612 3.059 ;
     RECT  24 2.151 24.312 3.109 ;
     RECT  29.4 2.151 29.712 3.397 ;
     RECT  22.992 2.821 23.016 3.443 ;
     RECT  13.2 2.581 13.656 3.587 ;
     RECT  37.5 2.151 37.812 3.925 ;
     RECT  24 3.109 24.84 5.077 ;
     RECT  26.7 2.151 27.012 5.077 ;
     RECT  37.5 3.925 38.232 5.557 ;
     RECT  17.328 2.869 17.352 5.603 ;
     RECT  15.9 2.151 16.212 5.653 ;
     RECT  10.5 2.151 10.812 5.893 ;
     RECT  13.2 3.587 13.512 5.989 ;
     RECT  21.3 3.059 21.612 6.037 ;
     RECT  23.04 5.077 24.84 6.037 ;
     RECT  26.7 5.077 27.336 6.083 ;
     RECT  29.28 3.397 29.712 6.083 ;
     RECT  31.056 5.029 31.08 6.133 ;
     RECT  37.5 5.557 38.712 6.563 ;
     RECT  21.3 6.037 24.84 6.611 ;
     RECT  30.864 6.133 31.08 6.613 ;
     RECT  32.1 2.151 32.412 6.613 ;
     RECT  10.272 5.893 10.812 6.661 ;
     RECT  20.304 6.709 20.328 6.899 ;
     RECT  34.8 2.151 35.112 7.237 ;
     RECT  18.6 2.151 18.912 7.333 ;
     RECT  9.216 7.381 9.24 7.717 ;
     RECT  10.272 6.661 11.112 7.717 ;
     RECT  33.456 7.717 33.48 7.957 ;
     RECT  34.8 7.237 36.072 7.957 ;
     RECT  33.456 7.957 36.072 8.339 ;
     RECT  33.456 8.339 35.112 8.435 ;
     RECT  21.3 6.611 22.104 9.013 ;
     RECT  24 6.611 24.84 9.013 ;
     RECT  29.4 6.083 29.712 9.061 ;
     RECT  15.9 5.653 17.016 9.155 ;
     RECT  21.3 9.013 24.84 9.299 ;
     RECT  30.864 6.613 32.412 9.493 ;
     RECT  18.6 7.333 19.032 9.923 ;
     RECT  14.592 8.485 14.616 10.021 ;
     RECT  14.592 10.021 14.808 10.067 ;
     RECT  30.816 9.493 32.412 10.307 ;
     RECT  13.104 5.989 13.512 10.451 ;
     RECT  28.56 9.061 29.712 10.883 ;
     RECT  14.784 10.067 14.808 11.077 ;
     RECT  14.592 11.077 14.808 11.123 ;
     RECT  13.2 10.451 13.512 11.173 ;
     RECT  14.592 11.123 14.616 11.173 ;
     RECT  23.04 9.299 24.84 11.221 ;
     RECT  22.8 11.221 24.84 11.267 ;
     RECT  18.6 9.923 18.912 11.365 ;
     RECT  29.4 10.883 29.712 11.941 ;
     RECT  24 11.267 24.84 12.035 ;
     RECT  13.2 11.173 14.616 12.275 ;
     RECT  24 12.035 24.744 12.995 ;
     RECT  37.5 6.563 37.812 13.045 ;
     RECT  18.6 11.365 19.56 13.091 ;
     RECT  22.8 11.267 22.824 13.139 ;
     RECT  7.8 2.151 8.112 13.381 ;
     RECT  9.216 7.717 11.112 13.381 ;
     RECT  18.6 13.091 19.272 14.245 ;
     RECT  15.9 9.155 16.824 14.291 ;
     RECT  7.8 13.381 11.112 14.435 ;
     RECT  21.3 9.299 21.768 14.629 ;
     RECT  34.8 8.435 35.112 14.725 ;
     RECT  29.28 11.941 29.712 14.915 ;
     RECT  24 12.995 24.312 14.917 ;
     RECT  31.056 10.307 32.412 15.397 ;
     RECT  9.216 14.435 11.112 15.491 ;
     RECT  37.5 13.045 38.232 15.491 ;
     RECT  30.816 15.397 32.412 15.731 ;
     RECT  13.2 12.275 13.656 15.779 ;
     RECT  34.8 14.725 35.208 15.829 ;
     RECT  9.264 15.491 11.112 16.019 ;
     RECT  37.5 15.491 37.992 16.019 ;
     RECT  9.312 16.019 11.112 16.501 ;
     RECT  12.096 11.365 12.12 16.501 ;
     RECT  14.88 14.869 14.904 17.029 ;
     RECT  15.9 14.291 16.212 17.029 ;
     RECT  37.5 16.019 37.812 17.029 ;
     RECT  9.312 16.501 12.12 17.075 ;
     RECT  14.88 17.029 16.212 17.075 ;
     RECT  21.3 14.629 21.816 17.077 ;
     RECT  23.28 14.917 24.312 17.077 ;
     RECT  29.4 14.915 29.712 17.077 ;
     RECT  31.104 15.731 32.412 17.077 ;
     RECT  23.28 17.077 25.128 17.123 ;
     RECT  26.7 6.083 27.012 17.125 ;
     RECT  24 17.123 25.128 17.267 ;
     RECT  15.36 17.075 16.212 17.699 ;
     RECT  33.456 8.435 33.48 17.893 ;
     RECT  34.8 15.829 35.928 17.893 ;
     RECT  21.3 17.077 22.104 17.939 ;
     RECT  12.096 17.075 12.12 18.131 ;
     RECT  26.7 17.125 27.384 18.131 ;
     RECT  37.5 17.029 38.184 18.227 ;
     RECT  21.3 17.939 21.612 18.469 ;
     RECT  33.456 17.893 35.928 18.659 ;
     RECT  13.2 15.779 13.512 18.757 ;
     RECT  29.4 17.077 32.412 18.757 ;
     RECT  9.312 17.075 11.112 18.803 ;
     RECT  9.456 18.803 11.112 18.851 ;
     RECT  26.7 18.131 27.012 19.333 ;
     RECT  34.8 18.659 35.928 19.379 ;
     RECT  18.24 14.245 19.272 19.427 ;
     RECT  28.656 18.757 32.412 19.427 ;
     RECT  34.8 19.379 35.352 19.427 ;
     RECT  21.168 18.469 21.612 19.619 ;
     RECT  28.656 19.427 29.712 19.763 ;
     RECT  9.456 18.851 10.968 19.907 ;
     RECT  33.456 18.659 33.576 19.957 ;
     RECT  37.5 18.227 37.944 20.003 ;
     RECT  9.456 19.907 9.48 20.005 ;
     RECT  9.12 20.005 9.48 20.051 ;
     RECT  26.592 19.333 27.012 20.291 ;
     RECT  29.4 19.763 29.712 20.437 ;
     RECT  31.104 19.427 32.412 20.437 ;
     RECT  29.4 20.437 32.412 20.485 ;
     RECT  33.456 19.957 33.624 20.485 ;
     RECT  29.4 20.485 33.624 20.819 ;
     RECT  29.4 20.819 33.48 20.965 ;
     RECT  34.8 19.427 35.112 20.965 ;
     RECT  21.3 19.619 21.612 21.061 ;
     RECT  9.12 20.051 9.144 21.251 ;
     RECT  7.8 14.435 8.112 21.493 ;
     RECT  24 17.267 24.312 21.493 ;
     RECT  13.2 18.757 13.704 21.925 ;
     RECT  37.5 20.003 37.812 22.021 ;
     RECT  37.392 22.021 37.812 22.165 ;
     RECT  18.24 19.427 18.912 22.261 ;
     RECT  21.072 21.061 21.612 22.499 ;
     RECT  28.848 20.965 33.48 22.595 ;
     RECT  17.856 22.261 18.912 22.691 ;
     RECT  13.104 21.925 13.704 22.739 ;
     RECT  6.912 21.493 8.112 23.077 ;
     RECT  24 21.493 24.792 23.269 ;
     RECT  26.7 20.291 27.012 23.653 ;
     RECT  29.4 22.595 33.48 23.797 ;
     RECT  34.8 20.965 35.208 23.845 ;
     RECT  15.648 17.699 16.212 23.893 ;
     RECT  15.648 23.893 16.536 23.987 ;
     RECT  23.376 23.269 24.792 23.987 ;
     RECT  29.136 23.797 33.48 24.037 ;
     RECT  29.136 24.037 33.672 24.131 ;
     RECT  26.7 23.653 27.336 24.133 ;
     RECT  31.104 24.131 33.672 24.179 ;
     RECT  18 22.691 18.912 24.229 ;
     RECT  19.92 23.893 19.944 24.229 ;
     RECT  26.352 24.133 27.336 24.277 ;
     RECT  6.912 23.077 8.568 24.419 ;
     RECT  13.2 22.739 13.704 24.467 ;
     RECT  10.5 19.907 10.968 24.469 ;
     RECT  31.104 24.179 31.128 24.563 ;
     RECT  23.376 23.987 24.312 24.611 ;
     RECT  29.136 24.131 29.832 25.093 ;
     RECT  21.3 22.499 21.612 25.141 ;
     RECT  7.392 24.419 8.568 25.187 ;
     RECT  18 24.229 19.944 25.235 ;
     RECT  29.088 25.093 29.832 25.235 ;
     RECT  15.9 23.987 16.536 25.283 ;
     RECT  7.8 25.187 8.568 25.715 ;
     RECT  26.064 24.277 27.336 25.763 ;
     RECT  32.1 24.179 33.672 25.811 ;
     RECT  18 25.235 18.912 26.197 ;
     RECT  34.704 23.845 35.208 26.197 ;
     RECT  10.32 24.469 10.968 26.243 ;
     RECT  21.3 25.141 22.2 26.243 ;
     RECT  26.064 25.763 27.012 26.243 ;
     RECT  10.32 26.243 10.812 26.291 ;
     RECT  34.704 26.197 35.304 26.291 ;
     RECT  19.92 25.235 19.944 26.339 ;
     RECT  29.4 25.235 29.832 26.533 ;
     RECT  29.4 26.533 30.168 26.629 ;
     RECT  32.1 25.811 33.48 26.629 ;
     RECT  38.976 25.429 39 26.725 ;
     RECT  29.184 26.629 30.168 26.819 ;
     RECT  38.976 26.725 39.096 27.059 ;
     RECT  34.8 26.291 35.304 27.205 ;
     RECT  36.912 22.165 37.812 27.205 ;
     RECT  15.9 25.283 16.212 27.301 ;
     RECT  17.904 26.197 18.912 27.301 ;
     RECT  29.4 26.819 30.168 27.301 ;
     RECT  31.872 26.629 33.48 27.445 ;
     RECT  34.8 27.205 37.812 27.445 ;
     RECT  21.3 26.243 21.612 27.781 ;
     RECT  26.7 26.243 27.012 27.781 ;
     RECT  29.4 27.301 30.792 27.971 ;
     RECT  7.8 25.715 8.112 28.213 ;
     RECT  14.832 27.589 14.856 28.213 ;
     RECT  15.9 27.301 18.912 28.213 ;
     RECT  14.832 28.213 18.912 28.259 ;
     RECT  10.5 26.291 10.812 28.309 ;
     RECT  29.4 27.971 30.216 28.309 ;
     RECT  15.36 28.259 18.912 28.355 ;
     RECT  26.7 27.781 27.816 28.355 ;
     RECT  10.5 28.309 11.736 28.501 ;
     RECT  13.2 24.467 13.512 28.501 ;
     RECT  20.496 27.781 21.612 28.979 ;
     RECT  31.872 27.445 37.812 29.075 ;
     RECT  31.872 29.075 33.48 29.317 ;
     RECT  24 24.611 24.312 29.509 ;
     RECT  28.944 28.309 30.216 29.699 ;
     RECT  7.8 28.213 8.328 29.749 ;
     RECT  28.944 29.699 29.712 29.749 ;
     RECT  26.7 28.355 27.48 29.893 ;
     RECT  28.8 29.749 29.712 29.893 ;
     RECT  15.36 28.355 16.212 30.037 ;
     RECT  10.5 28.501 13.512 30.133 ;
     RECT  34.8 29.075 37.812 30.181 ;
     RECT  39.072 27.059 39.096 30.181 ;
     RECT  22.896 28.981 22.92 30.275 ;
     RECT  34.8 30.181 39.096 30.419 ;
     RECT  24 29.509 24.456 30.515 ;
     RECT  10.176 30.133 13.512 30.851 ;
     RECT  15.36 30.037 16.968 30.853 ;
     RECT  18 28.355 18.912 30.853 ;
     RECT  7.68 29.749 8.328 30.899 ;
     RECT  7.68 30.899 8.112 31.189 ;
     RECT  26.7 29.893 29.712 31.525 ;
     RECT  21.3 28.979 21.612 31.861 ;
     RECT  15.36 30.853 18.912 31.955 ;
     RECT  13.2 30.851 13.512 32.101 ;
     RECT  10.176 30.851 11.832 32.195 ;
     RECT  21.168 31.861 21.612 32.437 ;
     RECT  26.496 31.525 29.712 32.437 ;
     RECT  17.76 31.955 18.912 32.579 ;
     RECT  21.168 32.437 21.96 32.581 ;
     RECT  24 30.515 24.312 33.013 ;
     RECT  25.632 32.437 29.712 33.251 ;
     RECT  7.44 31.189 8.112 33.299 ;
     RECT  7.8 33.299 8.112 33.445 ;
     RECT  9.12 33.349 9.144 33.445 ;
     RECT  20.544 32.581 21.96 33.635 ;
     RECT  20.544 33.635 21.612 33.683 ;
     RECT  31.68 29.317 33.48 33.925 ;
     RECT  34.8 30.419 35.112 33.925 ;
     RECT  7.8 33.445 9.144 34.163 ;
     RECT  26.7 33.251 29.712 34.211 ;
     RECT  28.08 34.211 29.712 34.259 ;
     RECT  10.176 32.195 10.812 34.645 ;
     RECT  25.632 33.251 25.656 34.741 ;
     RECT  26.7 34.211 27.012 34.741 ;
     RECT  31.68 33.925 35.112 34.741 ;
     RECT  28.08 34.259 28.104 34.787 ;
     RECT  11.808 32.195 11.832 34.883 ;
     RECT  13.104 32.101 13.512 34.885 ;
     RECT  15.36 31.955 16.212 34.931 ;
     RECT  25.632 34.741 27.012 35.027 ;
     RECT  23.904 33.013 24.312 35.219 ;
     RECT  7.8 34.163 8.472 35.317 ;
     RECT  25.632 35.027 25.656 35.363 ;
     RECT  9.552 34.645 10.812 35.939 ;
     RECT  12.48 34.885 13.512 35.939 ;
     RECT  29.136 34.259 29.712 35.939 ;
     RECT  21.168 33.683 21.612 35.941 ;
     RECT  6.816 35.317 8.472 36.085 ;
     RECT  22.752 35.845 22.776 36.515 ;
     RECT  30.72 34.741 35.112 36.563 ;
     RECT  6.816 36.085 8.568 36.803 ;
     RECT  7.68 36.803 8.568 36.899 ;
     RECT  30.72 36.563 32.412 36.947 ;
     RECT  20.544 35.941 21.612 37.043 ;
     RECT  9.6 35.939 10.812 37.331 ;
     RECT  13.2 35.939 13.512 37.573 ;
     RECT  7.8 36.899 8.568 37.859 ;
     RECT  12.528 37.573 13.512 38.051 ;
     RECT  31.68 36.947 32.412 38.149 ;
     RECT  24 35.219 24.312 38.437 ;
     RECT  13.2 38.051 13.512 39.637 ;
     RECT  33.456 36.563 35.112 39.829 ;
     RECT  10.176 37.331 10.812 39.877 ;
     RECT  21.168 37.043 21.612 40.067 ;
     RECT  21.3 40.067 21.612 40.405 ;
     RECT  18 32.579 18.912 40.453 ;
     RECT  23.28 38.437 24.312 40.499 ;
     RECT  7.8 37.859 8.376 40.741 ;
     RECT  31.632 38.149 32.412 40.837 ;
     RECT  18 40.453 19.032 40.931 ;
     RECT  18.096 40.931 19.032 41.027 ;
     RECT  33.456 39.829 35.208 41.365 ;
     RECT  36.24 30.419 39.096 41.365 ;
     RECT  13.008 39.637 13.512 41.413 ;
     RECT  7.8 40.741 9.096 41.557 ;
     RECT  10.176 39.877 11.736 41.557 ;
     RECT  21.3 40.405 22.248 41.557 ;
     RECT  7.8 41.557 11.736 41.651 ;
     RECT  13.008 41.413 13.656 41.989 ;
     RECT  29.4 35.939 29.712 42.085 ;
     RECT  20.544 41.557 22.248 42.227 ;
     RECT  33.456 41.365 39.096 42.227 ;
     RECT  23.904 40.499 24.312 42.515 ;
     RECT  24 42.515 24.312 42.565 ;
     RECT  24 42.565 24.504 42.661 ;
     RECT  21.12 42.227 22.248 42.755 ;
     RECT  24 42.661 24.888 42.805 ;
     RECT  31.392 40.837 32.412 42.805 ;
     RECT  33.456 42.227 38.088 42.805 ;
     RECT  31.392 42.805 38.088 42.851 ;
     RECT  31.536 42.851 38.088 43.091 ;
     RECT  15.9 34.931 16.212 43.285 ;
     RECT  12.144 41.989 13.656 43.571 ;
     RECT  7.8 41.651 10.812 43.813 ;
     RECT  26.7 35.027 27.012 44.389 ;
     RECT  21.12 42.755 21.612 44.437 ;
     RECT  24 42.805 25.128 44.723 ;
     RECT  7.392 43.813 10.812 44.965 ;
     RECT  12.144 43.571 13.512 45.059 ;
     RECT  14.64 44.965 14.664 45.107 ;
     RECT  29.4 42.085 30.408 45.155 ;
     RECT  20.544 44.437 21.612 45.253 ;
     RECT  36.24 43.091 38.088 45.445 ;
     RECT  39.072 42.227 39.096 45.445 ;
     RECT  15.9 43.285 16.44 45.587 ;
     RECT  31.536 43.091 35.208 45.635 ;
     RECT  13.008 45.059 13.512 45.829 ;
     RECT  26.7 44.389 27.528 45.875 ;
     RECT  18.096 41.027 18.912 46.069 ;
     RECT  20.16 45.253 21.612 46.069 ;
     RECT  29.4 45.155 29.712 46.261 ;
     RECT  31.536 45.635 35.112 46.787 ;
     RECT  33.936 46.787 35.112 46.931 ;
     RECT  34.128 46.931 35.112 46.933 ;
     RECT  36.24 45.445 39.096 46.933 ;
     RECT  13.008 45.829 13.608 47.171 ;
     RECT  13.008 47.171 13.512 47.221 ;
     RECT  24 44.723 24.792 47.269 ;
     RECT  26.7 45.875 27.384 47.363 ;
     RECT  29.4 46.261 30.264 47.363 ;
     RECT  31.536 46.787 32.52 47.459 ;
     RECT  18.096 46.069 21.612 47.555 ;
     RECT  20.16 47.555 21.612 47.939 ;
     RECT  24 47.269 25.416 48.083 ;
     RECT  34.128 46.933 39.096 48.181 ;
     RECT  33.984 48.181 39.096 48.229 ;
     RECT  15.9 45.587 16.344 48.373 ;
     RECT  33.744 48.229 39.096 48.515 ;
     RECT  7.056 44.965 10.812 48.613 ;
     RECT  12.96 47.221 13.512 48.661 ;
     RECT  29.4 47.363 29.976 49.091 ;
     RECT  26.7 47.363 27.012 49.477 ;
     RECT  31.536 47.459 32.412 49.909 ;
     RECT  33.744 48.515 37.812 49.909 ;
     RECT  38.784 48.515 39.096 49.909 ;
     RECT  30.864 49.909 32.412 50.053 ;
     RECT  33.744 49.909 39.096 50.053 ;
     RECT  30.864 50.053 39.096 50.099 ;
     RECT  34.464 50.099 39.096 50.101 ;
     RECT  40.2 2.151 40.512 50.101 ;
     RECT  26.7 49.477 27.144 50.339 ;
     RECT  6.864 48.613 10.812 50.677 ;
     RECT  24 48.083 24.792 50.677 ;
     RECT  12.816 48.661 13.512 50.773 ;
     RECT  34.464 50.101 40.512 50.819 ;
     RECT  12.768 50.773 13.512 50.821 ;
     RECT  24 50.677 25.512 51.253 ;
     RECT  26.7 50.339 27.012 51.253 ;
     RECT  30.864 50.099 33.048 51.397 ;
     RECT  34.464 50.819 37.812 51.397 ;
     RECT  12.768 50.821 14.328 51.829 ;
     RECT  24 51.253 27.012 51.877 ;
     RECT  15.9 48.373 16.392 51.971 ;
     RECT  6.864 50.677 11.112 52.067 ;
     RECT  12.768 51.829 14.424 52.451 ;
     RECT  24 51.877 27.672 52.499 ;
     RECT  30.864 51.397 37.812 52.739 ;
     RECT  15.9 51.971 16.344 52.789 ;
     RECT  15.792 52.789 16.344 52.981 ;
     RECT  20.16 47.939 20.184 52.981 ;
     RECT  34.8 52.739 37.812 52.981 ;
     RECT  39.072 50.819 40.512 52.981 ;
     RECT  26.7 52.499 27.672 53.173 ;
     RECT  19.92 52.981 20.184 53.557 ;
     RECT  21.3 47.939 21.612 53.557 ;
     RECT  15.792 52.981 16.536 53.603 ;
     RECT  7.8 52.067 11.112 53.605 ;
     RECT  15.9 53.603 16.536 53.651 ;
     RECT  24 52.499 25.512 53.795 ;
     RECT  7.44 53.605 11.112 54.035 ;
     RECT  26.7 53.173 27.912 54.323 ;
     RECT  7.44 54.035 10.92 54.515 ;
     RECT  30.864 52.739 33.624 54.613 ;
     RECT  19.92 53.557 21.612 54.755 ;
     RECT  25.632 54.085 25.656 54.755 ;
     RECT  30.768 54.613 33.624 54.755 ;
     RECT  12.96 52.451 14.424 55.045 ;
     RECT  34.8 52.981 40.512 55.141 ;
     RECT  15.9 53.651 16.344 55.237 ;
     RECT  19.92 54.755 19.944 55.331 ;
     RECT  30.864 54.755 33.624 55.331 ;
     RECT  34.704 55.141 40.512 55.715 ;
     RECT  15.9 55.237 17.112 55.765 ;
     RECT  34.8 55.715 40.512 55.907 ;
     RECT  12 55.045 14.424 56.243 ;
     RECT  31.68 55.331 33.624 56.533 ;
     RECT  12 56.243 13.944 56.675 ;
     RECT  18.096 47.555 18.912 56.819 ;
     RECT  15.792 55.765 17.112 56.965 ;
     RECT  15.36 56.965 17.112 57.013 ;
     RECT  15.36 57.013 17.304 57.059 ;
     RECT  17.184 57.059 17.304 57.395 ;
     RECT  18.6 56.819 18.912 57.541 ;
     RECT  17.184 57.395 17.208 57.635 ;
     RECT  30.912 56.533 33.624 57.635 ;
     RECT  18.6 57.541 19.944 57.685 ;
     RECT  31.968 57.635 33.624 58.117 ;
     RECT  34.8 55.907 39.096 58.117 ;
     RECT  40.2 55.907 40.512 58.117 ;
     RECT  7.44 54.515 10.812 58.163 ;
     RECT  18.6 57.685 20.136 58.403 ;
     RECT  24 53.795 24.312 58.645 ;
     RECT  30.912 57.635 30.936 58.787 ;
     RECT  18.6 58.403 18.912 59.029 ;
     RECT  31.968 58.117 40.512 59.075 ;
     RECT  18.48 59.029 18.912 59.125 ;
     RECT  31.968 59.075 39.096 59.219 ;
     RECT  26.7 54.323 27.012 59.221 ;
     RECT  18.384 59.125 18.912 59.363 ;
     RECT  20.112 58.403 20.136 59.459 ;
     RECT  12.96 56.675 13.944 59.605 ;
     RECT  15.36 57.059 16.212 59.605 ;
     RECT  21.3 54.755 21.612 59.797 ;
     RECT  12.96 59.605 16.212 60.133 ;
     RECT  23.664 58.645 24.312 60.133 ;
     RECT  25.776 59.221 27.012 60.275 ;
     RECT  31.968 59.219 38.76 60.563 ;
     RECT  31.968 60.563 38.712 60.707 ;
     RECT  34.8 60.707 38.712 60.851 ;
     RECT  12.96 60.133 17.016 60.949 ;
     RECT  29.4 49.091 29.712 60.949 ;
     RECT  12.96 60.949 17.112 61.043 ;
     RECT  21.072 59.797 21.612 61.091 ;
     RECT  18.48 59.363 18.912 61.139 ;
     RECT  15.36 61.043 17.112 61.237 ;
     RECT  18.6 61.139 18.912 61.525 ;
     RECT  31.968 60.707 33.624 61.573 ;
     RECT  12.96 61.043 14.04 61.957 ;
     RECT  15.36 61.237 17.448 62.003 ;
     RECT  15.9 62.003 17.448 62.195 ;
     RECT  31.296 61.573 33.624 62.195 ;
     RECT  21.3 61.091 21.612 62.629 ;
     RECT  36.912 60.851 38.712 62.675 ;
     RECT  34.8 60.851 35.88 62.725 ;
     RECT  36.912 62.675 38.52 62.725 ;
     RECT  18.6 61.525 19.368 63.011 ;
     RECT  31.92 62.195 33.624 63.011 ;
     RECT  12.384 61.957 14.04 63.205 ;
     RECT  21.072 62.629 21.612 63.539 ;
     RECT  34.8 62.725 38.52 63.779 ;
     RECT  15.9 62.195 16.536 63.827 ;
     RECT  31.968 63.011 33.624 63.875 ;
     RECT  36.912 63.779 38.52 63.875 ;
     RECT  23.376 60.133 24.312 64.019 ;
     RECT  30.816 62.725 30.84 64.211 ;
     RECT  28.992 60.949 29.712 64.309 ;
     RECT  18.6 63.011 18.912 64.357 ;
     RECT  7.488 58.163 10.812 64.451 ;
     RECT  31.968 63.875 33.144 64.693 ;
     RECT  37.008 63.875 38.52 64.837 ;
     RECT  34.8 63.779 35.88 64.885 ;
     RECT  37.008 64.837 38.616 64.885 ;
     RECT  28.464 64.309 29.712 64.933 ;
     RECT  12.384 63.205 14.856 65.027 ;
     RECT  28.464 64.933 30.024 65.027 ;
     RECT  15.9 63.827 16.344 65.125 ;
     RECT  34.8 64.885 38.616 65.125 ;
     RECT  10.368 64.451 10.812 65.509 ;
     RECT  15.9 65.125 16.536 65.603 ;
     RECT  28.992 65.027 30.024 65.603 ;
     RECT  28.992 65.603 29.712 65.651 ;
     RECT  10.368 65.509 11.4 65.845 ;
     RECT  12.384 65.027 13.944 65.845 ;
     RECT  7.488 64.451 8.112 66.085 ;
     RECT  26.7 60.275 27.012 66.133 ;
     RECT  18.6 64.357 19.416 66.179 ;
     RECT  10.368 65.845 13.944 66.275 ;
     RECT  15.9 65.603 16.488 66.565 ;
     RECT  10.5 66.275 13.944 66.659 ;
     RECT  26.16 66.133 27.012 66.707 ;
     RECT  24 64.019 24.312 66.709 ;
     RECT  7.488 66.085 8.568 66.755 ;
     RECT  34.8 65.125 38.76 66.755 ;
     RECT  34.8 66.755 38.616 66.803 ;
     RECT  24 66.709 24.408 66.853 ;
     RECT  23.808 66.853 24.408 66.995 ;
     RECT  34.8 66.803 37.812 67.043 ;
     RECT  31.92 64.693 33.144 67.237 ;
     RECT  27.984 65.845 28.008 67.283 ;
     RECT  31.104 67.237 33.144 67.477 ;
     RECT  34.8 67.043 35.832 67.477 ;
     RECT  18.6 66.179 18.912 67.669 ;
     RECT  26.7 66.707 27.012 67.669 ;
     RECT  7.584 66.755 8.568 67.717 ;
     RECT  7.584 67.717 9.048 67.813 ;
     RECT  12.24 66.659 13.944 67.859 ;
     RECT  31.104 67.477 35.832 68.243 ;
     RECT  26.064 67.669 27.012 68.435 ;
     RECT  34.8 68.243 35.832 68.435 ;
     RECT  34.8 68.435 35.736 68.483 ;
     RECT  31.104 68.243 33.672 68.627 ;
     RECT  7.488 67.813 9.048 68.725 ;
     RECT  15.9 66.565 16.536 68.915 ;
     RECT  10.5 66.659 10.812 68.965 ;
     RECT  12.24 67.859 13.512 68.965 ;
     RECT  20.208 66.853 20.232 69.011 ;
     RECT  7.488 68.725 9.528 69.445 ;
     RECT  31.92 68.627 33.672 69.491 ;
     RECT  6.96 69.445 9.528 69.493 ;
     RECT  10.5 68.965 13.512 69.493 ;
     RECT  17.856 67.669 18.912 69.493 ;
     RECT  23.808 66.995 24.312 69.493 ;
     RECT  15.9 68.915 16.344 69.587 ;
     RECT  23.808 69.493 24.456 69.829 ;
     RECT  21.3 63.539 21.612 69.973 ;
     RECT  38.832 67.813 38.856 70.259 ;
     RECT  31.92 69.491 33.336 70.355 ;
     RECT  31.968 70.355 33.336 70.451 ;
     RECT  21.072 69.973 21.612 70.645 ;
     RECT  34.8 68.483 35.208 70.739 ;
     RECT  26.7 68.435 27.012 70.981 ;
     RECT  23.808 69.829 24.504 71.075 ;
     RECT  20.304 70.645 21.612 71.219 ;
     RECT  26.7 70.981 27.336 71.507 ;
     RECT  37.5 67.043 37.812 71.701 ;
     RECT  38.784 70.645 38.808 71.701 ;
     RECT  24 71.075 24.504 71.747 ;
     RECT  34.8 70.739 35.112 71.797 ;
     RECT  6.96 69.493 13.512 71.845 ;
     RECT  17.664 69.493 18.912 72.179 ;
     RECT  37.5 71.701 38.808 72.179 ;
     RECT  17.856 72.179 18.912 72.419 ;
     RECT  25.344 71.797 25.368 72.419 ;
     RECT  26.7 71.507 27.144 72.419 ;
     RECT  32.1 70.451 33.336 72.419 ;
     RECT  36.48 71.221 36.504 72.419 ;
     RECT  37.5 72.179 37.944 72.467 ;
     RECT  21.072 71.219 21.612 72.851 ;
     RECT  34.8 71.797 35.304 72.851 ;
     RECT  14.832 70.693 14.856 72.995 ;
     RECT  21.3 72.851 21.612 73.093 ;
     RECT  18.6 72.419 18.912 73.477 ;
     RECT  37.5 72.467 37.812 74.053 ;
     RECT  26.7 72.419 27.012 74.149 ;
     RECT  29.4 65.651 29.712 74.533 ;
     RECT  24 71.747 24.312 74.629 ;
     RECT  29.4 74.533 30.792 74.675 ;
     RECT  37.248 74.053 37.812 74.723 ;
     RECT  30.768 74.675 30.792 74.725 ;
     RECT  30.768 74.725 30.888 74.867 ;
     RECT  6.96 71.845 13.608 74.915 ;
     RECT  24 74.629 25.272 75.155 ;
     RECT  21.3 73.093 22.248 75.251 ;
     RECT  6.96 74.915 13.512 75.253 ;
     RECT  26.7 74.149 27.384 75.299 ;
     RECT  18.48 73.477 18.912 75.395 ;
     RECT  30.864 74.867 30.888 75.395 ;
     RECT  2.4 2.151 2.712 75.609 ;
     RECT  5.1 2.151 5.412 75.609 ;
     RECT  6.528 75.253 13.512 75.609 ;
     RECT  15.9 69.587 16.212 75.609 ;
     RECT  18.6 75.395 18.912 75.609 ;
     RECT  21.3 75.251 21.612 75.609 ;
     RECT  24 75.155 24.312 75.609 ;
     RECT  26.7 75.299 27.012 75.609 ;
     RECT  29.4 74.675 29.712 75.609 ;
     RECT  32.1 72.419 32.412 75.609 ;
     RECT  34.8 72.851 35.112 75.609 ;
     RECT  37.5 74.723 37.812 75.609 ;
     RECT  40.2 59.075 40.512 75.609 ;
     RECT  2.4 75.609 2.52 75.623 ;
     RECT  5.1 75.609 5.22 75.623 ;
     RECT  6.528 75.609 13.32 75.623 ;
     RECT  15.9 75.609 16.02 75.623 ;
     RECT  18.6 75.609 18.72 75.623 ;
     RECT  21.3 75.609 21.576 75.623 ;
     RECT  24 75.609 24.12 75.623 ;
     RECT  26.7 75.609 26.82 75.623 ;
     RECT  29.4 75.609 29.52 75.623 ;
     RECT  32.1 75.609 32.22 75.623 ;
     RECT  34.8 75.609 34.92 75.623 ;
     RECT  37.5 75.609 37.62 75.623 ;
     RECT  40.2 75.609 40.32 75.623 ;
     RECT  6.528 75.623 12.792 76.691 ;
     RECT  6.528 76.691 12.696 76.933 ;
     RECT  6.432 76.933 12.696 77.712 ;
     RECT  21.552 75.623 21.576 77.712 ;
  END
END dsfd_node_LLfu
END LIBRARY
